VERSION 5.8 ;
BUSBITCHARS "[]" ;
DIVIDERCHAR "/" ;
UNITS
    DATABASE MICRONS 1000 ;
END UNITS

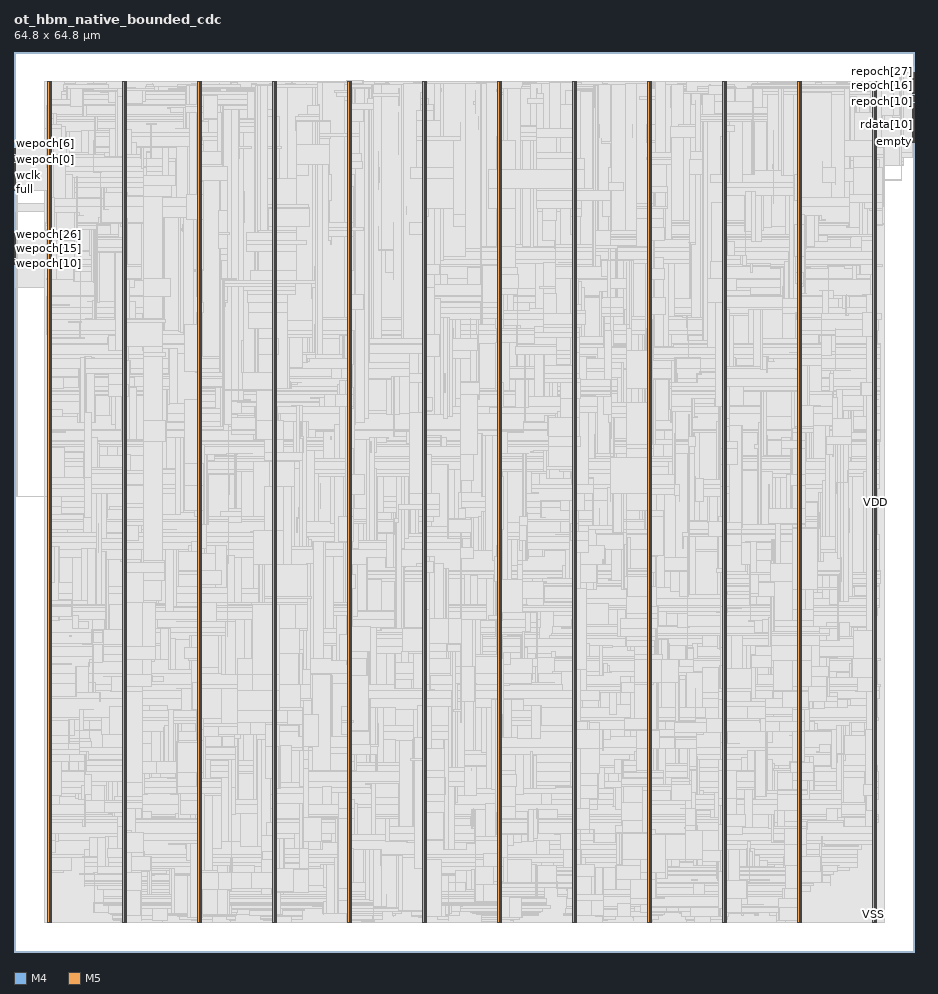
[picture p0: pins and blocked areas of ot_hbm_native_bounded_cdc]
MACRO ot_hbm_native_bounded_cdc
  FOREIGN ot_hbm_native_bounded_cdc 0 0 ;
  CLASS BLOCK ;
  SIZE 64.8 BY 64.8 ;
  PIN empty
    DIRECTION OUTPUT ;
    USE SIGNAL ;
    PORT
      LAYER M4 ;
        RECT  64.716 58.32 64.8 58.344 ;
    END
  END empty
  PIN full
    DIRECTION OUTPUT ;
    USE SIGNAL ;
    PORT
      LAYER M4 ;
        RECT  0 54.864 0.084 54.888 ;
    END
  END full
  PIN r_fault
    DIRECTION OUTPUT ;
    USE SIGNAL ;
    PORT
      LAYER M4 ;
        RECT  64.716 58.416 64.8 58.44 ;
    END
  END r_fault
  PIN rclk
    DIRECTION INPUT ;
    USE SIGNAL ;
    PORT
      LAYER M4 ;
        RECT  64.716 58.512 64.8 58.536 ;
    END
  END rclk
  PIN rd_freed[0]
    DIRECTION OUTPUT ;
    USE SIGNAL ;
    PORT
      LAYER M4 ;
        RECT  0 54.96 0.084 54.984 ;
    END
  END rd_freed[0]
  PIN rd_freed[1]
    DIRECTION OUTPUT ;
    USE SIGNAL ;
    PORT
      LAYER M4 ;
        RECT  0 55.056 0.084 55.08 ;
    END
  END rd_freed[1]
  PIN rd_freed[2]
    DIRECTION OUTPUT ;
    USE SIGNAL ;
    PORT
      LAYER M4 ;
        RECT  0 55.152 0.084 55.176 ;
    END
  END rd_freed[2]
  PIN rdata[0]
    DIRECTION OUTPUT ;
    USE SIGNAL ;
    PORT
      LAYER M4 ;
        RECT  64.716 58.608 64.8 58.632 ;
    END
  END rdata[0]
  PIN rdata[10]
    DIRECTION OUTPUT ;
    USE SIGNAL ;
    PORT
      LAYER M4 ;
        RECT  64.716 59.568 64.8 59.592 ;
    END
  END rdata[10]
  PIN rdata[11]
    DIRECTION OUTPUT ;
    USE SIGNAL ;
    PORT
      LAYER M4 ;
        RECT  64.716 59.664 64.8 59.688 ;
    END
  END rdata[11]
  PIN rdata[12]
    DIRECTION OUTPUT ;
    USE SIGNAL ;
    PORT
      LAYER M4 ;
        RECT  64.716 59.76 64.8 59.784 ;
    END
  END rdata[12]
  PIN rdata[13]
    DIRECTION OUTPUT ;
    USE SIGNAL ;
    PORT
      LAYER M4 ;
        RECT  64.716 59.856 64.8 59.88 ;
    END
  END rdata[13]
  PIN rdata[14]
    DIRECTION OUTPUT ;
    USE SIGNAL ;
    PORT
      LAYER M4 ;
        RECT  64.716 59.952 64.8 59.976 ;
    END
  END rdata[14]
  PIN rdata[15]
    DIRECTION OUTPUT ;
    USE SIGNAL ;
    PORT
      LAYER M4 ;
        RECT  64.716 60.048 64.8 60.072 ;
    END
  END rdata[15]
  PIN rdata[1]
    DIRECTION OUTPUT ;
    USE SIGNAL ;
    PORT
      LAYER M4 ;
        RECT  64.716 58.704 64.8 58.728 ;
    END
  END rdata[1]
  PIN rdata[2]
    DIRECTION OUTPUT ;
    USE SIGNAL ;
    PORT
      LAYER M4 ;
        RECT  64.716 58.8 64.8 58.824 ;
    END
  END rdata[2]
  PIN rdata[3]
    DIRECTION OUTPUT ;
    USE SIGNAL ;
    PORT
      LAYER M4 ;
        RECT  64.716 58.896 64.8 58.92 ;
    END
  END rdata[3]
  PIN rdata[4]
    DIRECTION OUTPUT ;
    USE SIGNAL ;
    PORT
      LAYER M4 ;
        RECT  64.716 58.992 64.8 59.016 ;
    END
  END rdata[4]
  PIN rdata[5]
    DIRECTION OUTPUT ;
    USE SIGNAL ;
    PORT
      LAYER M4 ;
        RECT  64.716 59.088 64.8 59.112 ;
    END
  END rdata[5]
  PIN rdata[6]
    DIRECTION OUTPUT ;
    USE SIGNAL ;
    PORT
      LAYER M4 ;
        RECT  64.716 59.184 64.8 59.208 ;
    END
  END rdata[6]
  PIN rdata[7]
    DIRECTION OUTPUT ;
    USE SIGNAL ;
    PORT
      LAYER M4 ;
        RECT  64.716 59.28 64.8 59.304 ;
    END
  END rdata[7]
  PIN rdata[8]
    DIRECTION OUTPUT ;
    USE SIGNAL ;
    PORT
      LAYER M4 ;
        RECT  64.716 59.376 64.8 59.4 ;
    END
  END rdata[8]
  PIN rdata[9]
    DIRECTION OUTPUT ;
    USE SIGNAL ;
    PORT
      LAYER M4 ;
        RECT  64.716 59.472 64.8 59.496 ;
    END
  END rdata[9]
  PIN re
    DIRECTION INPUT ;
    USE SIGNAL ;
    PORT
      LAYER M4 ;
        RECT  64.716 60.144 64.8 60.168 ;
    END
  END re
  PIN repoch[0]
    DIRECTION INPUT ;
    USE SIGNAL ;
    PORT
      LAYER M4 ;
        RECT  64.716 60.24 64.8 60.264 ;
    END
  END repoch[0]
  PIN repoch[10]
    DIRECTION INPUT ;
    USE SIGNAL ;
    PORT
      LAYER M4 ;
        RECT  64.716 61.2 64.8 61.224 ;
    END
  END repoch[10]
  PIN repoch[11]
    DIRECTION INPUT ;
    USE SIGNAL ;
    PORT
      LAYER M4 ;
        RECT  64.716 61.296 64.8 61.32 ;
    END
  END repoch[11]
  PIN repoch[12]
    DIRECTION INPUT ;
    USE SIGNAL ;
    PORT
      LAYER M4 ;
        RECT  64.716 61.392 64.8 61.416 ;
    END
  END repoch[12]
  PIN repoch[13]
    DIRECTION INPUT ;
    USE SIGNAL ;
    PORT
      LAYER M4 ;
        RECT  64.716 61.488 64.8 61.512 ;
    END
  END repoch[13]
  PIN repoch[14]
    DIRECTION INPUT ;
    USE SIGNAL ;
    PORT
      LAYER M4 ;
        RECT  64.716 61.584 64.8 61.608 ;
    END
  END repoch[14]
  PIN repoch[15]
    DIRECTION INPUT ;
    USE SIGNAL ;
    PORT
      LAYER M4 ;
        RECT  64.716 61.68 64.8 61.704 ;
    END
  END repoch[15]
  PIN repoch[16]
    DIRECTION INPUT ;
    USE SIGNAL ;
    PORT
      LAYER M4 ;
        RECT  64.716 61.776 64.8 61.8 ;
    END
  END repoch[16]
  PIN repoch[17]
    DIRECTION INPUT ;
    USE SIGNAL ;
    PORT
      LAYER M4 ;
        RECT  64.716 61.872 64.8 61.896 ;
    END
  END repoch[17]
  PIN repoch[18]
    DIRECTION INPUT ;
    USE SIGNAL ;
    PORT
      LAYER M4 ;
        RECT  64.716 61.968 64.8 61.992 ;
    END
  END repoch[18]
  PIN repoch[19]
    DIRECTION INPUT ;
    USE SIGNAL ;
    PORT
      LAYER M4 ;
        RECT  64.716 62.064 64.8 62.088 ;
    END
  END repoch[19]
  PIN repoch[1]
    DIRECTION INPUT ;
    USE SIGNAL ;
    PORT
      LAYER M4 ;
        RECT  64.716 60.336 64.8 60.36 ;
    END
  END repoch[1]
  PIN repoch[20]
    DIRECTION INPUT ;
    USE SIGNAL ;
    PORT
      LAYER M4 ;
        RECT  64.716 62.16 64.8 62.184 ;
    END
  END repoch[20]
  PIN repoch[21]
    DIRECTION INPUT ;
    USE SIGNAL ;
    PORT
      LAYER M4 ;
        RECT  64.716 62.256 64.8 62.28 ;
    END
  END repoch[21]
  PIN repoch[22]
    DIRECTION INPUT ;
    USE SIGNAL ;
    PORT
      LAYER M4 ;
        RECT  64.716 62.352 64.8 62.376 ;
    END
  END repoch[22]
  PIN repoch[23]
    DIRECTION INPUT ;
    USE SIGNAL ;
    PORT
      LAYER M4 ;
        RECT  64.716 62.448 64.8 62.472 ;
    END
  END repoch[23]
  PIN repoch[24]
    DIRECTION INPUT ;
    USE SIGNAL ;
    PORT
      LAYER M4 ;
        RECT  64.716 62.544 64.8 62.568 ;
    END
  END repoch[24]
  PIN repoch[25]
    DIRECTION INPUT ;
    USE SIGNAL ;
    PORT
      LAYER M4 ;
        RECT  64.716 62.64 64.8 62.664 ;
    END
  END repoch[25]
  PIN repoch[26]
    DIRECTION INPUT ;
    USE SIGNAL ;
    PORT
      LAYER M4 ;
        RECT  64.716 62.736 64.8 62.76 ;
    END
  END repoch[26]
  PIN repoch[27]
    DIRECTION INPUT ;
    USE SIGNAL ;
    PORT
      LAYER M4 ;
        RECT  64.716 62.832 64.8 62.856 ;
    END
  END repoch[27]
  PIN repoch[28]
    DIRECTION INPUT ;
    USE SIGNAL ;
    PORT
      LAYER M4 ;
        RECT  64.716 62.928 64.8 62.952 ;
    END
  END repoch[28]
  PIN repoch[29]
    DIRECTION INPUT ;
    USE SIGNAL ;
    PORT
      LAYER M4 ;
        RECT  64.716 63.024 64.8 63.048 ;
    END
  END repoch[29]
  PIN repoch[2]
    DIRECTION INPUT ;
    USE SIGNAL ;
    PORT
      LAYER M4 ;
        RECT  64.716 60.432 64.8 60.456 ;
    END
  END repoch[2]
  PIN repoch[30]
    DIRECTION INPUT ;
    USE SIGNAL ;
    PORT
      LAYER M4 ;
        RECT  64.716 63.12 64.8 63.144 ;
    END
  END repoch[30]
  PIN repoch[31]
    DIRECTION INPUT ;
    USE SIGNAL ;
    PORT
      LAYER M4 ;
        RECT  64.716 63.216 64.8 63.24 ;
    END
  END repoch[31]
  PIN repoch[3]
    DIRECTION INPUT ;
    USE SIGNAL ;
    PORT
      LAYER M4 ;
        RECT  64.716 60.528 64.8 60.552 ;
    END
  END repoch[3]
  PIN repoch[4]
    DIRECTION INPUT ;
    USE SIGNAL ;
    PORT
      LAYER M4 ;
        RECT  64.716 60.624 64.8 60.648 ;
    END
  END repoch[4]
  PIN repoch[5]
    DIRECTION INPUT ;
    USE SIGNAL ;
    PORT
      LAYER M4 ;
        RECT  64.716 60.72 64.8 60.744 ;
    END
  END repoch[5]
  PIN repoch[6]
    DIRECTION INPUT ;
    USE SIGNAL ;
    PORT
      LAYER M4 ;
        RECT  64.716 60.816 64.8 60.84 ;
    END
  END repoch[6]
  PIN repoch[7]
    DIRECTION INPUT ;
    USE SIGNAL ;
    PORT
      LAYER M4 ;
        RECT  64.716 60.912 64.8 60.936 ;
    END
  END repoch[7]
  PIN repoch[8]
    DIRECTION INPUT ;
    USE SIGNAL ;
    PORT
      LAYER M4 ;
        RECT  64.716 61.008 64.8 61.032 ;
    END
  END repoch[8]
  PIN repoch[9]
    DIRECTION INPUT ;
    USE SIGNAL ;
    PORT
      LAYER M4 ;
        RECT  64.716 61.104 64.8 61.128 ;
    END
  END repoch[9]
  PIN rrst_n
    DIRECTION INPUT ;
    USE SIGNAL ;
    PORT
      LAYER M4 ;
        RECT  64.716 63.312 64.8 63.336 ;
    END
  END rrst_n
  PIN w_fault
    DIRECTION OUTPUT ;
    USE SIGNAL ;
    PORT
      LAYER M4 ;
        RECT  0 55.248 0.084 55.272 ;
    END
  END w_fault
  PIN wclk
    DIRECTION INPUT ;
    USE SIGNAL ;
    PORT
      LAYER M4 ;
        RECT  0 55.344 0.084 55.368 ;
    END
  END wclk
  PIN wdata[0]
    DIRECTION INPUT ;
    USE SIGNAL ;
    PORT
      LAYER M4 ;
        RECT  0 55.44 0.084 55.464 ;
    END
  END wdata[0]
  PIN wdata[10]
    DIRECTION INPUT ;
    USE SIGNAL ;
    PORT
      LAYER M4 ;
        RECT  0 56.4 0.084 56.424 ;
    END
  END wdata[10]
  PIN wdata[11]
    DIRECTION INPUT ;
    USE SIGNAL ;
    PORT
      LAYER M4 ;
        RECT  0 56.496 0.084 56.52 ;
    END
  END wdata[11]
  PIN wdata[12]
    DIRECTION INPUT ;
    USE SIGNAL ;
    PORT
      LAYER M4 ;
        RECT  0 56.592 0.084 56.616 ;
    END
  END wdata[12]
  PIN wdata[13]
    DIRECTION INPUT ;
    USE SIGNAL ;
    PORT
      LAYER M4 ;
        RECT  0 56.688 0.084 56.712 ;
    END
  END wdata[13]
  PIN wdata[14]
    DIRECTION INPUT ;
    USE SIGNAL ;
    PORT
      LAYER M4 ;
        RECT  0 56.784 0.084 56.808 ;
    END
  END wdata[14]
  PIN wdata[15]
    DIRECTION INPUT ;
    USE SIGNAL ;
    PORT
      LAYER M4 ;
        RECT  0 56.88 0.084 56.904 ;
    END
  END wdata[15]
  PIN wdata[1]
    DIRECTION INPUT ;
    USE SIGNAL ;
    PORT
      LAYER M4 ;
        RECT  0 55.536 0.084 55.56 ;
    END
  END wdata[1]
  PIN wdata[2]
    DIRECTION INPUT ;
    USE SIGNAL ;
    PORT
      LAYER M4 ;
        RECT  0 55.632 0.084 55.656 ;
    END
  END wdata[2]
  PIN wdata[3]
    DIRECTION INPUT ;
    USE SIGNAL ;
    PORT
      LAYER M4 ;
        RECT  0 55.728 0.084 55.752 ;
    END
  END wdata[3]
  PIN wdata[4]
    DIRECTION INPUT ;
    USE SIGNAL ;
    PORT
      LAYER M4 ;
        RECT  0 55.824 0.084 55.848 ;
    END
  END wdata[4]
  PIN wdata[5]
    DIRECTION INPUT ;
    USE SIGNAL ;
    PORT
      LAYER M4 ;
        RECT  0 55.92 0.084 55.944 ;
    END
  END wdata[5]
  PIN wdata[6]
    DIRECTION INPUT ;
    USE SIGNAL ;
    PORT
      LAYER M4 ;
        RECT  0 56.016 0.084 56.04 ;
    END
  END wdata[6]
  PIN wdata[7]
    DIRECTION INPUT ;
    USE SIGNAL ;
    PORT
      LAYER M4 ;
        RECT  0 56.112 0.084 56.136 ;
    END
  END wdata[7]
  PIN wdata[8]
    DIRECTION INPUT ;
    USE SIGNAL ;
    PORT
      LAYER M4 ;
        RECT  0 56.208 0.084 56.232 ;
    END
  END wdata[8]
  PIN wdata[9]
    DIRECTION INPUT ;
    USE SIGNAL ;
    PORT
      LAYER M4 ;
        RECT  0 56.304 0.084 56.328 ;
    END
  END wdata[9]
  PIN we
    DIRECTION INPUT ;
    USE SIGNAL ;
    PORT
      LAYER M4 ;
        RECT  0 56.976 0.084 57 ;
    END
  END we
  PIN wepoch[0]
    DIRECTION INPUT ;
    USE SIGNAL ;
    PORT
      LAYER M4 ;
        RECT  0 57.072 0.084 57.096 ;
    END
  END wepoch[0]
  PIN wepoch[10]
    DIRECTION INPUT ;
    USE SIGNAL ;
    PORT
      LAYER M4 ;
        RECT  0 49.584 0.084 49.608 ;
    END
  END wepoch[10]
  PIN wepoch[11]
    DIRECTION INPUT ;
    USE SIGNAL ;
    PORT
      LAYER M4 ;
        RECT  0 49.68 0.084 49.704 ;
    END
  END wepoch[11]
  PIN wepoch[12]
    DIRECTION INPUT ;
    USE SIGNAL ;
    PORT
      LAYER M4 ;
        RECT  0 49.776 0.084 49.8 ;
    END
  END wepoch[12]
  PIN wepoch[13]
    DIRECTION INPUT ;
    USE SIGNAL ;
    PORT
      LAYER M4 ;
        RECT  0 49.872 0.084 49.896 ;
    END
  END wepoch[13]
  PIN wepoch[14]
    DIRECTION INPUT ;
    USE SIGNAL ;
    PORT
      LAYER M4 ;
        RECT  0 49.968 0.084 49.992 ;
    END
  END wepoch[14]
  PIN wepoch[15]
    DIRECTION INPUT ;
    USE SIGNAL ;
    PORT
      LAYER M4 ;
        RECT  0 50.064 0.084 50.088 ;
    END
  END wepoch[15]
  PIN wepoch[16]
    DIRECTION INPUT ;
    USE SIGNAL ;
    PORT
      LAYER M4 ;
        RECT  0 50.16 0.084 50.184 ;
    END
  END wepoch[16]
  PIN wepoch[17]
    DIRECTION INPUT ;
    USE SIGNAL ;
    PORT
      LAYER M4 ;
        RECT  0 50.256 0.084 50.28 ;
    END
  END wepoch[17]
  PIN wepoch[18]
    DIRECTION INPUT ;
    USE SIGNAL ;
    PORT
      LAYER M4 ;
        RECT  0 50.352 0.084 50.376 ;
    END
  END wepoch[18]
  PIN wepoch[19]
    DIRECTION INPUT ;
    USE SIGNAL ;
    PORT
      LAYER M4 ;
        RECT  0 50.448 0.084 50.472 ;
    END
  END wepoch[19]
  PIN wepoch[1]
    DIRECTION INPUT ;
    USE SIGNAL ;
    PORT
      LAYER M4 ;
        RECT  0 57.168 0.084 57.192 ;
    END
  END wepoch[1]
  PIN wepoch[20]
    DIRECTION INPUT ;
    USE SIGNAL ;
    PORT
      LAYER M4 ;
        RECT  0 50.544 0.084 50.568 ;
    END
  END wepoch[20]
  PIN wepoch[21]
    DIRECTION INPUT ;
    USE SIGNAL ;
    PORT
      LAYER M4 ;
        RECT  0 50.64 0.084 50.664 ;
    END
  END wepoch[21]
  PIN wepoch[22]
    DIRECTION INPUT ;
    USE SIGNAL ;
    PORT
      LAYER M4 ;
        RECT  0 50.736 0.084 50.76 ;
    END
  END wepoch[22]
  PIN wepoch[23]
    DIRECTION INPUT ;
    USE SIGNAL ;
    PORT
      LAYER M4 ;
        RECT  0 50.832 0.084 50.856 ;
    END
  END wepoch[23]
  PIN wepoch[24]
    DIRECTION INPUT ;
    USE SIGNAL ;
    PORT
      LAYER M4 ;
        RECT  0 50.928 0.084 50.952 ;
    END
  END wepoch[24]
  PIN wepoch[25]
    DIRECTION INPUT ;
    USE SIGNAL ;
    PORT
      LAYER M4 ;
        RECT  0 51.024 0.084 51.048 ;
    END
  END wepoch[25]
  PIN wepoch[26]
    DIRECTION INPUT ;
    USE SIGNAL ;
    PORT
      LAYER M4 ;
        RECT  0 51.12 0.084 51.144 ;
    END
  END wepoch[26]
  PIN wepoch[27]
    DIRECTION INPUT ;
    USE SIGNAL ;
    PORT
      LAYER M4 ;
        RECT  0 51.216 0.084 51.24 ;
    END
  END wepoch[27]
  PIN wepoch[28]
    DIRECTION INPUT ;
    USE SIGNAL ;
    PORT
      LAYER M4 ;
        RECT  0 51.312 0.084 51.336 ;
    END
  END wepoch[28]
  PIN wepoch[29]
    DIRECTION INPUT ;
    USE SIGNAL ;
    PORT
      LAYER M4 ;
        RECT  0 51.408 0.084 51.432 ;
    END
  END wepoch[29]
  PIN wepoch[2]
    DIRECTION INPUT ;
    USE SIGNAL ;
    PORT
      LAYER M4 ;
        RECT  0 57.264 0.084 57.288 ;
    END
  END wepoch[2]
  PIN wepoch[30]
    DIRECTION INPUT ;
    USE SIGNAL ;
    PORT
      LAYER M4 ;
        RECT  0 51.504 0.084 51.528 ;
    END
  END wepoch[30]
  PIN wepoch[31]
    DIRECTION INPUT ;
    USE SIGNAL ;
    PORT
      LAYER M4 ;
        RECT  0 51.6 0.084 51.624 ;
    END
  END wepoch[31]
  PIN wepoch[3]
    DIRECTION INPUT ;
    USE SIGNAL ;
    PORT
      LAYER M4 ;
        RECT  0 57.36 0.084 57.384 ;
    END
  END wepoch[3]
  PIN wepoch[4]
    DIRECTION INPUT ;
    USE SIGNAL ;
    PORT
      LAYER M4 ;
        RECT  0 57.456 0.084 57.48 ;
    END
  END wepoch[4]
  PIN wepoch[5]
    DIRECTION INPUT ;
    USE SIGNAL ;
    PORT
      LAYER M4 ;
        RECT  0 57.552 0.084 57.576 ;
    END
  END wepoch[5]
  PIN wepoch[6]
    DIRECTION INPUT ;
    USE SIGNAL ;
    PORT
      LAYER M4 ;
        RECT  0 57.648 0.084 57.672 ;
    END
  END wepoch[6]
  PIN wepoch[7]
    DIRECTION INPUT ;
    USE SIGNAL ;
    PORT
      LAYER M4 ;
        RECT  0 57.744 0.084 57.768 ;
    END
  END wepoch[7]
  PIN wepoch[8]
    DIRECTION INPUT ;
    USE SIGNAL ;
    PORT
      LAYER M4 ;
        RECT  0 57.84 0.084 57.864 ;
    END
  END wepoch[8]
  PIN wepoch[9]
    DIRECTION INPUT ;
    USE SIGNAL ;
    PORT
      LAYER M4 ;
        RECT  0 49.488 0.084 49.512 ;
    END
  END wepoch[9]
  PIN wrst_n
    DIRECTION INPUT ;
    USE SIGNAL ;
    PORT
      LAYER M4 ;
        RECT  0 51.696 0.084 51.72 ;
    END
  END wrst_n
  PIN VDD
    DIRECTION INOUT ;
    USE POWER ;
    PORT
      LAYER M5 ;
        RECT  61.992 2.151 62.112 62.649 ;
        RECT  56.592 2.151 56.712 62.649 ;
        RECT  51.192 2.151 51.312 62.649 ;
        RECT  45.792 2.151 45.912 62.649 ;
        RECT  40.392 2.151 40.512 62.649 ;
        RECT  34.992 2.151 35.112 62.649 ;
        RECT  29.592 2.151 29.712 62.649 ;
        RECT  24.192 2.151 24.312 62.649 ;
        RECT  18.792 2.151 18.912 62.649 ;
        RECT  13.392 2.151 13.512 62.649 ;
        RECT  7.992 2.151 8.112 62.649 ;
        RECT  2.592 2.151 2.712 62.649 ;
    END
  END VDD
  PIN VSS
    DIRECTION INOUT ;
    USE GROUND ;
    PORT
      LAYER M5 ;
        RECT  61.8 2.137 61.92 62.663 ;
        RECT  56.4 2.137 56.52 62.663 ;
        RECT  51 2.137 51.12 62.663 ;
        RECT  45.6 2.137 45.72 62.663 ;
        RECT  40.2 2.137 40.32 62.663 ;
        RECT  34.8 2.137 34.92 62.663 ;
        RECT  29.4 2.137 29.52 62.663 ;
        RECT  24 2.137 24.12 62.663 ;
        RECT  18.6 2.137 18.72 62.663 ;
        RECT  13.2 2.137 13.32 62.663 ;
        RECT  7.8 2.137 7.92 62.663 ;
        RECT  2.4 2.137 2.52 62.663 ;
    END
  END VSS
  # OT_OBS_CLOSED layer=M5 d_um=1.536 added=470
  OBS
    LAYER RVTN ;
     RECT  2.16 2.16 62.64 2.295 ;
     RECT  2.16 2.565 62.64 2.835 ;
     RECT  2.16 3.105 62.64 3.375 ;
     RECT  2.16 3.645 62.64 3.915 ;
     RECT  2.16 4.185 62.64 4.455 ;
     RECT  2.16 4.725 62.64 4.995 ;
     RECT  2.16 5.265 62.64 5.535 ;
     RECT  2.16 5.805 62.64 6.075 ;
     RECT  2.16 6.345 62.64 6.615 ;
     RECT  2.16 6.885 62.64 7.155 ;
     RECT  2.16 7.425 62.64 7.695 ;
     RECT  2.16 7.965 62.64 8.235 ;
     RECT  2.16 8.505 62.64 8.775 ;
     RECT  2.16 9.045 62.64 9.315 ;
     RECT  2.16 9.585 62.64 9.855 ;
     RECT  2.16 10.125 62.64 10.395 ;
     RECT  2.16 10.665 62.64 10.935 ;
     RECT  2.16 11.205 62.64 11.475 ;
     RECT  2.16 11.745 62.64 12.015 ;
     RECT  2.16 12.285 62.64 12.555 ;
     RECT  2.16 12.825 62.64 13.095 ;
     RECT  2.16 13.365 62.64 13.635 ;
     RECT  2.16 13.905 62.64 14.175 ;
     RECT  2.16 14.445 62.64 14.715 ;
     RECT  2.16 14.985 62.64 15.255 ;
     RECT  2.16 15.525 62.64 15.795 ;
     RECT  2.16 16.065 62.64 16.335 ;
     RECT  2.16 16.605 62.64 16.875 ;
     RECT  2.16 17.145 62.64 17.415 ;
     RECT  2.16 17.685 62.64 17.955 ;
     RECT  2.16 18.225 62.64 18.495 ;
     RECT  2.16 18.765 62.64 19.035 ;
     RECT  2.16 19.305 62.64 19.575 ;
     RECT  2.16 19.845 62.64 20.115 ;
     RECT  2.16 20.385 62.64 20.655 ;
     RECT  2.16 20.925 62.64 21.195 ;
     RECT  2.16 21.465 62.64 21.735 ;
     RECT  2.16 22.005 62.64 22.275 ;
     RECT  2.16 22.545 62.64 22.815 ;
     RECT  2.16 23.085 62.64 23.355 ;
     RECT  2.16 23.625 62.64 23.895 ;
     RECT  2.16 24.165 62.64 24.435 ;
     RECT  2.16 24.705 62.64 24.975 ;
     RECT  2.16 25.245 62.64 25.515 ;
     RECT  2.16 25.785 62.64 26.055 ;
     RECT  2.16 26.325 62.64 26.595 ;
     RECT  2.16 26.865 62.64 27.135 ;
     RECT  2.16 27.405 62.64 27.675 ;
     RECT  2.16 27.945 62.64 28.215 ;
     RECT  2.16 28.485 62.64 28.755 ;
     RECT  2.16 29.025 62.64 29.295 ;
     RECT  2.16 29.565 62.64 29.835 ;
     RECT  2.16 30.105 62.64 30.375 ;
     RECT  2.16 30.645 62.64 30.915 ;
     RECT  2.16 31.185 62.64 31.455 ;
     RECT  2.16 31.725 62.64 31.995 ;
     RECT  2.16 32.265 62.64 32.535 ;
     RECT  2.16 32.805 62.64 33.075 ;
     RECT  2.16 33.345 62.64 33.615 ;
     RECT  2.16 33.885 62.64 34.155 ;
     RECT  2.16 34.425 62.64 34.695 ;
     RECT  2.16 34.965 62.64 35.235 ;
     RECT  2.16 35.505 62.64 35.775 ;
     RECT  2.16 36.045 62.64 36.315 ;
     RECT  2.16 36.585 62.64 36.855 ;
     RECT  2.16 37.125 62.64 37.395 ;
     RECT  2.16 37.665 62.64 37.935 ;
     RECT  2.16 38.205 62.64 38.475 ;
     RECT  2.16 38.745 62.64 39.015 ;
     RECT  2.16 39.285 62.64 39.555 ;
     RECT  2.16 39.825 62.64 40.095 ;
     RECT  2.16 40.365 62.64 40.635 ;
     RECT  2.16 40.905 62.64 41.175 ;
     RECT  2.16 41.445 62.64 41.715 ;
     RECT  2.16 41.985 62.64 42.255 ;
     RECT  2.16 42.525 62.64 42.795 ;
     RECT  2.16 43.065 62.64 43.335 ;
     RECT  2.16 43.605 62.64 43.875 ;
     RECT  2.16 44.145 62.64 44.415 ;
     RECT  2.16 44.685 62.64 44.955 ;
     RECT  2.16 45.225 62.64 45.495 ;
     RECT  2.16 45.765 62.64 46.035 ;
     RECT  2.16 46.305 62.64 46.575 ;
     RECT  2.16 46.845 62.64 47.115 ;
     RECT  2.16 47.385 62.64 47.655 ;
     RECT  2.16 47.925 62.64 48.195 ;
     RECT  2.16 48.465 62.64 48.735 ;
     RECT  2.16 49.005 62.64 49.275 ;
     RECT  2.16 49.545 62.64 49.815 ;
     RECT  2.16 50.085 62.64 50.355 ;
     RECT  2.16 50.625 62.64 50.895 ;
     RECT  2.16 51.165 62.64 51.435 ;
     RECT  2.16 51.705 62.64 51.975 ;
     RECT  2.16 52.245 62.64 52.515 ;
     RECT  2.16 52.785 62.64 53.055 ;
     RECT  2.16 53.325 62.64 53.595 ;
     RECT  2.16 53.865 62.64 54.135 ;
     RECT  2.16 54.405 62.64 54.675 ;
     RECT  2.16 54.945 62.64 55.215 ;
     RECT  2.16 55.485 62.64 55.755 ;
     RECT  2.16 56.025 62.64 56.295 ;
     RECT  2.16 56.565 62.64 56.835 ;
     RECT  2.16 57.105 62.64 57.375 ;
     RECT  2.16 57.645 62.64 57.915 ;
     RECT  2.16 58.185 62.64 58.455 ;
     RECT  2.16 58.725 62.64 58.995 ;
     RECT  2.16 59.265 62.64 59.535 ;
     RECT  2.16 59.805 62.64 60.075 ;
     RECT  2.16 60.345 62.64 60.615 ;
     RECT  2.16 60.885 62.64 61.155 ;
     RECT  2.16 61.425 62.64 61.695 ;
     RECT  2.16 61.965 62.64 62.235 ;
     RECT  2.16 62.505 62.64 62.64 ;
    LAYER RVTP ;
     RECT  2.16 2.295 62.64 2.565 ;
     RECT  2.16 2.835 62.64 3.105 ;
     RECT  2.16 3.375 62.64 3.645 ;
     RECT  2.16 3.915 62.64 4.185 ;
     RECT  2.16 4.455 62.64 4.725 ;
     RECT  2.16 4.995 62.64 5.265 ;
     RECT  2.16 5.535 62.64 5.805 ;
     RECT  2.16 6.075 62.64 6.345 ;
     RECT  2.16 6.615 62.64 6.885 ;
     RECT  2.16 7.155 62.64 7.425 ;
     RECT  2.16 7.695 62.64 7.965 ;
     RECT  2.16 8.235 62.64 8.505 ;
     RECT  2.16 8.775 62.64 9.045 ;
     RECT  2.16 9.315 62.64 9.585 ;
     RECT  2.16 9.855 62.64 10.125 ;
     RECT  2.16 10.395 62.64 10.665 ;
     RECT  2.16 10.935 62.64 11.205 ;
     RECT  2.16 11.475 62.64 11.745 ;
     RECT  2.16 12.015 62.64 12.285 ;
     RECT  2.16 12.555 62.64 12.825 ;
     RECT  2.16 13.095 62.64 13.365 ;
     RECT  2.16 13.635 62.64 13.905 ;
     RECT  2.16 14.175 62.64 14.445 ;
     RECT  2.16 14.715 62.64 14.985 ;
     RECT  2.16 15.255 62.64 15.525 ;
     RECT  2.16 15.795 62.64 16.065 ;
     RECT  2.16 16.335 62.64 16.605 ;
     RECT  2.16 16.875 62.64 17.145 ;
     RECT  2.16 17.415 62.64 17.685 ;
     RECT  2.16 17.955 62.64 18.225 ;
     RECT  2.16 18.495 62.64 18.765 ;
     RECT  2.16 19.035 62.64 19.305 ;
     RECT  2.16 19.575 62.64 19.845 ;
     RECT  2.16 20.115 62.64 20.385 ;
     RECT  2.16 20.655 62.64 20.925 ;
     RECT  2.16 21.195 62.64 21.465 ;
     RECT  2.16 21.735 62.64 22.005 ;
     RECT  2.16 22.275 62.64 22.545 ;
     RECT  2.16 22.815 62.64 23.085 ;
     RECT  2.16 23.355 62.64 23.625 ;
     RECT  2.16 23.895 62.64 24.165 ;
     RECT  2.16 24.435 62.64 24.705 ;
     RECT  2.16 24.975 62.64 25.245 ;
     RECT  2.16 25.515 62.64 25.785 ;
     RECT  2.16 26.055 62.64 26.325 ;
     RECT  2.16 26.595 62.64 26.865 ;
     RECT  2.16 27.135 62.64 27.405 ;
     RECT  2.16 27.675 62.64 27.945 ;
     RECT  2.16 28.215 62.64 28.485 ;
     RECT  2.16 28.755 62.64 29.025 ;
     RECT  2.16 29.295 62.64 29.565 ;
     RECT  2.16 29.835 62.64 30.105 ;
     RECT  2.16 30.375 62.64 30.645 ;
     RECT  2.16 30.915 62.64 31.185 ;
     RECT  2.16 31.455 62.64 31.725 ;
     RECT  2.16 31.995 62.64 32.265 ;
     RECT  2.16 32.535 62.64 32.805 ;
     RECT  2.16 33.075 62.64 33.345 ;
     RECT  2.16 33.615 62.64 33.885 ;
     RECT  2.16 34.155 62.64 34.425 ;
     RECT  2.16 34.695 62.64 34.965 ;
     RECT  2.16 35.235 62.64 35.505 ;
     RECT  2.16 35.775 62.64 36.045 ;
     RECT  2.16 36.315 62.64 36.585 ;
     RECT  2.16 36.855 62.64 37.125 ;
     RECT  2.16 37.395 62.64 37.665 ;
     RECT  2.16 37.935 62.64 38.205 ;
     RECT  2.16 38.475 62.64 38.745 ;
     RECT  2.16 39.015 62.64 39.285 ;
     RECT  2.16 39.555 62.64 39.825 ;
     RECT  2.16 40.095 62.64 40.365 ;
     RECT  2.16 40.635 62.64 40.905 ;
     RECT  2.16 41.175 62.64 41.445 ;
     RECT  2.16 41.715 62.64 41.985 ;
     RECT  2.16 42.255 62.64 42.525 ;
     RECT  2.16 42.795 62.64 43.065 ;
     RECT  2.16 43.335 62.64 43.605 ;
     RECT  2.16 43.875 62.64 44.145 ;
     RECT  2.16 44.415 62.64 44.685 ;
     RECT  2.16 44.955 62.64 45.225 ;
     RECT  2.16 45.495 62.64 45.765 ;
     RECT  2.16 46.035 62.64 46.305 ;
     RECT  2.16 46.575 62.64 46.845 ;
     RECT  2.16 47.115 62.64 47.385 ;
     RECT  2.16 47.655 62.64 47.925 ;
     RECT  2.16 48.195 62.64 48.465 ;
     RECT  2.16 48.735 62.64 49.005 ;
     RECT  2.16 49.275 62.64 49.545 ;
     RECT  2.16 49.815 62.64 50.085 ;
     RECT  2.16 50.355 62.64 50.625 ;
     RECT  2.16 50.895 62.64 51.165 ;
     RECT  2.16 51.435 62.64 51.705 ;
     RECT  2.16 51.975 62.64 52.245 ;
     RECT  2.16 52.515 62.64 52.785 ;
     RECT  2.16 53.055 62.64 53.325 ;
     RECT  2.16 53.595 62.64 53.865 ;
     RECT  2.16 54.135 62.64 54.405 ;
     RECT  2.16 54.675 62.64 54.945 ;
     RECT  2.16 55.215 62.64 55.485 ;
     RECT  2.16 55.755 62.64 56.025 ;
     RECT  2.16 56.295 62.64 56.565 ;
     RECT  2.16 56.835 62.64 57.105 ;
     RECT  2.16 57.375 62.64 57.645 ;
     RECT  2.16 57.915 62.64 58.185 ;
     RECT  2.16 58.455 62.64 58.725 ;
     RECT  2.16 58.995 62.64 59.265 ;
     RECT  2.16 59.535 62.64 59.805 ;
     RECT  2.16 60.075 62.64 60.345 ;
     RECT  2.16 60.615 62.64 60.885 ;
     RECT  2.16 61.155 62.64 61.425 ;
     RECT  2.16 61.695 62.64 61.965 ;
     RECT  2.16 62.235 62.64 62.505 ;
    LAYER M1 ;
     RECT  2.16 2.151 62.64 62.649 ;
    LAYER M2 ;
     RECT  0.103 48.24 0.139 48.258 ;
     RECT  0.103 50.13 0.139 51.228 ;
     RECT  0.103 53.874 0.139 53.892 ;
     RECT  0.139 50.022 0.175 51.228 ;
     RECT  0.103 56.232 0.203 56.25 ;
     RECT  0.139 47.862 0.211 48.258 ;
     RECT  0.175 49.32 0.211 51.228 ;
     RECT  0.211 47.862 2.16 51.228 ;
     RECT  0.139 53.334 2.16 53.892 ;
     RECT  2.16 2.151 15.619 62.649 ;
     RECT  15.619 2.151 23.971 62.694 ;
     RECT  23.971 2.151 25.151 62.766 ;
     RECT  25.151 2.151 25.951 62.649 ;
     RECT  25.951 2.151 33.691 62.694 ;
     RECT  33.691 2.106 34.691 62.694 ;
     RECT  34.691 2.151 48.407 62.694 ;
     RECT  48.407 2.151 55.543 62.649 ;
     RECT  55.543 2.151 62.64 62.694 ;
     RECT  62.64 56.646 63.779 62.694 ;
     RECT  63.779 56.646 63.887 62.496 ;
     RECT  62.64 55.566 63.923 55.584 ;
     RECT  63.887 56.646 63.959 62.46 ;
     RECT  63.959 56.646 64.031 58.716 ;
     RECT  63.959 59.814 64.031 62.226 ;
     RECT  64.031 56.736 64.067 58.716 ;
     RECT  64.067 57.186 64.571 58.716 ;
     RECT  64.571 58.356 64.607 58.716 ;
     RECT  64.607 58.698 64.643 58.716 ;
     RECT  64.571 57.186 64.679 57.564 ;
     RECT  64.031 59.814 64.679 60.444 ;
     RECT  64.031 61.398 64.679 62.226 ;
     RECT  64.679 57.546 64.715 57.564 ;
     RECT  64.679 60.426 64.715 60.444 ;
     RECT  64.679 61.398 64.715 61.416 ;
     RECT  64.679 62.208 64.715 62.226 ;
    LAYER M3 ;
     RECT  34.668 2.101 34.686 2.143 ;
     RECT  33.696 2.101 33.714 2.191 ;
     RECT  34.668 2.143 34.905 2.191 ;
     RECT  45.615 2.143 45.705 2.191 ;
     RECT  7.815 2.143 7.905 2.227 ;
     RECT  29.415 2.143 29.505 2.227 ;
     RECT  7.668 2.227 7.905 2.263 ;
     RECT  10.692 2.191 10.71 2.263 ;
     RECT  13.215 2.143 13.305 2.263 ;
     RECT  18.615 2.143 18.705 2.263 ;
     RECT  35.928 2.191 35.946 2.263 ;
     RECT  42.372 2.227 42.39 2.263 ;
     RECT  54.9 2.227 54.918 2.263 ;
     RECT  10.008 2.263 10.71 2.299 ;
     RECT  24.015 2.143 24.105 2.299 ;
     RECT  25.02 2.227 25.866 2.299 ;
     RECT  48.996 2.227 49.014 2.299 ;
     RECT  9.144 2.263 9.162 2.335 ;
     RECT  10.008 2.299 11.034 2.335 ;
     RECT  12.744 2.263 13.374 2.335 ;
     RECT  15.516 2.263 15.93 2.335 ;
     RECT  17.964 2.263 18.705 2.335 ;
     RECT  19.944 2.191 19.962 2.335 ;
     RECT  35.712 2.263 35.946 2.335 ;
     RECT  48.384 2.299 49.014 2.335 ;
     RECT  7.164 2.263 7.905 2.371 ;
     RECT  11.88 2.335 13.374 2.371 ;
     RECT  14.256 2.227 14.274 2.371 ;
     RECT  17.82 2.335 18.705 2.371 ;
     RECT  19.944 2.335 20.286 2.371 ;
     RECT  24.015 2.299 25.866 2.371 ;
     RECT  31.248 2.299 31.266 2.371 ;
     RECT  33.66 2.191 34.905 2.371 ;
     RECT  35.712 2.335 36.378 2.371 ;
     RECT  42.372 2.263 42.75 2.371 ;
     RECT  44.568 2.263 44.586 2.371 ;
     RECT  45.615 2.191 45.99 2.371 ;
     RECT  50.148 2.227 50.166 2.371 ;
     RECT  51.015 2.143 51.105 2.371 ;
     RECT  54.9 2.263 55.134 2.371 ;
     RECT  2.415 2.143 2.505 2.413 ;
     RECT  7.092 2.371 7.905 2.413 ;
     RECT  17.712 2.371 18.705 2.413 ;
     RECT  29.415 2.227 29.574 2.413 ;
     RECT  40.215 2.143 40.305 2.413 ;
     RECT  56.415 2.143 56.505 2.413 ;
     RECT  61.815 2.143 61.905 2.413 ;
     RECT  44.568 2.371 44.622 2.461 ;
     RECT  33.66 2.371 36.378 2.488 ;
     RECT  29.415 2.413 29.697 2.497 ;
     RECT  11.88 2.371 14.274 2.533 ;
     RECT  29.124 2.497 29.697 2.533 ;
     RECT  30.456 2.371 31.266 2.533 ;
     RECT  44.496 2.461 44.622 2.533 ;
     RECT  11.772 2.533 14.274 2.569 ;
     RECT  15.3 2.335 15.93 2.569 ;
     RECT  17.712 2.413 18.897 2.569 ;
     RECT  19.944 2.371 20.79 2.569 ;
     RECT  50.148 2.371 51.354 2.569 ;
     RECT  48.312 2.335 49.014 2.582 ;
     RECT  42.372 2.371 43.326 2.587 ;
     RECT  44.46 2.533 44.622 2.587 ;
     RECT  48.06 2.582 49.014 2.587 ;
     RECT  49.788 2.569 51.354 2.587 ;
     RECT  7.092 2.413 8.097 2.605 ;
     RECT  9.144 2.335 11.034 2.605 ;
     RECT  11.772 2.569 15.93 2.605 ;
     RECT  17.712 2.569 20.79 2.605 ;
     RECT  24.015 2.371 26.514 2.605 ;
     RECT  27.324 2.533 27.342 2.605 ;
     RECT  41.868 2.587 43.65 2.605 ;
     RECT  28.62 2.533 31.266 2.641 ;
     RECT  33.66 2.488 36.594 2.641 ;
     RECT  37.476 2.605 37.782 2.641 ;
     RECT  40.215 2.413 40.497 2.641 ;
     RECT  45.615 2.371 46.422 2.641 ;
     RECT  54.9 2.371 55.674 2.641 ;
     RECT  56.415 2.413 56.697 2.641 ;
     RECT  7.092 2.605 16.002 2.669 ;
     RECT  7.092 2.669 14.67 2.731 ;
     RECT  33.624 2.641 37.782 2.731 ;
     RECT  39.564 2.641 40.842 2.731 ;
     RECT  41.76 2.605 43.65 2.731 ;
     RECT  44.46 2.587 44.694 2.731 ;
     RECT  45.576 2.641 46.71 2.731 ;
     RECT  53.316 2.641 53.622 2.731 ;
     RECT  27.252 2.605 27.45 2.767 ;
     RECT  23.904 2.605 26.514 2.779 ;
     RECT  52.38 2.641 52.542 2.779 ;
     RECT  39.564 2.731 44.694 2.795 ;
     RECT  6.948 2.731 14.67 2.803 ;
     RECT  33.264 2.731 37.782 2.803 ;
     RECT  48.06 2.587 51.462 2.803 ;
     RECT  52.272 2.779 52.542 2.803 ;
     RECT  53.28 2.731 53.622 2.803 ;
     RECT  15.408 2.669 16.002 2.839 ;
     RECT  32.976 2.803 37.782 2.839 ;
     RECT  47.88 2.803 53.622 2.839 ;
     RECT  54.396 2.641 56.697 2.839 ;
     RECT  47.88 2.839 56.697 2.869 ;
     RECT  45.576 2.731 46.818 2.875 ;
     RECT  22.248 2.731 22.266 2.911 ;
     RECT  23.364 2.779 26.514 2.911 ;
     RECT  27.252 2.767 27.882 2.911 ;
     RECT  28.62 2.641 32.058 2.911 ;
     RECT  32.832 2.839 37.89 2.911 ;
     RECT  16.92 2.605 20.79 3.001 ;
     RECT  15.408 2.839 16.11 3.037 ;
     RECT  15.408 3.037 16.182 3.073 ;
     RECT  16.92 3.001 20.898 3.073 ;
     RECT  39.708 2.795 44.694 3.101 ;
     RECT  22.248 2.911 38.07 3.109 ;
     RECT  15.408 3.073 20.898 3.145 ;
     RECT  22.248 3.109 38.61 3.145 ;
     RECT  45.576 2.875 46.962 3.181 ;
     RECT  47.808 2.869 56.697 3.181 ;
     RECT  39.78 3.101 44.694 3.307 ;
     RECT  45.576 3.181 56.697 3.307 ;
     RECT  15.408 3.145 38.61 3.335 ;
     RECT  6.768 2.803 14.67 3.343 ;
     RECT  6.444 3.343 14.67 3.451 ;
     RECT  15.408 3.335 38.322 3.451 ;
     RECT  6.444 3.451 38.322 3.499 ;
     RECT  5.724 3.499 38.322 3.569 ;
     RECT  6.444 3.569 38.322 3.839 ;
     RECT  39.78 3.307 56.697 3.991 ;
     RECT  6.444 3.839 38.178 4.013 ;
     RECT  39.096 3.991 56.697 4.109 ;
     RECT  12.276 4.013 38.178 4.145 ;
     RECT  49.68 4.109 56.697 4.351 ;
     RECT  12.42 4.145 38.178 4.379 ;
     RECT  6.444 4.013 11.43 4.531 ;
     RECT  32.508 4.379 38.178 4.657 ;
     RECT  39.096 4.109 48.942 4.657 ;
     RECT  5.076 4.729 5.094 4.801 ;
     RECT  5.976 4.531 11.43 4.801 ;
     RECT  49.68 4.351 57.33 4.801 ;
     RECT  32.508 4.657 48.942 4.919 ;
     RECT  5.076 4.801 11.43 4.927 ;
     RECT  38.664 4.919 48.942 4.927 ;
     RECT  49.68 4.801 57.582 4.927 ;
     RECT  38.664 4.927 57.582 5.029 ;
     RECT  58.752 4.801 58.77 5.029 ;
     RECT  5.076 4.927 11.502 5.071 ;
     RECT  12.42 4.379 31.77 5.071 ;
     RECT  5.076 5.071 31.77 5.179 ;
     RECT  32.508 4.919 37.89 5.179 ;
     RECT  38.664 5.029 58.77 5.495 ;
     RECT  38.844 5.495 58.77 5.575 ;
     RECT  5.076 5.179 37.89 5.605 ;
     RECT  4.752 5.605 37.89 5.645 ;
     RECT  2.415 2.413 2.697 5.737 ;
     RECT  3.564 5.701 3.582 5.737 ;
     RECT  38.844 5.575 58.986 5.803 ;
     RECT  2.415 5.737 3.582 5.845 ;
     RECT  38.844 5.803 59.31 5.845 ;
     RECT  38.844 5.845 59.454 5.881 ;
     RECT  38.844 5.881 60.138 6.115 ;
     RECT  5.076 5.645 37.89 6.151 ;
     RECT  5.076 6.151 37.962 6.421 ;
     RECT  38.844 6.115 60.75 6.421 ;
     RECT  5.076 6.421 60.75 6.781 ;
     RECT  2.415 5.845 4.122 6.817 ;
     RECT  4.968 6.781 60.75 6.817 ;
     RECT  2.415 6.817 60.75 6.989 ;
     RECT  38.52 6.989 60.75 7.393 ;
     RECT  38.52 7.393 61.002 7.771 ;
     RECT  61.815 2.413 62.097 7.771 ;
     RECT  2.415 6.989 37.638 8.005 ;
     RECT  38.52 7.771 62.097 8.005 ;
     RECT  2.415 8.005 62.097 8.545 ;
     RECT  2.376 8.545 62.097 9.319 ;
     RECT  2.376 9.319 62.262 9.509 ;
     RECT  2.415 9.509 62.262 9.779 ;
     RECT  2.415 9.779 62.226 9.887 ;
     RECT  2.415 9.887 62.097 10.589 ;
     RECT  38.7 10.589 62.097 11.011 ;
     RECT  2.415 10.589 37.962 11.407 ;
     RECT  38.7 11.011 62.226 11.407 ;
     RECT  2.415 11.407 62.226 11.821 ;
     RECT  2.415 11.821 62.262 12.245 ;
     RECT  2.415 12.245 42.786 12.991 ;
     RECT  43.524 12.245 62.262 12.991 ;
     RECT  2.415 12.991 62.262 13.019 ;
     RECT  2.415 13.019 62.19 13.433 ;
     RECT  2.415 13.433 62.097 14.251 ;
     RECT  2.376 14.251 62.097 14.711 ;
     RECT  2.415 14.711 5.562 15.179 ;
     RECT  2.415 15.179 5.49 15.359 ;
     RECT  6.336 14.711 62.097 15.871 ;
     RECT  2.415 15.359 5.418 16.645 ;
     RECT  6.264 15.871 62.097 16.645 ;
     RECT  2.415 16.645 62.097 16.681 ;
     RECT  2.415 16.681 62.226 16.871 ;
     RECT  2.415 16.871 62.19 18.265 ;
     RECT  2.415 18.265 62.334 18.833 ;
     RECT  40.215 18.833 62.334 19.111 ;
     RECT  2.415 18.833 39.474 19.229 ;
     RECT  40.215 19.111 62.37 19.229 ;
     RECT  40.215 19.229 62.226 19.265 ;
     RECT  2.415 19.229 39.438 20.075 ;
     RECT  38.772 20.075 39.438 20.183 ;
     RECT  38.844 20.183 39.438 20.191 ;
     RECT  40.215 19.265 62.19 20.191 ;
     RECT  38.844 20.191 62.19 20.219 ;
     RECT  38.88 20.219 62.19 20.965 ;
     RECT  38.88 20.965 62.406 21.119 ;
     RECT  2.415 20.075 37.638 21.271 ;
     RECT  38.88 21.119 62.097 21.271 ;
     RECT  2.376 21.271 62.097 21.971 ;
     RECT  2.376 21.971 24.498 22.235 ;
     RECT  25.344 21.971 62.097 22.541 ;
     RECT  38.556 22.541 62.097 22.811 ;
     RECT  25.344 22.541 37.818 22.891 ;
     RECT  38.7 22.811 62.097 22.919 ;
     RECT  2.415 22.235 24.498 23.009 ;
     RECT  6.516 23.009 24.498 23.035 ;
     RECT  25.308 22.891 37.818 23.035 ;
     RECT  6.516 23.035 37.818 23.395 ;
     RECT  38.772 22.919 62.097 23.459 ;
     RECT  2.415 23.009 5.634 23.971 ;
     RECT  6.516 23.395 37.926 23.971 ;
     RECT  38.844 23.459 62.097 24.205 ;
     RECT  2.415 23.971 37.926 24.511 ;
     RECT  38.844 24.205 62.154 24.511 ;
     RECT  2.415 24.511 62.154 24.781 ;
     RECT  2.415 24.781 62.334 24.935 ;
     RECT  2.415 24.935 36.99 25.043 ;
     RECT  38.124 24.935 62.334 25.475 ;
     RECT  2.415 25.043 36.882 25.825 ;
     RECT  38.16 25.475 62.334 26.329 ;
     RECT  38.124 26.329 62.334 26.365 ;
     RECT  38.052 26.365 62.334 26.563 ;
     RECT  2.415 25.825 37.314 26.869 ;
     RECT  38.052 26.563 62.406 26.869 ;
     RECT  2.415 26.869 62.406 27.163 ;
     RECT  2.412 27.163 62.406 27.365 ;
     RECT  2.415 27.365 62.406 27.473 ;
     RECT  2.415 27.473 62.298 28.949 ;
     RECT  2.415 28.949 41.202 29.489 ;
     RECT  2.415 29.489 41.13 29.911 ;
     RECT  41.94 28.949 62.298 30.029 ;
     RECT  41.94 30.029 62.154 30.145 ;
     RECT  2.376 29.911 41.13 30.173 ;
     RECT  40.068 30.173 41.13 30.451 ;
     RECT  41.868 30.145 62.154 30.451 ;
     RECT  2.376 30.173 39.33 30.991 ;
     RECT  40.068 30.451 62.154 30.991 ;
     RECT  2.376 30.991 62.154 31.109 ;
     RECT  2.415 31.109 62.154 32.035 ;
     RECT  2.415 32.035 62.226 32.459 ;
     RECT  2.415 32.459 62.154 33.385 ;
     RECT  2.415 33.385 62.298 33.677 ;
     RECT  2.415 33.677 37.062 34.429 ;
     RECT  37.8 33.677 62.298 34.429 ;
     RECT  2.415 34.429 62.298 34.735 ;
     RECT  2.415 34.735 62.334 35.303 ;
     RECT  2.415 35.303 62.298 35.501 ;
     RECT  7.452 35.501 62.298 35.699 ;
     RECT  2.415 35.501 6.714 36.391 ;
     RECT  7.452 35.699 46.026 36.391 ;
     RECT  2.415 36.391 46.026 36.553 ;
     RECT  46.764 35.699 62.298 36.553 ;
     RECT  2.415 36.553 62.298 36.787 ;
     RECT  2.415 36.787 62.37 36.815 ;
     RECT  46.8 36.815 62.37 36.931 ;
     RECT  2.415 36.815 46.062 37.579 ;
     RECT  46.8 36.931 62.406 37.579 ;
     RECT  2.415 37.579 62.406 37.589 ;
     RECT  2.415 37.589 62.37 38.777 ;
     RECT  16.344 38.777 62.37 39.293 ;
     RECT  16.344 39.293 22.77 39.559 ;
     RECT  2.415 38.777 15.354 39.631 ;
     RECT  16.092 39.559 22.77 39.631 ;
     RECT  2.415 39.631 22.77 40.171 ;
     RECT  23.508 39.293 62.37 40.171 ;
     RECT  2.415 40.171 62.37 40.369 ;
     RECT  2.415 40.369 62.406 40.405 ;
     RECT  2.376 40.405 62.406 40.703 ;
     RECT  9.468 40.703 62.406 41.279 ;
     RECT  2.376 40.703 8.694 41.369 ;
     RECT  2.415 41.369 8.694 41.449 ;
     RECT  9.468 41.279 22.842 41.449 ;
     RECT  2.415 41.449 22.842 42.025 ;
     RECT  23.58 41.279 62.406 42.025 ;
     RECT  2.415 42.025 62.406 42.755 ;
     RECT  2.415 42.755 42.03 42.989 ;
     RECT  42.768 42.755 62.406 42.989 ;
     RECT  36.144 42.989 42.03 43.531 ;
     RECT  42.768 42.989 62.37 43.531 ;
     RECT  2.415 42.989 35.37 43.723 ;
     RECT  36.144 43.531 62.37 43.723 ;
     RECT  2.415 43.723 62.37 43.799 ;
     RECT  2.415 43.799 62.262 43.835 ;
     RECT  2.415 43.835 62.154 44.455 ;
     RECT  2.34 44.455 62.154 44.761 ;
     RECT  2.34 44.761 62.262 45.571 ;
     RECT  2.34 45.571 62.442 45.959 ;
     RECT  2.34 45.959 62.097 46.397 ;
     RECT  2.34 46.397 59.346 47.183 ;
     RECT  60.156 46.397 62.097 47.191 ;
     RECT  2.415 47.183 59.346 47.275 ;
     RECT  60.084 47.191 62.097 47.275 ;
     RECT  0.144 47.857 0.162 48.235 ;
     RECT  2.415 47.275 62.097 48.427 ;
     RECT  2.34 48.427 62.097 48.467 ;
     RECT  0.108 48.235 0.162 48.937 ;
     RECT  2.376 48.467 62.097 49.351 ;
     RECT  2.376 49.351 62.514 49.469 ;
     RECT  0.108 48.937 0.234 49.477 ;
     RECT  0.108 49.477 0.27 49.549 ;
     RECT  2.376 49.469 62.097 49.855 ;
     RECT  0.108 49.549 0.306 50.347 ;
     RECT  2.304 49.855 62.097 50.459 ;
     RECT  0.108 50.347 0.378 50.477 ;
     RECT  0.108 50.477 0.306 50.669 ;
     RECT  2.304 50.459 61.038 50.693 ;
     RECT  0.108 50.669 0.162 50.957 ;
     RECT  61.02 50.693 61.038 51.205 ;
     RECT  61.815 50.459 62.097 51.205 ;
     RECT  2.304 50.693 60.246 51.307 ;
     RECT  0.108 50.957 0.126 51.437 ;
     RECT  2.268 51.307 60.246 51.475 ;
     RECT  2.268 51.475 60.282 51.511 ;
     RECT  61.02 51.205 62.097 51.511 ;
     RECT  2.268 51.511 62.097 51.691 ;
     RECT  2.232 51.691 62.097 52.321 ;
     RECT  2.232 52.321 62.514 52.445 ;
     RECT  2.232 52.445 62.442 52.547 ;
     RECT  2.304 52.547 62.442 53.671 ;
     RECT  0.144 53.329 0.162 53.797 ;
     RECT  0.144 53.797 0.198 53.869 ;
     RECT  0.108 53.869 0.198 54.989 ;
     RECT  2.304 53.671 62.622 55.021 ;
     RECT  2.268 55.021 62.622 55.409 ;
     RECT  0.144 54.989 0.198 55.483 ;
     RECT  0.144 55.483 0.27 55.661 ;
     RECT  2.268 55.409 47.682 55.751 ;
     RECT  0.144 55.661 0.198 55.915 ;
     RECT  2.268 55.751 47.646 56.203 ;
     RECT  0.108 55.915 0.198 56.255 ;
     RECT  48.456 55.409 62.622 56.399 ;
     RECT  2.232 56.203 47.646 56.525 ;
     RECT  2.304 56.525 47.646 56.569 ;
     RECT  48.456 56.399 53.082 56.569 ;
     RECT  63.9 55.561 63.918 56.641 ;
     RECT  63.9 56.641 64.026 56.731 ;
     RECT  63.9 56.731 64.062 56.911 ;
     RECT  2.304 56.569 53.082 57.181 ;
     RECT  53.82 56.399 62.622 57.181 ;
     RECT  63.864 56.911 64.062 57.181 ;
     RECT  0.144 56.255 0.162 57.259 ;
     RECT  0.144 57.259 0.378 57.389 ;
     RECT  2.304 57.181 62.622 57.451 ;
     RECT  63.864 57.181 64.674 57.541 ;
     RECT  0.144 57.389 0.342 57.835 ;
     RECT  0.108 57.835 0.342 57.869 ;
     RECT  1.152 57.739 1.17 57.917 ;
     RECT  2.196 57.451 62.622 57.947 ;
     RECT  0.108 57.869 0.126 57.965 ;
     RECT  2.304 57.947 62.622 57.991 ;
     RECT  63.864 57.541 64.71 58.411 ;
     RECT  63.792 58.411 64.71 58.541 ;
     RECT  63.864 58.541 64.71 58.637 ;
     RECT  2.304 57.991 62.694 58.685 ;
     RECT  2.304 58.685 47.646 59.027 ;
     RECT  48.456 58.685 62.694 59.213 ;
     RECT  14.76 59.027 47.646 59.467 ;
     RECT  63.864 58.637 64.674 59.563 ;
     RECT  14.76 59.467 47.718 59.701 ;
     RECT  48.456 59.213 62.514 59.701 ;
     RECT  63.828 59.563 64.674 59.755 ;
     RECT  2.304 59.027 14.022 59.765 ;
     RECT  2.34 59.765 14.022 59.971 ;
     RECT  14.76 59.701 62.514 59.971 ;
     RECT  63.828 59.755 64.71 60.115 ;
     RECT  2.34 59.971 62.514 60.179 ;
     RECT  2.34 60.179 39.294 60.269 ;
     RECT  63.252 60.115 64.71 60.269 ;
     RECT  40.068 60.179 62.514 60.305 ;
     RECT  50.4 60.305 62.514 60.349 ;
     RECT  63.288 60.269 64.71 60.449 ;
     RECT  2.34 60.269 39.258 60.953 ;
     RECT  2.415 60.953 39.258 61.003 ;
     RECT  40.068 60.305 49.59 61.003 ;
     RECT  63.288 60.449 64.674 61.195 ;
     RECT  50.4 60.349 62.55 61.231 ;
     RECT  63.288 61.195 64.71 61.231 ;
     RECT  2.415 61.003 49.59 61.385 ;
     RECT  3.42 61.385 49.59 61.771 ;
     RECT  50.4 61.231 64.71 61.771 ;
     RECT  3.42 61.771 64.71 61.925 ;
     RECT  3.528 61.925 48.438 62.045 ;
     RECT  11.088 62.045 48.438 62.093 ;
     RECT  49.176 61.925 64.71 62.141 ;
     RECT  3.528 62.045 10.314 62.159 ;
     RECT  11.088 62.093 35.097 62.159 ;
     RECT  36.504 62.093 48.438 62.159 ;
     RECT  7.632 62.159 8.73 62.195 ;
     RECT  49.176 62.141 52.002 62.195 ;
     RECT  7.815 62.195 8.73 62.231 ;
     RECT  52.776 62.141 64.71 62.231 ;
     RECT  11.736 62.159 30.114 62.267 ;
     RECT  51.012 62.195 52.002 62.267 ;
     RECT  9.468 62.159 10.17 62.303 ;
     RECT  31.32 62.159 35.097 62.303 ;
     RECT  36.504 62.159 48.402 62.303 ;
     RECT  49.176 62.195 50.166 62.303 ;
     RECT  51.015 62.267 51.966 62.303 ;
     RECT  52.776 62.231 64.062 62.303 ;
     RECT  9.504 62.303 10.17 62.339 ;
     RECT  36.504 62.303 43.074 62.339 ;
     RECT  2.415 61.385 2.697 62.387 ;
     RECT  7.815 62.231 8.097 62.387 ;
     RECT  31.86 62.303 35.097 62.387 ;
     RECT  9.504 62.339 10.026 62.429 ;
     RECT  11.736 62.267 16.29 62.429 ;
     RECT  17.064 62.267 30.114 62.429 ;
     RECT  31.86 62.387 34.905 62.429 ;
     RECT  36.612 62.339 39.294 62.429 ;
     RECT  40.215 62.339 43.074 62.429 ;
     RECT  43.884 62.303 48.402 62.429 ;
     RECT  50.04 62.303 50.166 62.429 ;
     RECT  51.015 62.303 51.894 62.429 ;
     RECT  53.1 62.303 64.062 62.429 ;
     RECT  21.024 62.429 27.018 62.435 ;
     RECT  41.796 62.429 42.75 62.435 ;
     RECT  3.528 62.159 6.822 62.465 ;
     RECT  9.72 62.429 10.026 62.465 ;
     RECT  12.672 62.429 13.878 62.465 ;
     RECT  14.724 62.429 16.29 62.465 ;
     RECT  18.36 62.429 20.286 62.465 ;
     RECT  21.024 62.435 25.146 62.465 ;
     RECT  32.148 62.429 34.905 62.465 ;
     RECT  43.884 62.429 44.838 62.465 ;
     RECT  45.615 62.429 48.402 62.465 ;
     RECT  25.884 62.435 27.018 62.477 ;
     RECT  42.012 62.435 42.75 62.477 ;
     RECT  43.884 62.465 44.046 62.477 ;
     RECT  47.7 62.465 48.402 62.477 ;
     RECT  5.256 62.465 6.678 62.501 ;
     RECT  12.744 62.465 13.305 62.501 ;
     RECT  14.76 62.465 14.778 62.501 ;
     RECT  17.064 62.429 17.478 62.501 ;
     RECT  18.36 62.465 18.705 62.501 ;
     RECT  19.512 62.465 20.286 62.501 ;
     RECT  21.888 62.465 25.146 62.501 ;
     RECT  25.956 62.477 27.018 62.501 ;
     RECT  28.044 62.429 30.114 62.501 ;
     RECT  36.612 62.429 37.674 62.501 ;
     RECT  38.484 62.429 39.294 62.501 ;
     RECT  42.372 62.477 42.75 62.501 ;
     RECT  44.82 62.465 44.838 62.501 ;
     RECT  47.736 62.477 48.402 62.501 ;
     RECT  53.136 62.429 56.505 62.501 ;
     RECT  3.636 62.465 4.446 62.537 ;
     RECT  5.256 62.501 5.706 62.537 ;
     RECT  9.972 62.465 9.99 62.537 ;
     RECT  19.908 62.501 20.034 62.537 ;
     RECT  21.024 62.465 21.042 62.537 ;
     RECT  28.044 62.501 29.79 62.537 ;
     RECT  32.148 62.465 32.166 62.537 ;
     RECT  33.228 62.465 34.905 62.537 ;
     RECT  43.992 62.477 44.046 62.537 ;
     RECT  59.22 62.429 64.062 62.537 ;
     RECT  28.728 62.537 29.79 62.573 ;
     RECT  33.264 62.537 34.905 62.573 ;
     RECT  54.432 62.501 56.505 62.573 ;
     RECT  57.708 62.429 58.122 62.573 ;
     RECT  59.22 62.537 60.03 62.573 ;
     RECT  3.636 62.537 3.654 62.609 ;
     RECT  4.428 62.537 4.446 62.609 ;
     RECT  5.688 62.537 5.706 62.609 ;
     RECT  6.66 62.501 6.678 62.609 ;
     RECT  7.815 62.387 8.01 62.609 ;
     RECT  15.624 62.465 16.074 62.609 ;
     RECT  21.888 62.501 22.41 62.609 ;
     RECT  26.748 62.501 26.982 62.609 ;
     RECT  28.728 62.573 29.505 62.609 ;
     RECT  33.408 62.573 34.905 62.609 ;
     RECT  36.612 62.501 37.638 62.609 ;
     RECT  40.215 62.429 40.878 62.609 ;
     RECT  42.372 62.501 42.39 62.609 ;
     RECT  53.532 62.501 53.55 62.609 ;
     RECT  54.432 62.573 54.45 62.609 ;
     RECT  55.548 62.573 56.505 62.609 ;
     RECT  58.104 62.573 58.122 62.609 ;
     RECT  21.888 62.609 21.906 62.621 ;
     RECT  23.292 62.501 24.105 62.621 ;
     RECT  34.056 62.609 34.905 62.621 ;
     RECT  38.592 62.501 39.294 62.621 ;
     RECT  2.415 62.387 2.505 62.657 ;
     RECT  7.815 62.609 7.905 62.657 ;
     RECT  13.215 62.501 13.305 62.657 ;
     RECT  18.615 62.501 18.705 62.657 ;
     RECT  23.976 62.621 24.105 62.657 ;
     RECT  29.415 62.609 29.505 62.657 ;
     RECT  34.815 62.621 34.905 62.657 ;
     RECT  40.215 62.609 40.305 62.657 ;
     RECT  45.615 62.465 46.89 62.657 ;
     RECT  51.015 62.429 51.105 62.657 ;
     RECT  56.415 62.609 56.505 62.657 ;
     RECT  61.056 62.537 64.062 62.657 ;
     RECT  46.224 62.657 46.89 62.669 ;
     RECT  62.604 62.657 64.062 62.669 ;
     RECT  15.624 62.609 15.642 62.699 ;
     RECT  19.944 62.537 20.034 62.699 ;
     RECT  25.056 62.501 25.146 62.699 ;
     RECT  25.956 62.501 25.974 62.699 ;
     RECT  26.784 62.609 26.982 62.699 ;
     RECT  37.62 62.609 37.638 62.699 ;
     RECT  39.204 62.621 39.294 62.699 ;
     RECT  46.224 62.669 46.314 62.699 ;
     RECT  48.384 62.501 48.402 62.699 ;
     RECT  55.548 62.609 55.566 62.699 ;
     RECT  59.22 62.573 59.31 62.699 ;
     RECT  61.056 62.657 61.218 62.699 ;
     RECT  62.604 62.669 62.694 62.699 ;
     RECT  23.976 62.657 23.994 62.771 ;
     RECT  25.128 62.699 25.146 62.771 ;
     RECT  63.756 62.669 64.062 63.053 ;
     RECT  63.9 63.053 64.062 63.149 ;
     RECT  63.936 63.149 64.062 63.245 ;
     RECT  64.044 63.245 64.062 63.341 ;
    LAYER M4 ;
     RECT  0.06 54.864 0.097 57.864 ;
     RECT  0.06 49.488 2.329 51.72 ;
     RECT  2.293 59.28 2.329 59.304 ;
     RECT  2.329 49.488 2.365 51.768 ;
     RECT  2.329 59.28 2.401 59.592 ;
     RECT  2.401 27.168 2.408 27.192 ;
     RECT  0.181 32.784 2.408 32.808 ;
     RECT  2.329 48.432 2.408 48.456 ;
     RECT  2.365 49.488 2.408 52.056 ;
     RECT  0.097 54.864 2.408 57.96 ;
     RECT  2.401 59.28 2.408 60.024 ;
     RECT  2.408 2.148 2.512 62.652 ;
     RECT  2.512 2.418 2.704 62.382 ;
     RECT  2.704 54.288 2.837 60.36 ;
     RECT  2.704 7.2 3.011 8.568 ;
     RECT  2.704 48.432 3.089 53.256 ;
     RECT  2.837 58.128 3.089 60.36 ;
     RECT  3.011 7.968 3.197 8.568 ;
     RECT  2.704 25.344 3.197 29.208 ;
     RECT  2.704 23.904 3.244 24.216 ;
     RECT  2.704 10.608 3.269 11.832 ;
     RECT  3.197 26.64 3.269 29.208 ;
     RECT  3.269 11.232 3.443 11.832 ;
     RECT  2.704 31.536 3.443 32.808 ;
     RECT  3.089 58.128 3.449 59.592 ;
     RECT  2.704 38.544 3.485 39.048 ;
     RECT  2.704 40.608 3.557 41.4 ;
     RECT  2.704 34.176 3.629 36.312 ;
     RECT  3.629 36 3.665 36.312 ;
     RECT  3.449 58.128 3.701 59.448 ;
     RECT  2.704 37.44 3.737 37.464 ;
     RECT  2.837 54.288 3.737 56.904 ;
     RECT  2.704 61.392 3.781 61.416 ;
     RECT  3.701 58.128 3.805 59.064 ;
     RECT  3.781 61.392 3.868 62.28 ;
     RECT  2.704 30.432 3.877 30.456 ;
     RECT  2.704 13.056 3.913 15.624 ;
     RECT  3.197 8.544 3.953 8.568 ;
     RECT  3.913 13.056 3.971 16.728 ;
     RECT  3.805 57.312 3.989 59.064 ;
     RECT  2.704 46.56 4.025 46.584 ;
     RECT  3.868 61.392 4.057 62.136 ;
     RECT  3.244 24.192 4.117 24.216 ;
     RECT  3.197 25.344 4.117 25.368 ;
     RECT  2.704 20.736 4.133 20.76 ;
     RECT  3.985 22.752 4.169 22.776 ;
     RECT  4.117 24.192 4.201 25.368 ;
     RECT  3.269 26.64 4.201 28.44 ;
     RECT  4.201 24.192 4.204 28.44 ;
     RECT  3.737 54.288 4.205 55.992 ;
     RECT  4.204 24.192 4.237 24.216 ;
     RECT  3.089 48.432 4.309 49.896 ;
     RECT  3.971 15.6 4.349 16.728 ;
     RECT  4.309 48.288 4.381 49.896 ;
     RECT  3.089 51.216 4.381 53.256 ;
     RECT  4.381 48.288 4.385 53.256 ;
     RECT  4.205 54.288 4.385 55.8 ;
     RECT  3.443 11.232 4.453 11.4 ;
     RECT  2.704 18.432 4.453 19.368 ;
     RECT  4.385 50.496 4.489 53.256 ;
     RECT  4.385 54.288 4.489 54.696 ;
     RECT  4.453 18.432 4.529 20.568 ;
     RECT  4.489 50.496 4.547 54.696 ;
     RECT  3.485 38.544 4.561 38.808 ;
     RECT  4.547 50.496 4.573 54.312 ;
     RECT  4.573 50.496 4.588 53.256 ;
     RECT  4.453 11.088 4.633 11.4 ;
     RECT  3.557 40.656 4.669 41.4 ;
     RECT  3.971 13.056 4.673 14.472 ;
     RECT  4.237 23.328 4.673 24.216 ;
     RECT  2.704 44.208 4.7 44.232 ;
     RECT  3.913 45.36 4.7 45.384 ;
     RECT  4.349 15.936 4.705 16.728 ;
     RECT  4.561 38.112 4.705 38.808 ;
     RECT  4.669 40.656 4.705 41.976 ;
     RECT  4.588 53.04 4.709 53.256 ;
     RECT  4.705 38.112 4.777 41.976 ;
     RECT  4.7 44.208 4.787 45.384 ;
     RECT  4.204 25.344 4.849 28.44 ;
     RECT  4.633 10.992 4.885 11.4 ;
     RECT  3.989 57.552 4.885 59.064 ;
     RECT  4.787 45.36 4.889 45.384 ;
     RECT  4.273 9.552 4.921 9.576 ;
     RECT  4.057 60.912 4.933 62.136 ;
     RECT  4.933 60.72 4.957 62.136 ;
     RECT  4.957 60.144 4.979 62.136 ;
     RECT  3.877 30.192 4.993 30.456 ;
     RECT  3.443 31.536 4.993 31.56 ;
     RECT  3.629 34.176 4.993 34.968 ;
     RECT  3.665 36 4.993 36.024 ;
     RECT  4.705 15.936 4.997 17.496 ;
     RECT  4.709 53.04 5.033 53.064 ;
     RECT  4.993 34.176 5.036 36.024 ;
     RECT  4.921 9.072 5.069 9.576 ;
     RECT  4.787 44.208 5.069 44.232 ;
     RECT  4.885 10.992 5.077 12.024 ;
     RECT  3.443 32.784 5.077 32.808 ;
     RECT  5.036 34.08 5.077 36.024 ;
     RECT  4.921 6.864 5.101 6.888 ;
     RECT  4.777 38.112 5.101 42.792 ;
     RECT  5.069 9.072 5.123 9.096 ;
     RECT  5.077 32.784 5.141 36.024 ;
     RECT  5.101 38.112 5.141 42.84 ;
     RECT  5.141 32.784 5.164 33.768 ;
     RECT  4.673 13.056 5.213 14.424 ;
     RECT  4.979 60.144 5.213 60.936 ;
     RECT  5.141 38.112 5.249 41.64 ;
     RECT  4.957 22.128 5.317 22.152 ;
     RECT  4.849 25.344 5.317 29.064 ;
     RECT  4.885 57.552 5.353 59.16 ;
     RECT  5.213 13.824 5.357 14.424 ;
     RECT  4.673 23.328 5.357 23.832 ;
     RECT  4.529 18.672 5.389 20.568 ;
     RECT  5.389 18.672 5.393 20.856 ;
     RECT  5.101 6.864 5.425 7.416 ;
     RECT  5.393 20.544 5.425 20.856 ;
     RECT  5.141 34.896 5.425 36.024 ;
     RECT  4.588 50.496 5.425 52.056 ;
     RECT  5.425 20.544 5.429 21.096 ;
     RECT  5.425 34.896 5.461 36.6 ;
     RECT  5.077 10.56 5.509 12.024 ;
     RECT  5.141 42.768 5.573 42.84 ;
     RECT  5.509 10.56 5.596 12.744 ;
     RECT  5.317 22.128 5.605 22.248 ;
     RECT  4.993 30.192 5.605 31.56 ;
     RECT  5.164 32.784 5.605 33 ;
     RECT  4.385 48.288 5.605 49.032 ;
     RECT  5.425 50.16 5.605 52.056 ;
     RECT  4.385 55.776 5.609 55.8 ;
     RECT  5.137 45.552 5.641 45.624 ;
     RECT  5.281 46.848 5.641 46.872 ;
     RECT  5.429 20.832 5.677 21.096 ;
     RECT  5.605 22.128 5.677 23.208 ;
     RECT  5.677 20.832 5.699 23.208 ;
     RECT  5.605 48.288 5.713 52.056 ;
     RECT  4.997 17.472 5.717 17.496 ;
     RECT  5.708 3.504 5.749 3.528 ;
     RECT  4.741 5.616 5.749 5.64 ;
     RECT  4.979 62.112 5.753 62.136 ;
     RECT  5.249 38.16 5.789 41.64 ;
     RECT  5.573 42.768 5.789 42.792 ;
     RECT  5.749 2.832 5.795 3.528 ;
     RECT  5.353 57.408 5.797 59.16 ;
     RECT  5.213 60.144 5.797 60.168 ;
     RECT  5.641 45.552 5.821 46.92 ;
     RECT  5.713 48.24 5.821 52.056 ;
     RECT  5.797 57.408 5.843 60.168 ;
     RECT  5.317 25.056 5.857 29.064 ;
     RECT  5.821 45.552 5.861 52.056 ;
     RECT  5.393 18.672 5.897 19.416 ;
     RECT  5.789 38.16 5.897 40.104 ;
     RECT  5.857 25.008 5.929 29.064 ;
     RECT  5.605 30.192 5.929 33 ;
     RECT  5.861 45.552 5.969 51.384 ;
     RECT  5.969 46.752 5.987 50.52 ;
     RECT  5.749 5.616 6.001 5.736 ;
     RECT  5.425 6.864 6.001 8.232 ;
     RECT  5.843 59.136 6.005 60.168 ;
     RECT  6.001 5.616 6.041 8.232 ;
     RECT  5.461 34.896 6.041 37.032 ;
     RECT  5.941 52.416 6.073 52.44 ;
     RECT  5.897 18.672 6.133 18.696 ;
     RECT  5.987 46.752 6.149 50.376 ;
     RECT  6.041 34.896 6.185 36.6 ;
     RECT  4.573 54.288 6.216 54.312 ;
     RECT  6.133 18.048 6.22 18.696 ;
     RECT  6.22 18.672 6.257 18.696 ;
     RECT  5.701 56.112 6.285 56.136 ;
     RECT  6.216 54.288 6.289 54.696 ;
     RECT  6.073 52.416 6.323 52.872 ;
     RECT  4.997 15.936 6.325 16.008 ;
     RECT  5.929 25.008 6.329 33 ;
     RECT  5.699 20.832 6.401 22.152 ;
     RECT  6.401 20.928 6.419 22.152 ;
     RECT  6.289 54.288 6.433 55.08 ;
     RECT  5.843 57.408 6.505 57.576 ;
     RECT  6.433 53.472 6.509 55.08 ;
     RECT  5.596 10.56 6.517 12.024 ;
     RECT  5.699 23.184 6.577 23.208 ;
     RECT  6.041 6.144 6.613 8.232 ;
     RECT  6.577 23.184 6.613 23.784 ;
     RECT  6.329 25.008 6.613 28.824 ;
     RECT  6.613 23.184 6.653 28.824 ;
     RECT  6.509 54.672 6.653 55.08 ;
     RECT  6.517 10.08 6.685 12.024 ;
     RECT  6.329 29.808 6.689 33 ;
     RECT  6.577 43.728 6.721 43.752 ;
     RECT  6.689 31.296 6.761 33 ;
     RECT  6.613 6.144 6.769 8.328 ;
     RECT  6.685 10.08 6.793 12.264 ;
     RECT  6.721 43.728 6.793 44.232 ;
     RECT  5.795 2.832 6.797 2.856 ;
     RECT  6.685 4.8 6.797 4.824 ;
     RECT  5.789 41.616 6.805 41.64 ;
     RECT  6.793 10.08 6.829 12.312 ;
     RECT  6.793 43.344 6.829 44.232 ;
     RECT  6.253 61.92 6.829 61.944 ;
     RECT  6.653 23.184 6.833 28.296 ;
     RECT  6.509 53.472 6.833 53.496 ;
     RECT  6.833 23.184 6.865 25.032 ;
     RECT  6.505 57.312 6.865 57.576 ;
     RECT  6.005 59.136 6.865 59.304 ;
     RECT  6.325 15.696 6.901 16.872 ;
     RECT  5.897 38.64 6.901 40.104 ;
     RECT  6.805 41.088 6.901 41.64 ;
     RECT  6.323 52.416 6.937 52.44 ;
     RECT  6.937 18.768 7.009 18.792 ;
     RECT  6.433 19.824 7.009 19.848 ;
     RECT  6.901 38.64 7.045 41.64 ;
     RECT  6.829 9.984 7.117 12.312 ;
     RECT  5.969 45.552 7.225 45.672 ;
     RECT  6.149 46.848 7.225 50.376 ;
     RECT  7.045 37.968 7.297 41.64 ;
     RECT  6.829 43.344 7.297 44.376 ;
     RECT  7.225 45.552 7.297 50.376 ;
     RECT  6.865 57.312 7.333 59.304 ;
     RECT  6.829 61.152 7.333 61.944 ;
     RECT  6.769 7.392 7.429 8.328 ;
     RECT  7.117 9.792 7.429 12.312 ;
     RECT  7.333 57.312 7.429 61.944 ;
     RECT  6.937 51.648 7.549 52.44 ;
     RECT  7.297 37.632 7.765 41.64 ;
     RECT  7.429 7.392 7.801 12.312 ;
     RECT  6.769 6.144 7.808 6.168 ;
     RECT  7.801 7.2 7.808 12.312 ;
     RECT  5.357 13.824 7.808 13.848 ;
     RECT  6.901 15.696 7.808 17.688 ;
     RECT  7.009 18.768 7.808 19.848 ;
     RECT  6.419 20.928 7.808 21.432 ;
     RECT  6.865 22.752 7.808 25.032 ;
     RECT  6.833 26.352 7.808 28.296 ;
     RECT  6.689 29.808 7.808 30.168 ;
     RECT  6.761 31.872 7.808 33 ;
     RECT  6.185 34.896 7.808 35.736 ;
     RECT  7.765 36.912 7.808 41.64 ;
     RECT  7.297 43.344 7.808 50.376 ;
     RECT  7.549 51.456 7.808 52.44 ;
     RECT  6.653 54.672 7.808 54.696 ;
     RECT  7.429 57.312 7.808 62.184 ;
     RECT  7.808 2.148 7.912 62.652 ;
     RECT  7.912 2.418 8.104 62.382 ;
     RECT  8.104 49.488 8.165 52.776 ;
     RECT  8.104 54.432 8.201 54.696 ;
     RECT  8.104 36.912 8.281 42.6 ;
     RECT  8.104 43.584 8.309 48.408 ;
     RECT  8.104 34.704 8.381 35.832 ;
     RECT  8.281 41.616 8.417 42.6 ;
     RECT  8.104 57.408 8.489 59.256 ;
     RECT  8.104 15.456 8.669 15.48 ;
     RECT  8.309 47.856 8.669 48.408 ;
     RECT  8.104 6.816 8.741 12.552 ;
     RECT  8.309 43.584 8.741 46.872 ;
     RECT  8.281 36.912 8.849 40.632 ;
     RECT  8.489 57.408 8.849 58.296 ;
     RECT  8.104 18.768 8.867 23.304 ;
     RECT  8.104 17.136 8.921 17.736 ;
     RECT  8.104 29.664 8.957 30.744 ;
     RECT  8.104 24.384 9.097 25.032 ;
     RECT  8.104 26.064 9.097 28.296 ;
     RECT  8.104 2.64 9.109 3.144 ;
     RECT  8.104 4.128 9.109 4.392 ;
     RECT  8.849 57.408 9.133 57.96 ;
     RECT  8.741 9.6 9.145 12.552 ;
     RECT  9.145 11.376 9.169 12.552 ;
     RECT  8.104 13.824 9.169 14.376 ;
     RECT  9.097 24.384 9.169 28.296 ;
     RECT  8.669 48.384 9.169 48.408 ;
     RECT  8.165 49.488 9.169 52.44 ;
     RECT  8.957 30.192 9.173 30.744 ;
     RECT  9.109 2.64 9.196 4.392 ;
     RECT  9.133 57.12 9.205 57.96 ;
     RECT  8.741 6.816 9.209 8.568 ;
     RECT  8.741 43.584 9.241 46.008 ;
     RECT  9.145 9.6 9.273 10.392 ;
     RECT  8.104 61.104 9.281 62.04 ;
     RECT  8.867 19.536 9.301 23.304 ;
     RECT  9.169 24.384 9.301 28.968 ;
     RECT  9.205 56.448 9.347 57.96 ;
     RECT  9.209 8.544 9.353 8.568 ;
     RECT  9.209 6.816 9.388 7.224 ;
     RECT  9.169 11.376 9.389 14.376 ;
     RECT  9.301 19.536 9.425 28.968 ;
     RECT  8.381 34.704 9.425 35.736 ;
     RECT  9.281 61.2 9.497 62.04 ;
     RECT  9.241 43.344 9.565 46.008 ;
     RECT  9.425 19.536 9.569 26.664 ;
     RECT  9.569 23.28 9.577 26.664 ;
     RECT  9.389 11.376 9.605 11.4 ;
     RECT  9.196 4.128 9.637 4.392 ;
     RECT  8.104 5.472 9.637 5.784 ;
     RECT  9.565 15.84 9.637 15.864 ;
     RECT  9.169 48.384 9.637 52.44 ;
     RECT  8.104 32.304 9.641 33.576 ;
     RECT  9.425 35.712 9.673 35.736 ;
     RECT  8.849 36.912 9.673 40.104 ;
     RECT  8.921 17.424 9.745 17.736 ;
     RECT  9.389 12.528 9.785 14.376 ;
     RECT  9.577 25.008 9.785 26.664 ;
     RECT  9.637 4.128 9.788 5.784 ;
     RECT  9.388 6.816 9.788 6.84 ;
     RECT  9.569 19.536 9.829 22.104 ;
     RECT  9.347 57.12 9.829 57.96 ;
     RECT  9.529 59.616 9.829 59.64 ;
     RECT  9.173 30.432 9.836 30.744 ;
     RECT  9.641 32.304 9.836 33.384 ;
     RECT  9.829 19.104 9.857 22.104 ;
     RECT  9.788 4.128 9.875 6.84 ;
     RECT  9.857 19.104 9.875 19.944 ;
     RECT  9.785 12.576 9.877 14.376 ;
     RECT  9.637 15.504 9.877 15.864 ;
     RECT  9.637 48.096 9.889 52.44 ;
     RECT  8.201 54.432 9.889 54.456 ;
     RECT  9.875 4.128 9.893 5.592 ;
     RECT  9.875 19.104 9.916 19.896 ;
     RECT  9.829 57.12 9.916 59.64 ;
     RECT  9.836 30.432 9.923 33.384 ;
     RECT  9.565 43.104 9.925 46.008 ;
     RECT  9.273 9.6 9.929 10.104 ;
     RECT  9.785 25.056 9.929 26.664 ;
     RECT  9.925 42.96 9.961 46.008 ;
     RECT  9.889 54.432 9.961 54.696 ;
     RECT  9.196 2.64 9.997 3.144 ;
     RECT  9.916 19.488 10.001 19.896 ;
     RECT  9.923 31.536 10.001 33.384 ;
     RECT  9.673 35.712 10.033 40.104 ;
     RECT  9.961 42.96 10.033 46.824 ;
     RECT  9.893 5.52 10.109 5.592 ;
     RECT  9.497 62.016 10.141 62.04 ;
     RECT  9.857 20.928 10.145 22.104 ;
     RECT  10.033 35.712 10.177 40.392 ;
     RECT  9.425 27.744 10.213 28.968 ;
     RECT  9.916 59.616 10.289 59.64 ;
     RECT  9.875 6.816 10.325 6.84 ;
     RECT  9.577 23.28 10.325 23.928 ;
     RECT  10.141 62.016 10.397 62.328 ;
     RECT  9.929 25.104 10.429 26.664 ;
     RECT  10.213 27.744 10.429 29.016 ;
     RECT  10.145 21.072 10.537 22.104 ;
     RECT  10.325 23.28 10.537 23.304 ;
     RECT  9.889 48.096 10.537 52.872 ;
     RECT  9.877 12.576 10.541 15.864 ;
     RECT  10.537 48.096 10.645 52.92 ;
     RECT  9.425 34.704 10.649 34.728 ;
     RECT  10.033 42.768 10.685 46.824 ;
     RECT  10.177 35.712 10.717 40.488 ;
     RECT  10.133 55.872 10.717 55.896 ;
     RECT  9.916 57.12 10.717 57.96 ;
     RECT  9.961 54.048 10.721 54.696 ;
     RECT  10.541 13.584 10.753 15.864 ;
     RECT  10.685 44.736 10.789 46.824 ;
     RECT  10.645 48.048 10.789 52.92 ;
     RECT  10.001 19.488 10.793 19.848 ;
     RECT  10.753 13.584 10.825 16.2 ;
     RECT  10.789 44.736 10.865 52.92 ;
     RECT  10.429 25.104 10.933 29.016 ;
     RECT  10.717 34.848 10.973 40.488 ;
     RECT  10.109 5.568 11.005 5.592 ;
     RECT  9.997 2.304 11.045 3.144 ;
     RECT  10.541 12.576 11.077 12.6 ;
     RECT  9.745 17.424 11.081 17.784 ;
     RECT  10.973 38.16 11.081 40.488 ;
     RECT  8.417 41.616 11.113 41.64 ;
     RECT  10.685 42.768 11.113 43.464 ;
     RECT  10.721 54.336 11.113 54.696 ;
     RECT  10.717 55.872 11.113 57.96 ;
     RECT  10.825 13.584 11.149 16.344 ;
     RECT  11.081 17.424 11.149 17.448 ;
     RECT  10.537 21.072 11.149 23.304 ;
     RECT  9.893 4.128 11.173 4.296 ;
     RECT  11.005 5.568 11.173 6.024 ;
     RECT  11.081 39.408 11.185 40.488 ;
     RECT  11.113 41.616 11.185 43.464 ;
     RECT  11.185 39.408 11.189 43.464 ;
     RECT  11.041 60.768 11.293 60.792 ;
     RECT  11.149 20.352 11.297 23.304 ;
     RECT  11.045 2.784 11.365 3.144 ;
     RECT  11.173 4.128 11.365 6.024 ;
     RECT  11.293 11.376 11.437 11.4 ;
     RECT  10.933 24.528 11.477 29.016 ;
     RECT  11.149 13.584 11.513 17.448 ;
     RECT  11.365 2.784 11.549 6.024 ;
     RECT  11.297 20.352 11.621 22.584 ;
     RECT  9.929 9.6 11.653 9.672 ;
     RECT  10.001 31.536 11.653 33 ;
     RECT  10.973 34.848 11.653 37.032 ;
     RECT  11.077 12.48 11.66 12.6 ;
     RECT  11.513 13.584 11.66 16.44 ;
     RECT  11.113 54.336 11.689 57.96 ;
     RECT  11.477 24.912 11.729 29.016 ;
     RECT  9.923 30.432 11.729 30.456 ;
     RECT  11.66 12.48 11.747 16.44 ;
     RECT  11.189 39.456 11.801 43.464 ;
     RECT  11.653 9.6 11.833 9.96 ;
     RECT  11.437 11.376 11.833 11.448 ;
     RECT  10.865 44.784 11.833 52.92 ;
     RECT  11.747 13.584 11.837 16.44 ;
     RECT  11.729 26.352 11.837 29.016 ;
     RECT  11.833 44.688 12.013 52.92 ;
     RECT  11.747 12.48 12.017 12.504 ;
     RECT  11.653 31.536 12.017 37.032 ;
     RECT  11.513 17.424 12.049 17.448 ;
     RECT  11.689 18.96 12.049 18.984 ;
     RECT  11.837 13.632 12.089 16.44 ;
     RECT  12.013 44.64 12.229 52.92 ;
     RECT  11.653 59.28 12.229 59.304 ;
     RECT  11.293 60.432 12.229 60.792 ;
     RECT  12.017 31.632 12.233 37.032 ;
     RECT  12.229 59.28 12.325 60.792 ;
     RECT  11.149 7.776 12.337 7.8 ;
     RECT  12.325 59.28 12.337 60.984 ;
     RECT  10.397 62.304 12.337 62.328 ;
     RECT  12.337 7.44 12.409 7.8 ;
     RECT  12.337 59.28 12.445 62.328 ;
     RECT  11.549 2.784 12.517 5.496 ;
     RECT  11.081 38.16 12.517 38.184 ;
     RECT  11.689 54.336 12.517 58.008 ;
     RECT  11.837 28.848 12.553 29.016 ;
     RECT  12.517 54.192 12.625 58.008 ;
     RECT  12.445 59.28 12.625 62.424 ;
     RECT  11.621 20.352 12.661 22.536 ;
     RECT  11.833 9.6 12.697 11.448 ;
     RECT  12.517 2.496 12.733 5.496 ;
     RECT  12.409 6.624 12.733 7.8 ;
     RECT  12.553 28.848 12.769 29.304 ;
     RECT  12.049 17.424 12.805 18.984 ;
     RECT  12.661 20.352 12.805 22.824 ;
     RECT  12.233 35.712 12.913 37.032 ;
     RECT  12.517 38.16 12.913 38.28 ;
     RECT  12.229 44.448 12.949 52.92 ;
     RECT  12.233 31.632 12.985 34.44 ;
     RECT  12.697 9.6 13.093 11.976 ;
     RECT  12.089 13.824 13.093 16.44 ;
     RECT  12.625 54.192 13.165 62.424 ;
     RECT  12.733 2.496 13.208 7.8 ;
     RECT  13.093 9.6 13.208 16.44 ;
     RECT  12.805 17.424 13.208 22.824 ;
     RECT  11.689 23.808 13.208 23.832 ;
     RECT  11.729 24.912 13.208 25.176 ;
     RECT  11.837 26.352 13.208 27.192 ;
     RECT  12.769 28.848 13.208 29.544 ;
     RECT  12.985 31.392 13.208 34.44 ;
     RECT  12.913 35.712 13.208 38.28 ;
     RECT  11.801 39.456 13.208 43.08 ;
     RECT  12.949 44.448 13.208 53.016 ;
     RECT  13.165 54.144 13.208 62.424 ;
     RECT  13.208 2.148 13.312 62.652 ;
     RECT  13.312 2.418 13.504 62.382 ;
     RECT  13.504 42.864 13.565 58.728 ;
     RECT  13.504 2.496 13.601 4.776 ;
     RECT  13.504 59.856 13.619 61.656 ;
     RECT  13.619 59.952 13.637 61.656 ;
     RECT  13.504 28.704 13.709 36.552 ;
     RECT  13.504 5.856 13.745 11.448 ;
     RECT  13.504 12.528 13.817 17.64 ;
     RECT  13.709 28.704 13.859 35.832 ;
     RECT  13.859 30.768 13.925 35.832 ;
     RECT  13.925 30.768 13.997 34.392 ;
     RECT  13.817 12.528 14.177 13.848 ;
     RECT  13.745 5.856 14.285 11.256 ;
     RECT  13.925 35.376 14.465 35.832 ;
     RECT  13.504 39.168 14.497 39.192 ;
     RECT  13.504 40.608 14.497 40.632 ;
     RECT  13.504 26.256 14.533 27.384 ;
     RECT  13.859 28.704 14.533 29.304 ;
     RECT  13.504 23.808 14.573 25.176 ;
     RECT  13.637 60 14.675 61.656 ;
     RECT  13.601 2.736 14.677 4.776 ;
     RECT  14.285 5.856 14.677 6.264 ;
     RECT  13.504 20.496 14.713 22.824 ;
     RECT  13.504 41.712 14.821 41.736 ;
     RECT  13.565 42.864 14.821 58.44 ;
     RECT  13.504 37.872 14.857 38.184 ;
     RECT  14.497 39.168 14.857 40.632 ;
     RECT  14.821 41.712 14.857 58.44 ;
     RECT  14.675 60 14.857 60.936 ;
     RECT  13.817 14.832 14.917 17.64 ;
     RECT  14.876 18.912 14.917 18.936 ;
     RECT  14.713 20.064 14.929 22.824 ;
     RECT  14.917 14.832 14.963 18.936 ;
     RECT  14.285 7.44 14.965 11.256 ;
     RECT  14.177 12.528 14.965 12.552 ;
     RECT  14.965 7.44 14.969 12.552 ;
     RECT  14.963 14.832 15.004 18.792 ;
     RECT  14.857 37.872 15.037 40.632 ;
     RECT  14.857 41.712 15.037 60.936 ;
     RECT  15.037 37.872 15.073 60.936 ;
     RECT  15.073 37.536 15.113 60.936 ;
     RECT  14.929 19.968 15.217 22.824 ;
     RECT  14.573 23.808 15.217 23.832 ;
     RECT  14.465 35.712 15.289 35.832 ;
     RECT  14.857 61.968 15.293 62.136 ;
     RECT  14.533 26.256 15.329 29.304 ;
     RECT  14.677 2.736 15.349 6.264 ;
     RECT  14.573 24.96 15.349 25.176 ;
     RECT  15.329 26.256 15.349 28.536 ;
     RECT  15.349 24.96 15.395 28.536 ;
     RECT  15.356 29.568 15.443 29.592 ;
     RECT  14.969 7.968 15.469 12.552 ;
     RECT  14.177 13.824 15.469 13.848 ;
     RECT  15.349 2.688 15.509 6.264 ;
     RECT  15.509 4.416 15.589 6.264 ;
     RECT  15.589 4.416 15.635 6.84 ;
     RECT  15.113 37.536 15.649 60.696 ;
     RECT  15.509 2.688 15.653 3.384 ;
     RECT  15.469 7.968 15.683 13.848 ;
     RECT  15.649 37.248 15.683 60.696 ;
     RECT  15.683 37.248 15.689 38.712 ;
     RECT  15.635 4.56 15.697 6.84 ;
     RECT  13.997 31.344 15.865 34.392 ;
     RECT  15.289 35.712 15.865 35.928 ;
     RECT  15.395 25.152 15.869 28.536 ;
     RECT  15.217 19.968 15.937 23.832 ;
     RECT  15.683 10.992 15.973 13.848 ;
     RECT  15.004 14.832 15.973 17.448 ;
     RECT  15.004 18.768 15.973 18.792 ;
     RECT  15.865 31.344 15.973 35.928 ;
     RECT  15.973 30.96 16.013 35.928 ;
     RECT  16.013 35.76 16.049 35.928 ;
     RECT  15.973 10.992 16.081 18.792 ;
     RECT  16.049 35.808 16.121 35.928 ;
     RECT  15.689 38.496 16.121 38.712 ;
     RECT  15.683 39.744 16.157 60.696 ;
     RECT  16.081 10.992 16.193 18.84 ;
     RECT  15.683 7.968 16.333 9.96 ;
     RECT  16.013 30.96 16.355 34.632 ;
     RECT  15.869 25.152 16.373 28.44 ;
     RECT  16.121 35.856 16.481 35.928 ;
     RECT  16.157 39.744 16.499 59.016 ;
     RECT  16.193 13.824 16.547 18.84 ;
     RECT  15.937 19.968 16.621 23.928 ;
     RECT  16.157 60 16.801 60.696 ;
     RECT  15.293 61.968 16.801 61.992 ;
     RECT  15.653 2.688 16.949 2.712 ;
     RECT  16.499 39.744 17.021 39.768 ;
     RECT  16.373 25.152 17.077 25.176 ;
     RECT  16.621 19.872 17.089 23.928 ;
     RECT  17.089 19.392 17.173 23.928 ;
     RECT  17.077 25.056 17.173 25.176 ;
     RECT  16.481 35.856 17.201 35.88 ;
     RECT  16.373 26.16 17.221 28.44 ;
     RECT  16.193 10.992 17.233 12.84 ;
     RECT  16.547 13.824 17.233 18.216 ;
     RECT  16.355 31.392 17.233 34.632 ;
     RECT  15.689 37.248 17.233 37.272 ;
     RECT  17.017 30.288 17.267 30.312 ;
     RECT  16.121 38.496 17.305 38.664 ;
     RECT  16.499 40.848 17.305 59.016 ;
     RECT  16.801 60 17.305 61.992 ;
     RECT  15.697 4.56 17.345 6.264 ;
     RECT  17.233 36.912 17.413 37.272 ;
     RECT  17.305 38.496 17.413 39.288 ;
     RECT  17.305 40.848 17.413 61.992 ;
     RECT  17.413 36.912 17.459 39.288 ;
     RECT  17.233 10.992 17.489 18.216 ;
     RECT  16.333 7.632 17.521 9.96 ;
     RECT  17.489 10.992 17.521 15.336 ;
     RECT  17.413 40.848 17.521 62.424 ;
     RECT  17.173 19.392 17.593 25.176 ;
     RECT  17.221 26.16 17.593 29.208 ;
     RECT  17.489 16.32 17.701 18.216 ;
     RECT  17.593 19.392 17.701 29.208 ;
     RECT  17.521 40.8 17.749 62.424 ;
     RECT  17.521 7.632 17.797 15.336 ;
     RECT  17.345 4.56 17.809 5.016 ;
     RECT  17.797 7.248 17.809 15.336 ;
     RECT  17.701 16.32 17.893 29.208 ;
     RECT  17.893 16.32 18.241 30.024 ;
     RECT  17.459 37.872 18.277 39.288 ;
     RECT  17.749 40.56 18.277 62.424 ;
     RECT  18.241 16.32 18.385 30.168 ;
     RECT  17.233 31.392 18.385 35.352 ;
     RECT  17.809 4.176 18.529 5.016 ;
     RECT  18.385 16.32 18.565 35.352 ;
     RECT  18.241 36.432 18.565 36.456 ;
     RECT  18.205 3.12 18.608 3.144 ;
     RECT  18.529 4.176 18.608 5.064 ;
     RECT  17.809 6.672 18.608 15.336 ;
     RECT  18.565 16.32 18.608 36.456 ;
     RECT  18.277 37.872 18.608 62.424 ;
     RECT  18.608 2.148 18.712 62.652 ;
     RECT  18.712 2.418 18.904 62.382 ;
     RECT  18.904 23.856 18.965 39.288 ;
     RECT  18.965 23.856 19.043 38.808 ;
     RECT  19.043 36.48 19.045 38.808 ;
     RECT  18.904 11.76 19.073 15.336 ;
     RECT  18.904 16.32 19.073 22.488 ;
     RECT  18.904 2.736 19.109 8.184 ;
     RECT  19.073 11.76 19.139 15.24 ;
     RECT  19.139 11.76 19.181 14.856 ;
     RECT  19.045 36.912 19.217 38.808 ;
     RECT  19.109 2.736 19.361 3.144 ;
     RECT  19.109 4.176 19.433 8.184 ;
     RECT  19.433 4.32 19.505 8.184 ;
     RECT  18.904 40.56 19.721 62.28 ;
     RECT  19.721 40.56 19.865 44.232 ;
     RECT  19.865 40.56 19.937 41.064 ;
     RECT  19.181 12.24 19.973 14.856 ;
     RECT  19.043 23.856 19.973 34.632 ;
     RECT  19.937 40.56 20.009 41.016 ;
     RECT  19.217 36.912 20.149 38.232 ;
     RECT  19.973 23.856 20.207 27.912 ;
     RECT  19.505 7.44 20.221 8.184 ;
     RECT  19.973 29.232 20.221 34.632 ;
     RECT  19.361 3.12 20.261 3.144 ;
     RECT  20.149 35.952 20.329 38.232 ;
     RECT  20.005 39.312 20.329 39.336 ;
     RECT  20.009 40.848 20.405 41.016 ;
     RECT  19.073 16.32 20.509 22.2 ;
     RECT  20.509 15.552 20.545 22.2 ;
     RECT  20.207 23.328 20.545 27.912 ;
     RECT  20.221 29.232 20.545 34.776 ;
     RECT  20.329 35.952 20.545 39.336 ;
     RECT  20.221 7.44 20.581 8.52 ;
     RECT  18.904 9.6 20.581 10.68 ;
     RECT  19.973 12.24 20.581 14.52 ;
     RECT  20.405 40.992 20.729 41.016 ;
     RECT  20.545 29.232 20.765 39.336 ;
     RECT  19.865 42.096 20.765 44.232 ;
     RECT  20.581 7.44 20.78 10.68 ;
     RECT  20.765 39.312 20.801 39.336 ;
     RECT  19.505 4.32 20.909 6.408 ;
     RECT  20.545 15.552 21.041 27.912 ;
     RECT  20.765 29.232 21.089 38.184 ;
     RECT  20.765 42.432 21.107 44.232 ;
     RECT  20.78 7.392 21.109 10.68 ;
     RECT  20.909 4.32 21.116 5.976 ;
     RECT  21.109 7.392 21.125 10.776 ;
     RECT  20.581 11.952 21.157 14.52 ;
     RECT  21.125 8.688 21.193 10.776 ;
     RECT  21.157 11.808 21.193 14.52 ;
     RECT  21.116 4.272 21.203 5.976 ;
     RECT  21.193 8.688 21.203 14.52 ;
     RECT  21.203 4.32 21.233 5.976 ;
     RECT  21.203 9.36 21.233 11.832 ;
     RECT  21.089 29.232 21.233 29.832 ;
     RECT  21.089 37.056 21.233 38.184 ;
     RECT  21.107 42.528 21.305 44.232 ;
     RECT  21.041 15.552 21.347 27.96 ;
     RECT  21.233 29.232 21.445 29.688 ;
     RECT  21.445 29.184 21.449 29.688 ;
     RECT  21.203 13.056 21.481 14.52 ;
     RECT  21.347 15.552 21.481 19.992 ;
     RECT  21.305 42.72 21.481 44.232 ;
     RECT  19.721 45.504 21.481 62.28 ;
     RECT  21.449 29.184 21.517 29.592 ;
     RECT  21.347 21.12 21.553 27.96 ;
     RECT  21.517 29.088 21.553 29.592 ;
     RECT  21.089 31.008 21.665 36.072 ;
     RECT  21.233 37.056 21.701 37.608 ;
     RECT  21.481 42.72 21.709 62.28 ;
     RECT  21.709 43.008 21.877 62.28 ;
     RECT  21.665 31.008 21.953 34.44 ;
     RECT  21.373 39.888 22.021 39.912 ;
     RECT  21.233 4.944 22.057 5.976 ;
     RECT  21.125 7.392 22.101 7.416 ;
     RECT  21.233 9.36 22.163 9.672 ;
     RECT  21.233 10.656 22.201 11.832 ;
     RECT  22.101 7.392 22.205 7.992 ;
     RECT  21.877 43.008 22.205 62.616 ;
     RECT  21.481 3.312 22.237 3.336 ;
     RECT  22.205 43.008 22.241 44.232 ;
     RECT  22.057 4.944 22.261 6.312 ;
     RECT  21.553 21.12 22.277 29.592 ;
     RECT  22.237 2.784 22.309 3.336 ;
     RECT  22.261 4.8 22.309 6.312 ;
     RECT  21.665 35.52 22.309 36.072 ;
     RECT  21.701 37.056 22.309 37.512 ;
     RECT  22.021 39.312 22.381 39.912 ;
     RECT  22.277 23.28 22.457 29.592 ;
     RECT  22.309 2.784 22.525 3.672 ;
     RECT  22.309 4.656 22.525 6.312 ;
     RECT  21.953 31.008 22.777 34.2 ;
     RECT  21.481 13.056 22.817 19.992 ;
     RECT  22.277 21.12 22.849 22.056 ;
     RECT  22.201 10.656 22.853 11.928 ;
     RECT  22.817 15.552 22.853 19.992 ;
     RECT  22.205 7.92 22.885 7.992 ;
     RECT  22.853 15.552 22.961 19.944 ;
     RECT  22.849 20.976 22.961 22.056 ;
     RECT  22.457 23.28 22.997 28.488 ;
     RECT  22.525 2.784 23.101 6.312 ;
     RECT  22.457 29.52 23.101 29.592 ;
     RECT  22.777 30.864 23.101 34.2 ;
     RECT  22.309 35.52 23.101 37.512 ;
     RECT  22.381 39.312 23.125 40.152 ;
     RECT  22.885 7.92 23.173 8.52 ;
     RECT  22.163 9.6 23.173 9.672 ;
     RECT  22.961 21.024 23.245 22.056 ;
     RECT  22.997 23.28 23.245 24.216 ;
     RECT  23.101 2.784 23.317 6.84 ;
     RECT  23.173 7.92 23.317 9.672 ;
     RECT  23.125 39.264 23.317 40.152 ;
     RECT  23.317 2.784 23.365 9.672 ;
     RECT  22.853 10.656 23.365 11.496 ;
     RECT  23.101 35.52 23.425 37.992 ;
     RECT  23.317 39.264 23.425 40.872 ;
     RECT  22.241 43.008 23.425 44.184 ;
     RECT  23.425 43.008 23.677 44.424 ;
     RECT  22.997 25.2 23.713 28.488 ;
     RECT  23.101 29.52 23.713 34.2 ;
     RECT  23.677 42.816 23.749 44.424 ;
     RECT  22.205 45.696 23.785 62.616 ;
     RECT  23.749 42.768 23.821 44.424 ;
     RECT  23.713 25.2 23.893 34.2 ;
     RECT  23.425 35.52 23.893 41.16 ;
     RECT  23.245 21.024 23.965 24.216 ;
     RECT  22.961 15.552 24.001 19.368 ;
     RECT  23.965 20.688 24.001 24.216 ;
     RECT  23.365 2.784 24.008 11.496 ;
     RECT  22.817 13.056 24.008 14.28 ;
     RECT  24.001 15.552 24.008 24.216 ;
     RECT  23.893 25.2 24.008 41.16 ;
     RECT  23.821 42.72 24.008 44.424 ;
     RECT  23.785 45.648 24.008 62.616 ;
     RECT  24.008 2.148 24.112 62.652 ;
     RECT  24.112 2.418 24.304 62.382 ;
     RECT  24.304 3.792 24.329 7.464 ;
     RECT  24.304 23.04 24.401 27.912 ;
     RECT  24.304 29.088 24.401 62.136 ;
     RECT  24.329 4.992 24.437 7.464 ;
     RECT  24.304 8.496 24.515 10.968 ;
     RECT  24.401 31.968 24.545 62.136 ;
     RECT  24.545 37.968 24.581 62.136 ;
     RECT  24.304 13.056 24.689 14.808 ;
     RECT  24.515 8.496 24.761 10.68 ;
     RECT  24.401 24.192 24.761 27.912 ;
     RECT  24.401 29.088 24.833 30.888 ;
     RECT  24.437 4.992 25.193 7.416 ;
     RECT  24.833 29.616 25.193 30.888 ;
     RECT  24.581 38.16 25.229 62.136 ;
     RECT  24.329 3.792 25.297 4.008 ;
     RECT  25.193 4.992 25.297 7.368 ;
     RECT  24.689 13.632 25.369 14.808 ;
     RECT  24.401 23.04 25.369 23.064 ;
     RECT  25.193 29.664 25.369 30.888 ;
     RECT  24.545 31.968 25.369 36.936 ;
     RECT  24.761 24.624 25.405 27.912 ;
     RECT  25.405 24.624 25.445 28.44 ;
     RECT  24.304 15.984 25.517 21.96 ;
     RECT  25.229 38.448 25.553 62.136 ;
     RECT  25.553 42.48 25.571 62.136 ;
     RECT  25.369 13.632 25.585 14.904 ;
     RECT  25.517 15.984 25.585 18.216 ;
     RECT  25.571 44.064 25.612 62.136 ;
     RECT  25.297 3.792 25.621 7.368 ;
     RECT  25.517 19.248 25.621 21.96 ;
     RECT  25.369 23.04 25.621 23.4 ;
     RECT  25.369 29.664 25.621 36.936 ;
     RECT  25.585 13.632 25.661 18.216 ;
     RECT  25.621 19.248 25.667 23.4 ;
     RECT  25.297 12.096 25.693 12.12 ;
     RECT  24.761 8.496 25.729 10.44 ;
     RECT  25.693 11.76 25.729 12.12 ;
     RECT  25.612 44.16 25.772 62.136 ;
     RECT  25.369 2.64 25.82 2.664 ;
     RECT  25.82 2.256 25.861 2.664 ;
     RECT  25.621 3.744 25.861 7.368 ;
     RECT  25.772 44.16 25.873 62.424 ;
     RECT  25.861 2.256 25.907 7.368 ;
     RECT  25.621 29.664 25.985 37.032 ;
     RECT  25.729 8.496 26.057 12.12 ;
     RECT  25.661 13.632 26.06 17.64 ;
     RECT  25.667 19.248 26.129 23.352 ;
     RECT  25.985 29.664 26.129 34.824 ;
     RECT  25.985 35.952 26.129 37.032 ;
     RECT  26.06 13.104 26.147 17.64 ;
     RECT  26.129 29.664 26.201 34.2 ;
     RECT  26.129 23.136 26.381 23.352 ;
     RECT  25.907 3.216 26.435 7.368 ;
     RECT  25.873 44.16 26.453 62.472 ;
     RECT  26.381 23.136 26.489 23.304 ;
     RECT  25.445 24.624 26.489 26.856 ;
     RECT  26.147 13.68 26.597 17.64 ;
     RECT  26.201 31.632 26.597 34.2 ;
     RECT  26.057 8.496 26.737 9.624 ;
     RECT  25.445 28.416 26.737 28.44 ;
     RECT  25.553 39.024 26.809 41.208 ;
     RECT  26.737 27.696 26.845 28.44 ;
     RECT  26.201 29.664 26.845 30.168 ;
     RECT  26.129 19.248 26.849 21.528 ;
     RECT  26.129 36.72 26.849 37.032 ;
     RECT  26.849 37.008 26.957 37.032 ;
     RECT  26.737 7.968 27.029 9.624 ;
     RECT  26.597 31.632 27.169 31.656 ;
     RECT  26.809 38.688 27.205 41.208 ;
     RECT  27.205 38.688 27.308 41.448 ;
     RECT  26.845 27.696 27.349 30.168 ;
     RECT  27.169 31.152 27.349 31.656 ;
     RECT  27.308 38.16 27.349 41.448 ;
     RECT  27.349 37.104 27.395 41.448 ;
     RECT  26.849 19.248 27.421 21.48 ;
     RECT  26.489 23.28 27.421 23.304 ;
     RECT  26.489 24.624 27.421 26.664 ;
     RECT  26.597 16.32 27.461 17.64 ;
     RECT  27.421 23.28 27.493 26.664 ;
     RECT  27.349 27.696 27.493 31.656 ;
     RECT  26.597 13.68 27.497 15.336 ;
     RECT  27.421 19.008 27.497 21.48 ;
     RECT  26.435 3.216 27.529 6.936 ;
     RECT  27.493 23.28 27.565 31.656 ;
     RECT  26.597 32.784 27.565 34.2 ;
     RECT  27.529 3.216 27.709 6.984 ;
     RECT  27.029 9.072 27.709 9.624 ;
     RECT  26.057 11.136 27.709 12.12 ;
     RECT  27.709 9.072 27.745 12.12 ;
     RECT  27.497 13.68 27.745 15.24 ;
     RECT  27.395 38.736 27.785 41.448 ;
     RECT  26.453 44.16 27.889 44.424 ;
     RECT  26.453 45.696 27.889 62.472 ;
     RECT  27.497 20.88 27.925 21.48 ;
     RECT  27.565 23.28 27.929 34.2 ;
     RECT  27.709 2.976 27.965 6.984 ;
     RECT  27.889 44.16 28.033 62.472 ;
     RECT  27.929 23.28 28.037 27.768 ;
     RECT  28.037 23.376 28.145 27.768 ;
     RECT  27.929 29.04 28.145 34.2 ;
     RECT  28.145 27.696 28.181 27.768 ;
     RECT  27.029 7.968 28.285 7.992 ;
     RECT  27.395 37.104 28.285 37.464 ;
     RECT  28.285 7.872 28.325 7.992 ;
     RECT  28.145 29.808 28.397 34.2 ;
     RECT  27.925 20.88 28.433 21.672 ;
     RECT  28.397 30.144 28.453 34.2 ;
     RECT  27.785 38.784 28.453 41.448 ;
     RECT  25.571 42.48 28.453 43.08 ;
     RECT  28.453 30.144 28.537 34.728 ;
     RECT  27.497 19.008 28.609 19.656 ;
     RECT  27.745 9.072 28.681 15.24 ;
     RECT  28.609 18.96 28.753 19.656 ;
     RECT  28.433 20.88 28.753 21.528 ;
     RECT  28.285 36.624 28.753 37.464 ;
     RECT  28.681 9.072 28.789 15.288 ;
     RECT  27.461 16.32 28.789 17.448 ;
     RECT  28.537 30.144 28.933 35.352 ;
     RECT  28.753 36.48 28.933 37.464 ;
     RECT  28.181 27.744 28.969 27.768 ;
     RECT  28.789 9.072 29.077 17.448 ;
     RECT  28.453 38.784 29.149 43.08 ;
     RECT  27.965 2.976 29.408 6.84 ;
     RECT  28.325 7.872 29.408 7.896 ;
     RECT  29.077 9.072 29.408 17.784 ;
     RECT  28.753 18.96 29.408 21.528 ;
     RECT  28.145 23.376 29.408 26.664 ;
     RECT  28.969 27.744 29.408 27.96 ;
     RECT  28.933 30.144 29.408 37.464 ;
     RECT  29.149 38.784 29.408 43.128 ;
     RECT  28.033 44.16 29.408 62.52 ;
     RECT  29.408 2.148 29.512 62.652 ;
     RECT  29.512 2.418 29.704 62.52 ;
     RECT  29.704 18.816 29.917 28.488 ;
     RECT  29.917 18.816 29.932 22.584 ;
     RECT  29.932 18.816 29.939 22.44 ;
     RECT  29.939 18.816 30.017 19.944 ;
     RECT  29.704 13.296 30.089 17.688 ;
     RECT  29.704 30.624 30.089 35.832 ;
     RECT  30.017 18.816 30.269 18.888 ;
     RECT  29.704 38.736 30.275 62.52 ;
     RECT  29.917 23.712 30.305 28.488 ;
     RECT  29.704 37.056 30.697 37.176 ;
     RECT  30.275 38.736 30.701 47.064 ;
     RECT  30.275 48.096 30.737 62.52 ;
     RECT  29.704 2.592 30.773 6.696 ;
     RECT  30.697 36.384 30.773 37.176 ;
     RECT  30.773 2.592 30.809 5.496 ;
     RECT  30.773 6.672 30.809 6.696 ;
     RECT  30.089 13.296 30.908 15.288 ;
     RECT  29.704 8.112 30.913 11.784 ;
     RECT  30.701 38.736 30.949 45.72 ;
     RECT  30.305 23.712 30.953 28.008 ;
     RECT  30.737 49.776 30.953 62.52 ;
     RECT  30.913 7.392 30.997 11.784 ;
     RECT  30.908 13.056 30.997 15.288 ;
     RECT  30.953 23.712 31.057 27.624 ;
     RECT  30.809 2.592 31.097 3.336 ;
     RECT  29.939 21.12 31.129 22.44 ;
     RECT  31.057 23.664 31.129 27.624 ;
     RECT  30.773 36.384 31.133 37.08 ;
     RECT  30.089 30.624 31.196 35.112 ;
     RECT  30.949 38.448 31.205 45.72 ;
     RECT  31.196 30.192 31.237 35.112 ;
     RECT  30.737 48.096 31.241 48.792 ;
     RECT  30.997 7.392 31.277 15.288 ;
     RECT  31.129 21.12 31.277 27.624 ;
     RECT  31.237 29.76 31.277 35.112 ;
     RECT  30.809 4.368 31.283 5.496 ;
     RECT  31.277 29.76 31.283 34.728 ;
     RECT  31.277 13.296 31.309 15.288 ;
     RECT  30.089 16.32 31.309 17.688 ;
     RECT  31.097 2.736 31.349 3.336 ;
     RECT  31.205 38.544 31.385 45.72 ;
     RECT  30.017 19.92 31.453 19.944 ;
     RECT  31.277 21.12 31.453 23.976 ;
     RECT  31.309 13.296 31.525 17.688 ;
     RECT  30.269 18.816 31.525 18.84 ;
     RECT  31.349 2.784 31.529 3.336 ;
     RECT  31.525 13.296 31.597 18.84 ;
     RECT  31.453 19.92 31.597 23.976 ;
     RECT  31.385 38.544 31.601 45.576 ;
     RECT  30.701 46.752 31.601 46.824 ;
     RECT  31.277 7.392 31.709 11.928 ;
     RECT  31.709 9.072 31.745 9.624 ;
     RECT  31.283 30.816 31.745 34.728 ;
     RECT  31.283 4.992 31.777 5.496 ;
     RECT  31.709 10.704 31.781 11.928 ;
     RECT  31.597 13.296 31.817 23.976 ;
     RECT  31.601 39.312 31.817 45.576 ;
     RECT  31.781 10.752 31.925 11.928 ;
     RECT  31.817 13.296 31.961 19.32 ;
     RECT  31.529 2.928 32.141 3.336 ;
     RECT  31.817 39.84 32.141 45.576 ;
     RECT  31.745 31.056 32.195 34.728 ;
     RECT  32.141 39.84 32.195 44.184 ;
     RECT  32.141 3.312 32.285 3.336 ;
     RECT  31.283 29.76 32.317 29.784 ;
     RECT  31.925 11.28 32.425 11.928 ;
     RECT  31.961 13.296 32.425 18.072 ;
     RECT  32.425 11.28 32.429 18.072 ;
     RECT  31.277 25.008 32.461 26.904 ;
     RECT  32.195 31.056 32.483 31.944 ;
     RECT  30.953 50.064 32.537 62.52 ;
     RECT  31.709 7.392 32.573 7.896 ;
     RECT  31.777 4.992 32.605 5.88 ;
     RECT  31.241 48.096 32.641 48.456 ;
     RECT  31.133 36.384 32.677 36.408 ;
     RECT  32.281 37.632 32.677 37.656 ;
     RECT  32.677 36.384 32.717 37.656 ;
     RECT  32.717 36.384 32.78 37.32 ;
     RECT  32.195 39.84 32.821 43.944 ;
     RECT  31.745 9.12 32.857 9.624 ;
     RECT  32.317 28.944 32.865 29.784 ;
     RECT  32.483 31.056 32.865 31.32 ;
     RECT  32.461 25.008 32.897 27.192 ;
     RECT  32.857 9.12 32.929 9.672 ;
     RECT  32.865 28.944 32.929 31.32 ;
     RECT  32.195 33.072 32.929 34.728 ;
     RECT  32.78 35.856 32.929 37.32 ;
     RECT  32.605 4.512 32.965 5.88 ;
     RECT  32.929 8.88 33.02 10.248 ;
     RECT  31.817 20.592 33.037 23.976 ;
     RECT  32.929 28.32 33.1 31.32 ;
     RECT  32.429 14.496 33.116 18.072 ;
     RECT  31.961 19.296 33.116 19.32 ;
     RECT  32.573 7.824 33.164 7.896 ;
     RECT  33.02 8.88 33.164 10.296 ;
     RECT  32.965 4.512 33.181 5.928 ;
     RECT  33.116 14.496 33.203 19.464 ;
     RECT  33.037 20.544 33.203 23.976 ;
     RECT  33.181 3.648 33.205 5.928 ;
     RECT  33.164 7.824 33.251 10.296 ;
     RECT  32.821 39.792 33.301 43.944 ;
     RECT  32.141 45.168 33.301 45.576 ;
     RECT  32.429 11.28 33.329 13.368 ;
     RECT  33.203 19.296 33.329 19.32 ;
     RECT  32.897 25.008 33.401 27.096 ;
     RECT  33.301 39.792 33.437 45.576 ;
     RECT  33.1 28.944 33.469 31.32 ;
     RECT  33.437 39.792 33.539 43.8 ;
     RECT  33.437 45.168 33.577 45.576 ;
     RECT  31.601 46.8 33.577 46.824 ;
     RECT  33.203 21.408 33.581 23.976 ;
     RECT  32.641 48.096 33.605 49.32 ;
     RECT  32.537 50.688 33.605 62.52 ;
     RECT  33.469 28.944 33.649 31.368 ;
     RECT  32.929 33.072 33.649 37.32 ;
     RECT  33.577 45.168 33.649 46.824 ;
     RECT  33.605 48.096 33.649 62.52 ;
     RECT  33.203 14.496 33.685 17.64 ;
     RECT  33.649 45.168 33.689 62.52 ;
     RECT  33.689 45.168 33.725 49.464 ;
     RECT  33.581 21.408 33.761 22.872 ;
     RECT  33.649 32.832 33.761 37.32 ;
     RECT  33.205 3.648 33.793 6.696 ;
     RECT  33.649 28.944 33.829 31.704 ;
     RECT  33.251 8.304 33.973 10.296 ;
     RECT  33.829 28.944 33.973 31.752 ;
     RECT  33.761 32.832 33.973 37.224 ;
     RECT  33.581 23.856 34.009 23.976 ;
     RECT  33.401 25.008 34.009 26.904 ;
     RECT  33.329 11.76 34.045 13.368 ;
     RECT  33.685 14.4 34.045 17.64 ;
     RECT  33.689 50.832 34.045 62.52 ;
     RECT  34.189 38.784 34.225 38.808 ;
     RECT  34.045 11.76 34.369 17.64 ;
     RECT  33.973 28.944 34.441 37.224 ;
     RECT  34.009 23.856 34.549 26.904 ;
     RECT  33.973 8.304 34.657 10.68 ;
     RECT  34.369 11.712 34.657 18.168 ;
     RECT  33.539 40.56 34.657 43.8 ;
     RECT  33.761 22.752 34.693 22.872 ;
     RECT  34.549 23.856 34.693 27.192 ;
     RECT  34.657 40.56 34.693 43.896 ;
     RECT  33.725 45.168 34.693 45.624 ;
     RECT  33.761 21.408 34.729 21.672 ;
     RECT  34.693 22.752 34.729 27.192 ;
     RECT  34.729 21.408 34.801 27.192 ;
     RECT  34.441 28.176 34.801 37.224 ;
     RECT  33.793 3.648 34.808 7.08 ;
     RECT  34.657 8.304 34.808 18.168 ;
     RECT  34.801 21.408 34.808 37.224 ;
     RECT  34.225 38.784 34.808 39.24 ;
     RECT  34.693 40.416 34.808 43.896 ;
     RECT  34.693 44.88 34.808 45.624 ;
     RECT  33.725 46.8 34.808 49.464 ;
     RECT  34.045 50.832 34.808 62.616 ;
     RECT  34.808 2.148 34.912 62.652 ;
     RECT  34.912 2.418 35.104 62.382 ;
     RECT  35.104 9.552 35.129 14.232 ;
     RECT  35.104 23.856 35.165 34.632 ;
     RECT  35.104 15.456 35.201 22.872 ;
     RECT  35.201 15.456 35.219 21.576 ;
     RECT  35.104 44.88 35.273 62.136 ;
     RECT  35.273 46.176 35.507 62.136 ;
     RECT  35.201 22.752 35.525 22.872 ;
     RECT  35.104 4.992 35.533 8.472 ;
     RECT  35.165 24.432 35.561 34.632 ;
     RECT  35.104 35.904 35.561 37.464 ;
     RECT  35.104 2.496 35.705 4.008 ;
     RECT  35.219 19.2 35.705 19.32 ;
     RECT  35.104 40.416 35.705 43.896 ;
     RECT  35.219 20.688 35.741 21.576 ;
     RECT  35.219 15.456 35.813 18.168 ;
     RECT  35.561 24.432 35.813 29.688 ;
     RECT  35.533 7.68 35.957 8.472 ;
     RECT  35.507 46.176 35.993 49.752 ;
     RECT  35.129 9.6 36.083 14.232 ;
     RECT  35.993 47.76 36.083 49.752 ;
     RECT  35.104 39.216 36.133 39.288 ;
     RECT  35.705 40.416 36.133 41.208 ;
     RECT  35.705 42.192 36.188 43.896 ;
     RECT  35.273 44.88 36.188 45.144 ;
     RECT  35.813 27.84 36.275 29.688 ;
     RECT  36.188 42.192 36.275 45.144 ;
     RECT  35.813 15.456 36.277 16.344 ;
     RECT  35.507 50.928 36.461 62.136 ;
     RECT  35.741 21.12 36.493 21.576 ;
     RECT  35.525 22.752 36.493 22.776 ;
     RECT  36.275 44.88 36.497 45.144 ;
     RECT  36.493 21.12 36.529 22.776 ;
     RECT  35.957 7.92 36.533 8.472 ;
     RECT  35.813 24.432 36.533 26.856 ;
     RECT  35.705 2.496 36.569 3.912 ;
     RECT  36.529 21.12 36.601 22.872 ;
     RECT  35.561 30.96 36.601 34.632 ;
     RECT  35.561 35.904 36.601 35.928 ;
     RECT  36.569 2.496 36.605 2.52 ;
     RECT  36.533 24.432 36.611 26.664 ;
     RECT  36.461 50.928 36.637 58.44 ;
     RECT  35.561 37.44 36.673 37.464 ;
     RECT  35.813 17.424 36.677 18.168 ;
     RECT  36.601 30.96 36.709 35.928 ;
     RECT  36.083 11.376 36.713 14.232 ;
     RECT  36.673 37.44 36.713 38.232 ;
     RECT  36.601 21.12 36.785 23.112 ;
     RECT  36.785 23.088 36.853 23.112 ;
     RECT  36.611 24.432 36.853 24.504 ;
     RECT  36.275 28.176 36.853 29.688 ;
     RECT  36.709 30.72 36.853 35.928 ;
     RECT  36.853 28.176 36.893 35.928 ;
     RECT  36.893 33.024 36.899 35.928 ;
     RECT  36.893 28.176 36.94 31.608 ;
     RECT  36.94 30.72 36.947 31.608 ;
     RECT  36.94 28.176 36.965 29.688 ;
     RECT  36.533 7.968 36.997 8.472 ;
     RECT  36.083 9.6 36.997 10.104 ;
     RECT  36.785 21.12 37.001 21.96 ;
     RECT  36.965 28.272 37.001 28.968 ;
     RECT  37.001 28.368 37.037 28.968 ;
     RECT  36.133 39.216 37.037 41.208 ;
     RECT  36.997 7.968 37.069 10.104 ;
     RECT  36.899 35.904 37.073 35.928 ;
     RECT  36.713 38.16 37.073 38.232 ;
     RECT  36.275 42.192 37.109 43.752 ;
     RECT  35.993 46.176 37.109 46.776 ;
     RECT  36.637 50.832 37.177 58.44 ;
     RECT  36.461 59.52 37.177 62.136 ;
     RECT  36.713 11.76 37.213 14.232 ;
     RECT  36.853 23.088 37.217 24.504 ;
     RECT  35.705 19.296 37.244 19.32 ;
     RECT  36.277 15.408 37.285 16.344 ;
     RECT  36.677 17.424 37.285 17.736 ;
     RECT  37.244 19.296 37.285 19.656 ;
     RECT  35.533 4.992 37.289 6.696 ;
     RECT  37.285 19.296 37.289 20.04 ;
     RECT  36.899 33.024 37.289 34.632 ;
     RECT  37.213 11.76 37.325 14.424 ;
     RECT  37.213 36 37.393 36.024 ;
     RECT  37.069 7.968 37.433 10.296 ;
     RECT  37.325 11.76 37.433 14.184 ;
     RECT  37.177 50.736 37.433 58.44 ;
     RECT  36.497 44.88 37.465 44.904 ;
     RECT  37.465 44.88 37.477 45.048 ;
     RECT  37.037 39.984 37.501 41.208 ;
     RECT  37.109 42.192 37.501 43.032 ;
     RECT  36.569 3.888 37.573 3.912 ;
     RECT  37.289 4.992 37.573 6.312 ;
     RECT  37.109 46.368 37.573 46.776 ;
     RECT  36.083 47.76 37.573 49.608 ;
     RECT  37.289 19.392 37.58 20.04 ;
     RECT  37.001 21.12 37.58 21.528 ;
     RECT  37.433 11.76 37.613 14.136 ;
     RECT  37.573 3.888 37.649 6.312 ;
     RECT  37.613 13.008 37.649 14.136 ;
     RECT  37.649 3.888 37.667 6.264 ;
     RECT  37.58 19.392 37.667 21.528 ;
     RECT  37.217 23.712 37.667 24.504 ;
     RECT  37.433 50.784 37.693 58.44 ;
     RECT  37.433 8.16 37.721 10.296 ;
     RECT  37.667 23.712 37.721 23.736 ;
     RECT  37.721 8.64 37.757 10.296 ;
     RECT  37.667 19.392 37.757 20.04 ;
     RECT  37.289 33.024 37.793 33.048 ;
     RECT  36.947 31.584 37.933 31.608 ;
     RECT  37.285 15.408 37.937 17.736 ;
     RECT  37.693 54.432 37.969 58.44 ;
     RECT  37.177 59.52 37.969 62.568 ;
     RECT  37.667 3.888 37.973 3.96 ;
     RECT  37.937 16.32 37.973 17.736 ;
     RECT  37.933 31.296 37.973 32.472 ;
     RECT  37.037 28.512 38.041 28.968 ;
     RECT  37.501 39.984 38.101 43.032 ;
     RECT  37.477 44.16 38.101 45.048 ;
     RECT  37.289 34.608 38.113 34.632 ;
     RECT  37.393 36 38.113 36.12 ;
     RECT  37.573 46.368 38.147 49.608 ;
     RECT  36.611 25.488 38.149 26.664 ;
     RECT  37.973 3.936 38.153 3.96 ;
     RECT  38.149 25.2 38.153 26.664 ;
     RECT  38.153 25.2 38.189 25.656 ;
     RECT  38.041 28.512 38.189 29.016 ;
     RECT  37.073 38.16 38.221 38.184 ;
     RECT  38.189 25.2 38.225 25.512 ;
     RECT  37.973 31.296 38.297 31.32 ;
     RECT  38.113 34.608 38.329 36.12 ;
     RECT  38.153 26.64 38.369 26.664 ;
     RECT  38.221 38.16 38.396 38.664 ;
     RECT  38.396 37.2 38.483 38.664 ;
     RECT  38.329 34.128 38.524 36.12 ;
     RECT  38.101 39.984 38.581 45.048 ;
     RECT  38.147 46.368 38.581 49.032 ;
     RECT  37.969 54.432 38.581 62.568 ;
     RECT  37.667 21.216 38.689 21.48 ;
     RECT  38.581 39.984 38.771 49.032 ;
     RECT  38.771 43.344 38.88 49.032 ;
     RECT  37.693 50.784 38.924 53.304 ;
     RECT  37.757 19.392 38.945 19.416 ;
     RECT  38.483 38.16 38.977 38.664 ;
     RECT  38.689 21.216 38.981 21.672 ;
     RECT  38.924 50.688 39.011 53.304 ;
     RECT  37.613 11.76 39.017 11.976 ;
     RECT  37.667 4.992 39.085 6.264 ;
     RECT  39.085 4.56 39.089 6.264 ;
     RECT  39.089 4.56 39.125 5.112 ;
     RECT  37.757 9.6 39.125 10.296 ;
     RECT  38.977 38.16 39.157 38.808 ;
     RECT  38.771 39.984 39.161 42.264 ;
     RECT  38.981 21.216 39.193 21.24 ;
     RECT  37.973 32.448 39.337 32.472 ;
     RECT  39.157 38.16 39.337 38.952 ;
     RECT  39.161 39.984 39.337 40.104 ;
     RECT  38.653 7.392 39.349 7.416 ;
     RECT  38.905 8.496 39.349 8.52 ;
     RECT  39.011 50.928 39.356 53.304 ;
     RECT  38.581 54.432 39.356 62.616 ;
     RECT  38.437 26.928 39.517 26.952 ;
     RECT  38.524 34.128 39.553 35.592 ;
     RECT  39.089 6.096 39.589 6.264 ;
     RECT  39.349 7.392 39.589 8.52 ;
     RECT  39.517 26.928 39.697 27.864 ;
     RECT  38.189 28.944 39.697 29.016 ;
     RECT  39.125 4.56 39.805 4.584 ;
     RECT  39.805 4.416 39.841 4.584 ;
     RECT  39.697 26.928 40.013 29.016 ;
     RECT  39.013 30.048 40.013 30.072 ;
     RECT  39.337 31.776 40.013 32.472 ;
     RECT  39.161 41.088 40.057 42.264 ;
     RECT  38.88 43.344 40.057 48.504 ;
     RECT  39.553 34.128 40.069 35.784 ;
     RECT  39.017 11.952 40.093 11.976 ;
     RECT  37.649 13.008 40.093 13.656 ;
     RECT  39.409 23.328 40.129 23.352 ;
     RECT  40.069 34.128 40.165 36.024 ;
     RECT  39.841 3.84 40.208 4.584 ;
     RECT  39.589 6.096 40.208 8.52 ;
     RECT  39.125 9.6 40.208 9.624 ;
     RECT  40.093 11.952 40.208 13.656 ;
     RECT  37.973 16.32 40.208 17.64 ;
     RECT  39.193 21.12 40.208 21.24 ;
     RECT  40.129 23.328 40.208 23.928 ;
     RECT  38.225 25.2 40.208 25.224 ;
     RECT  40.013 26.928 40.208 32.472 ;
     RECT  40.165 33.648 40.208 36.024 ;
     RECT  39.337 38.16 40.208 40.104 ;
     RECT  40.057 41.088 40.208 48.504 ;
     RECT  39.229 49.632 40.208 49.656 ;
     RECT  39.356 50.928 40.208 62.616 ;
     RECT  40.208 2.148 40.312 62.652 ;
     RECT  40.312 2.418 40.504 62.382 ;
     RECT  40.504 44.352 40.637 48.504 ;
     RECT  40.504 23.616 40.673 30.744 ;
     RECT  40.504 11.952 40.681 16.584 ;
     RECT  40.504 41.232 40.691 43.176 ;
     RECT  40.673 23.616 40.709 29.256 ;
     RECT  40.504 50.928 40.781 62.04 ;
     RECT  40.504 39.888 40.787 40.056 ;
     RECT  40.637 44.352 40.853 48.264 ;
     RECT  40.504 5.76 40.889 7.416 ;
     RECT  40.504 17.616 40.961 18.6 ;
     RECT  40.853 44.352 41.069 47.88 ;
     RECT  40.889 5.76 41.177 6.84 ;
     RECT  40.504 19.92 41.219 22.2 ;
     RECT  40.709 23.616 41.219 26.808 ;
     RECT  40.691 41.232 41.249 42.84 ;
     RECT  40.504 33.648 41.357 38.856 ;
     RECT  40.673 30.24 41.363 30.744 ;
     RECT  41.357 34.128 41.393 38.856 ;
     RECT  40.681 14.64 41.429 16.584 ;
     RECT  40.504 8.544 41.452 10.296 ;
     RECT  41.219 21.312 41.465 22.2 ;
     RECT  41.177 5.76 41.497 6.312 ;
     RECT  40.504 2.64 41.557 4.44 ;
     RECT  41.497 5.424 41.557 6.312 ;
     RECT  40.504 31.776 41.669 32.472 ;
     RECT  41.363 30.72 41.677 30.744 ;
     RECT  41.669 31.776 41.677 33.048 ;
     RECT  41.605 49.344 41.677 49.368 ;
     RECT  40.781 50.928 41.677 61.992 ;
     RECT  41.393 34.128 41.747 34.152 ;
     RECT  41.452 8.544 41.749 8.856 ;
     RECT  41.219 26.112 41.753 26.808 ;
     RECT  41.677 30.72 41.753 33.048 ;
     RECT  41.677 49.344 41.756 61.992 ;
     RECT  41.749 7.872 41.789 8.856 ;
     RECT  41.557 2.64 41.795 6.312 ;
     RECT  41.393 35.568 41.843 38.856 ;
     RECT  41.795 2.64 41.857 6.12 ;
     RECT  40.787 39.984 41.861 40.056 ;
     RECT  41.249 42.816 41.861 42.84 ;
     RECT  41.756 49.344 41.891 62.424 ;
     RECT  41.891 51.456 41.897 62.424 ;
     RECT  41.753 26.112 41.969 26.664 ;
     RECT  41.969 26.64 41.987 26.664 ;
     RECT  41.452 10.272 41.989 10.296 ;
     RECT  40.681 11.952 41.989 13.32 ;
     RECT  41.843 35.856 42.001 38.856 ;
     RECT  41.861 39.984 42.001 40.008 ;
     RECT  41.897 51.504 42.001 62.424 ;
     RECT  41.989 10.272 42.041 13.32 ;
     RECT  42.041 11.04 42.076 13.32 ;
     RECT  40.961 17.616 42.109 18.264 ;
     RECT  42.001 51.504 42.113 62.472 ;
     RECT  41.069 44.352 42.145 47.16 ;
     RECT  41.429 14.64 42.149 16.536 ;
     RECT  41.219 19.92 42.181 19.944 ;
     RECT  41.465 21.312 42.181 22.104 ;
     RECT  42.109 17.616 42.193 18.84 ;
     RECT  41.891 49.344 42.221 50.136 ;
     RECT  42.221 49.344 42.325 49.8 ;
     RECT  42.145 44.352 42.329 47.592 ;
     RECT  41.857 2.592 42.361 6.12 ;
     RECT  42.149 14.64 42.361 16.008 ;
     RECT  42.329 47.04 42.365 47.592 ;
     RECT  42.181 19.92 42.401 22.104 ;
     RECT  42.361 2.256 42.419 6.12 ;
     RECT  42.329 44.352 42.428 45.768 ;
     RECT  42.401 19.92 42.437 20.808 ;
     RECT  42.419 2.256 42.445 3.096 ;
     RECT  42.361 14.496 42.473 16.008 ;
     RECT  42.076 11.808 42.509 13.32 ;
     RECT  40.709 27.888 42.509 29.256 ;
     RECT  41.249 41.232 42.509 41.832 ;
     RECT  42.428 43.536 42.515 45.768 ;
     RECT  42.509 27.888 42.617 29.064 ;
     RECT  42.365 47.136 42.721 47.592 ;
     RECT  42.325 48.672 42.721 49.8 ;
     RECT  42.437 20.112 42.725 20.808 ;
     RECT  41.753 30.72 42.757 32.472 ;
     RECT  41.219 23.616 42.797 25.08 ;
     RECT  42.193 17.616 42.865 18.792 ;
     RECT  42.725 20.112 42.869 20.664 ;
     RECT  42.001 35.856 42.869 40.008 ;
     RECT  42.869 39.6 42.937 40.008 ;
     RECT  42.473 15.312 42.977 16.008 ;
     RECT  42.113 51.696 42.977 62.472 ;
     RECT  42.829 26.784 43.009 26.808 ;
     RECT  42.617 27.888 43.009 28.968 ;
     RECT  42.869 20.112 43.013 20.136 ;
     RECT  42.977 51.888 43.049 62.472 ;
     RECT  42.757 30.72 43.081 33.432 ;
     RECT  42.401 21.936 43.085 22.104 ;
     RECT  42.869 35.856 43.153 38.472 ;
     RECT  42.515 43.632 43.157 45.768 ;
     RECT  43.081 10.464 43.189 10.488 ;
     RECT  42.509 11.808 43.189 11.832 ;
     RECT  43.081 30.192 43.193 33.432 ;
     RECT  42.509 12.864 43.225 13.32 ;
     RECT  43.153 35.184 43.265 38.472 ;
     RECT  41.789 7.872 43.285 8.568 ;
     RECT  43.189 10.464 43.297 11.832 ;
     RECT  42.419 4.512 43.333 6.12 ;
     RECT  42.721 47.136 43.34 49.8 ;
     RECT  43.333 4.512 43.369 6.264 ;
     RECT  42.865 17.088 43.373 18.792 ;
     RECT  43.34 47.136 43.381 50.664 ;
     RECT  43.369 4.512 43.405 6.792 ;
     RECT  43.285 7.872 43.405 9.096 ;
     RECT  43.265 35.184 43.405 35.928 ;
     RECT  43.381 47.136 43.427 50.856 ;
     RECT  42.937 39.6 43.441 40.2 ;
     RECT  42.509 41.232 43.441 41.4 ;
     RECT  42.445 2.592 43.477 3.096 ;
     RECT  42.797 23.616 43.477 24.648 ;
     RECT  43.405 4.512 43.589 9.096 ;
     RECT  43.373 17.856 43.665 18.792 ;
     RECT  43.589 4.656 43.717 9.096 ;
     RECT  43.297 10.272 43.717 11.832 ;
     RECT  43.225 12.864 43.717 13.848 ;
     RECT  43.009 26.784 43.729 28.968 ;
     RECT  43.193 30.192 43.763 33.048 ;
     RECT  43.441 39.6 43.765 41.4 ;
     RECT  42.997 42.432 43.765 42.456 ;
     RECT  43.717 4.656 43.805 13.848 ;
     RECT  43.805 4.656 43.811 9.48 ;
     RECT  43.729 26.112 43.861 28.968 ;
     RECT  43.763 30.192 43.861 33 ;
     RECT  43.157 45.216 43.873 45.768 ;
     RECT  43.427 47.136 43.873 49.8 ;
     RECT  43.805 10.56 43.907 13.848 ;
     RECT  43.861 26.112 43.907 33 ;
     RECT  43.765 39.6 43.913 42.456 ;
     RECT  42.977 15.504 43.957 16.008 ;
     RECT  43.049 51.936 44.017 62.472 ;
     RECT  43.907 10.56 44.021 12.552 ;
     RECT  43.477 22.752 44.053 24.648 ;
     RECT  44.053 22.032 44.089 24.648 ;
     RECT  44.089 22.032 44.149 24.744 ;
     RECT  43.907 26.112 44.149 29.88 ;
     RECT  44.149 22.032 44.161 29.88 ;
     RECT  44.161 21.696 44.195 29.88 ;
     RECT  43.811 6.672 44.273 9.096 ;
     RECT  43.405 34.32 44.3 35.928 ;
     RECT  43.907 13.824 44.305 13.848 ;
     RECT  43.913 39.6 44.305 41.928 ;
     RECT  43.157 43.632 44.305 43.656 ;
     RECT  43.873 45.216 44.305 49.8 ;
     RECT  43.957 15.504 44.377 16.824 ;
     RECT  43.665 17.856 44.377 19.848 ;
     RECT  44.195 21.696 44.381 26.232 ;
     RECT  44.195 27.6 44.381 29.88 ;
     RECT  43.477 2.592 44.387 3.48 ;
     RECT  44.305 42.96 44.437 43.656 ;
     RECT  44.305 44.88 44.437 49.8 ;
     RECT  44.437 42.96 44.483 49.8 ;
     RECT  44.483 45.744 44.633 49.8 ;
     RECT  44.305 13.824 44.701 14.232 ;
     RECT  44.3 34.128 44.701 35.928 ;
     RECT  43.265 37.008 44.737 38.472 ;
     RECT  43.427 50.832 44.809 50.856 ;
     RECT  44.017 51.936 44.809 62.52 ;
     RECT  44.701 13.824 44.953 14.424 ;
     RECT  44.377 15.504 44.953 19.848 ;
     RECT  44.381 21.696 44.953 25.176 ;
     RECT  44.305 39.504 44.953 41.928 ;
     RECT  44.483 42.96 44.953 44.472 ;
     RECT  44.701 33.984 44.965 35.928 ;
     RECT  44.737 36.912 44.965 38.472 ;
     RECT  43.907 31.152 45.013 33 ;
     RECT  44.965 33.984 45.013 38.472 ;
     RECT  44.953 21.648 45.025 25.176 ;
     RECT  43.811 4.656 45.068 5.688 ;
     RECT  44.953 13.824 45.157 19.848 ;
     RECT  45.025 20.976 45.157 25.176 ;
     RECT  45.068 4.32 45.205 5.688 ;
     RECT  44.273 6.672 45.205 8.856 ;
     RECT  45.013 31.152 45.277 38.472 ;
     RECT  44.953 39.504 45.277 44.472 ;
     RECT  45.277 31.152 45.421 44.472 ;
     RECT  44.021 10.56 45.493 12.456 ;
     RECT  45.421 30.432 45.493 44.472 ;
     RECT  44.633 45.744 45.493 49.608 ;
     RECT  45.157 13.824 45.601 25.176 ;
     RECT  44.381 26.208 45.601 26.232 ;
     RECT  44.387 2.592 45.608 2.904 ;
     RECT  45.205 4.32 45.608 8.856 ;
     RECT  45.493 9.888 45.608 12.456 ;
     RECT  45.601 13.824 45.608 26.232 ;
     RECT  44.381 27.6 45.608 28.968 ;
     RECT  45.493 30.432 45.608 49.608 ;
     RECT  44.809 50.832 45.608 62.52 ;
     RECT  45.608 2.148 45.712 62.652 ;
     RECT  45.712 2.418 45.904 62.652 ;
     RECT  45.904 36.288 46.001 62.652 ;
     RECT  46.001 36.288 46.019 41.256 ;
     RECT  46.001 42.576 46.073 62.652 ;
     RECT  46.073 43.632 46.109 62.652 ;
     RECT  45.904 3.888 46.181 8.856 ;
     RECT  46.109 51.264 46.213 62.652 ;
     RECT  46.019 36.528 46.217 41.256 ;
     RECT  46.181 3.888 46.253 8.472 ;
     RECT  45.904 10.896 46.259 32.904 ;
     RECT  45.904 9.888 46.289 9.912 ;
     RECT  46.259 10.896 46.355 24.888 ;
     RECT  46.355 23.52 46.397 24.888 ;
     RECT  46.355 10.896 46.433 22.536 ;
     RECT  46.433 17.616 46.643 22.536 ;
     RECT  46.109 43.632 46.757 50.04 ;
     RECT  46.253 3.888 46.865 3.912 ;
     RECT  46.259 26.256 46.865 32.904 ;
     RECT  46.213 51.264 46.901 62.664 ;
     RECT  46.253 5.328 46.931 8.472 ;
     RECT  46.433 10.896 46.937 16.584 ;
     RECT  46.397 23.52 46.973 24.504 ;
     RECT  46.931 5.328 47.045 8.136 ;
     RECT  46.643 20.448 47.081 22.536 ;
     RECT  45.904 34.368 47.113 34.968 ;
     RECT  46.217 38.256 47.117 41.256 ;
     RECT  47.081 20.976 47.153 22.536 ;
     RECT  46.757 43.632 47.153 49.608 ;
     RECT  47.153 20.976 47.189 22.2 ;
     RECT  47.117 40.56 47.219 41.256 ;
     RECT  46.865 26.256 47.257 27.384 ;
     RECT  47.117 38.256 47.261 39.096 ;
     RECT  47.261 38.256 47.276 38.952 ;
     RECT  46.937 10.896 47.315 12.552 ;
     RECT  47.219 40.992 47.317 41.256 ;
     RECT  46.073 42.576 47.317 42.6 ;
     RECT  47.045 6.144 47.333 8.136 ;
     RECT  47.153 43.632 47.333 44.472 ;
     RECT  46.901 51.264 47.333 62.472 ;
     RECT  47.113 34.368 47.401 35.304 ;
     RECT  46.217 36.528 47.401 36.936 ;
     RECT  47.315 10.896 47.405 11.304 ;
     RECT  47.401 34.368 47.437 36.936 ;
     RECT  47.276 38.112 47.437 38.952 ;
     RECT  47.333 51.264 47.441 51.48 ;
     RECT  47.333 43.632 47.477 43.848 ;
     RECT  47.441 51.264 47.513 51.288 ;
     RECT  47.317 40.992 47.545 42.6 ;
     RECT  47.153 45.792 47.585 49.608 ;
     RECT  47.437 34.368 47.603 38.952 ;
     RECT  47.545 40.992 47.629 42.792 ;
     RECT  46.937 13.584 47.653 16.584 ;
     RECT  46.643 17.616 47.653 19.416 ;
     RECT  46.865 28.416 47.653 32.904 ;
     RECT  47.603 34.368 47.653 35.88 ;
     RECT  47.629 40.992 47.729 42.744 ;
     RECT  46.973 23.52 47.761 24.36 ;
     RECT  47.729 40.992 47.801 41.64 ;
     RECT  47.653 13.584 47.845 19.416 ;
     RECT  47.257 25.968 47.905 27.384 ;
     RECT  47.333 6.144 47.909 7.416 ;
     RECT  47.845 13.584 47.945 19.656 ;
     RECT  45.904 2.88 48.049 2.904 ;
     RECT  47.477 43.776 48.089 43.848 ;
     RECT  47.585 45.792 48.157 45.864 ;
     RECT  47.333 52.704 48.197 62.472 ;
     RECT  47.909 6.528 48.325 7.416 ;
     RECT  48.265 8.928 48.325 8.952 ;
     RECT  47.977 10.32 48.325 10.344 ;
     RECT  47.945 17.616 48.332 19.656 ;
     RECT  47.189 20.976 48.332 22.056 ;
     RECT  48.325 6.528 48.371 10.344 ;
     RECT  48.332 17.616 48.419 22.056 ;
     RECT  48.157 45.648 48.437 45.864 ;
     RECT  47.905 25.632 48.469 27.384 ;
     RECT  47.653 28.416 48.469 35.88 ;
     RECT  48.437 44.976 48.476 45.864 ;
     RECT  47.315 12.528 48.481 12.552 ;
     RECT  47.945 13.584 48.481 16.584 ;
     RECT  47.761 23.376 48.515 24.36 ;
     RECT  48.476 44.016 48.521 45.864 ;
     RECT  48.469 25.632 48.563 35.88 ;
     RECT  48.521 44.016 48.563 44.376 ;
     RECT  48.563 25.728 48.604 35.88 ;
     RECT  48.481 12.528 48.613 16.584 ;
     RECT  48.553 51.072 48.613 51.096 ;
     RECT  48.515 23.376 48.629 23.4 ;
     RECT  47.585 47.04 48.661 49.608 ;
     RECT  48.613 51.072 48.661 51.144 ;
     RECT  48.049 2.592 48.697 2.904 ;
     RECT  48.197 52.704 48.697 61.8 ;
     RECT  48.661 47.04 48.733 51.144 ;
     RECT  48.697 52.416 48.733 61.8 ;
     RECT  47.603 36.912 48.769 38.952 ;
     RECT  48.521 45.648 48.769 45.864 ;
     RECT  48.733 47.04 48.769 61.8 ;
     RECT  48.716 11.28 48.803 11.304 ;
     RECT  48.613 12.336 48.805 16.584 ;
     RECT  48.419 21.12 48.877 22.056 ;
     RECT  48.769 36.912 48.881 39.864 ;
     RECT  48.371 6.528 48.949 10.248 ;
     RECT  48.881 36.912 48.949 37.416 ;
     RECT  48.881 38.496 48.989 39.864 ;
     RECT  48.604 31.104 48.997 35.88 ;
     RECT  48.949 36.864 48.997 37.416 ;
     RECT  48.604 25.728 49.061 29.928 ;
     RECT  47.729 42.72 49.097 42.744 ;
     RECT  47.801 40.992 49.141 41.016 ;
     RECT  48.949 6.24 49.169 10.248 ;
     RECT  48.805 11.376 49.169 16.584 ;
     RECT  49.169 11.376 49.18 14.088 ;
     RECT  49.141 40.992 49.187 41.64 ;
     RECT  48.805 5.184 49.205 5.208 ;
     RECT  49.169 6.24 49.205 9.144 ;
     RECT  48.989 38.496 49.205 38.52 ;
     RECT  48.877 21.12 49.241 22.248 ;
     RECT  49.18 11.376 49.349 13.848 ;
     RECT  49.187 41.568 49.381 41.64 ;
     RECT  48.997 31.104 49.385 37.416 ;
     RECT  49.165 42.768 49.427 42.792 ;
     RECT  48.769 45.648 49.457 61.8 ;
     RECT  49.381 41.568 49.493 41.784 ;
     RECT  49.457 61.104 49.493 61.8 ;
     RECT  49.241 22.032 49.561 22.248 ;
     RECT  48.563 44.064 49.561 44.376 ;
     RECT  49.457 45.648 49.561 59.832 ;
     RECT  49.205 6.24 49.571 8.712 ;
     RECT  48.419 17.616 49.597 20.136 ;
     RECT  49.597 17.616 49.601 20.52 ;
     RECT  49.349 11.376 49.637 11.64 ;
     RECT  49.169 15.696 49.637 16.584 ;
     RECT  49.561 44.064 49.669 59.832 ;
     RECT  49.637 15.84 49.772 16.584 ;
     RECT  49.601 17.616 49.772 17.64 ;
     RECT  49.385 31.104 49.957 32.808 ;
     RECT  49.669 44.016 49.957 59.832 ;
     RECT  49.493 61.728 50.029 61.8 ;
     RECT  49.061 29.904 50.101 29.928 ;
     RECT  49.957 30.96 50.101 32.808 ;
     RECT  49.169 10.176 50.173 10.248 ;
     RECT  50.173 9.696 50.461 10.248 ;
     RECT  49.637 11.376 50.461 11.496 ;
     RECT  48.989 39.504 50.461 39.864 ;
     RECT  49.385 34.032 50.569 37.416 ;
     RECT  49.571 6.24 50.605 7.992 ;
     RECT  49.237 24.528 50.605 24.552 ;
     RECT  49.061 25.728 50.636 28.824 ;
     RECT  50.101 29.904 50.636 32.808 ;
     RECT  50.605 5.28 50.641 7.992 ;
     RECT  49.561 22.032 50.677 22.824 ;
     RECT  50.461 9.696 50.713 11.496 ;
     RECT  48.697 2.592 50.725 3.24 ;
     RECT  50.641 5.136 50.725 7.992 ;
     RECT  50.713 9.12 50.725 11.496 ;
     RECT  49.772 15.84 50.725 17.64 ;
     RECT  49.601 18.72 50.725 20.52 ;
     RECT  50.569 34.032 50.749 38.184 ;
     RECT  50.461 39.312 50.749 39.864 ;
     RECT  50.725 4.896 50.773 11.496 ;
     RECT  50.725 15.84 50.785 20.52 ;
     RECT  50.749 34.032 50.785 39.864 ;
     RECT  50.725 2.592 50.821 3.864 ;
     RECT  50.773 4.896 50.821 12.216 ;
     RECT  50.677 21.84 50.821 22.824 ;
     RECT  50.605 24.432 50.849 24.552 ;
     RECT  50.636 25.728 50.849 32.808 ;
     RECT  50.821 2.592 50.869 12.216 ;
     RECT  49.349 13.296 50.869 13.848 ;
     RECT  50.785 15.84 50.869 20.664 ;
     RECT  50.849 24.432 50.869 32.808 ;
     RECT  50.785 34.032 50.869 40.2 ;
     RECT  50.869 2.592 51.008 20.664 ;
     RECT  50.821 21.792 51.008 22.824 ;
     RECT  50.869 24.432 51.008 40.344 ;
     RECT  49.493 41.76 51.008 41.784 ;
     RECT  49.957 43.536 51.008 59.832 ;
     RECT  50.029 61.728 51.008 62.424 ;
     RECT  51.008 2.148 51.112 62.652 ;
     RECT  51.112 2.418 51.113 62.424 ;
     RECT  51.113 2.418 51.304 62.382 ;
     RECT  51.304 50.16 51.329 51.48 ;
     RECT  51.304 15.024 51.365 15.864 ;
     RECT  51.304 17.616 51.365 18.792 ;
     RECT  51.304 24.432 51.365 24.744 ;
     RECT  51.304 25.728 51.401 25.992 ;
     RECT  51.329 50.16 51.401 51.432 ;
     RECT  51.304 2.592 51.473 7.416 ;
     RECT  51.304 11.04 51.473 11.976 ;
     RECT  51.304 30.96 51.491 40.728 ;
     RECT  51.304 42.192 51.509 46.248 ;
     RECT  51.304 55.44 51.509 59.832 ;
     RECT  51.304 20.016 51.689 22.824 ;
     RECT  51.509 42.192 51.797 45.864 ;
     RECT  51.401 50.16 51.869 51.192 ;
     RECT  51.797 42.192 51.941 42.792 ;
     RECT  51.304 61.248 51.977 62.28 ;
     RECT  51.473 11.04 52.013 11.784 ;
     RECT  51.941 42.192 52.013 42.696 ;
     RECT  51.304 47.664 52.049 48.456 ;
     RECT  51.473 2.784 52.265 7.416 ;
     RECT  51.365 15.024 52.265 15.048 ;
     RECT  52.265 2.784 52.301 5.208 ;
     RECT  51.869 50.16 52.333 50.184 ;
     RECT  51.491 30.96 52.357 37.896 ;
     RECT  51.365 24.72 52.373 24.744 ;
     RECT  51.304 13.056 52.405 13.848 ;
     RECT  52.301 2.88 52.409 5.208 ;
     RECT  52.333 49.488 52.441 50.184 ;
     RECT  51.304 8.448 52.445 9.912 ;
     RECT  52.357 30.576 52.445 37.896 ;
     RECT  51.509 55.44 52.445 59.784 ;
     RECT  51.689 20.016 52.481 22.776 ;
     RECT  51.491 39.36 52.553 40.728 ;
     RECT  52.445 8.976 52.585 9.912 ;
     RECT  52.013 11.04 52.585 11.688 ;
     RECT  51.304 52.704 52.597 54.456 ;
     RECT  51.304 27.408 52.693 29.256 ;
     RECT  52.597 51.84 52.693 54.456 ;
     RECT  52.265 6.192 52.729 7.416 ;
     RECT  52.481 20.016 52.729 22.056 ;
     RECT  52.369 17.04 52.751 17.064 ;
     RECT  51.365 18.192 52.751 18.792 ;
     RECT  52.441 49.44 52.769 50.184 ;
     RECT  52.409 3.408 52.787 5.208 ;
     RECT  52.751 17.04 52.789 18.792 ;
     RECT  52.405 13.056 52.801 13.992 ;
     RECT  52.729 6.192 52.837 7.464 ;
     RECT  52.693 27.408 52.837 29.592 ;
     RECT  51.797 43.776 52.909 45.864 ;
     RECT  51.401 25.776 52.945 25.992 ;
     RECT  52.837 27.216 52.945 29.592 ;
     RECT  52.945 25.776 52.981 29.592 ;
     RECT  52.787 5.088 52.985 5.208 ;
     RECT  52.049 47.664 53.017 47.832 ;
     RECT  52.837 6.192 53.027 7.992 ;
     RECT  52.789 16.848 53.053 18.792 ;
     RECT  52.729 19.776 53.053 22.056 ;
     RECT  52.769 49.44 53.053 49.56 ;
     RECT  52.445 55.968 53.089 59.784 ;
     RECT  52.693 51.84 53.125 54.744 ;
     RECT  53.089 55.968 53.161 59.88 ;
     RECT  51.977 61.248 53.161 62.136 ;
     RECT  52.585 8.976 53.165 11.688 ;
     RECT  53.053 48.96 53.165 49.56 ;
     RECT  52.013 42.192 53.233 42.216 ;
     RECT  52.909 43.776 53.233 46.296 ;
     RECT  53.161 55.968 53.237 62.136 ;
     RECT  53.165 11.088 53.305 11.688 ;
     RECT  52.801 13.056 53.305 14.52 ;
     RECT  52.873 23.808 53.305 23.88 ;
     RECT  53.027 6.192 53.345 7.464 ;
     RECT  53.237 55.968 53.345 59.784 ;
     RECT  53.305 11.088 53.381 14.52 ;
     RECT  53.053 16.848 53.381 22.056 ;
     RECT  53.125 51.168 53.417 54.744 ;
     RECT  52.981 25.056 53.489 29.592 ;
     RECT  53.381 19.296 53.525 22.056 ;
     RECT  52.445 30.768 53.557 34.68 ;
     RECT  52.445 35.712 53.557 37.416 ;
     RECT  53.557 30.768 53.593 37.416 ;
     RECT  53.381 16.848 53.665 18.264 ;
     RECT  53.345 6.192 53.705 6.936 ;
     RECT  53.593 30.768 53.737 38.136 ;
     RECT  52.553 39.36 53.737 40.344 ;
     RECT  53.665 16.512 53.773 18.264 ;
     RECT  53.233 42.192 53.773 46.296 ;
     RECT  53.737 30.768 53.849 40.344 ;
     RECT  53.417 51.168 53.849 54.456 ;
     RECT  53.305 23.04 53.881 23.88 ;
     RECT  53.773 41.952 53.885 46.296 ;
     RECT  53.237 60.816 53.921 62.136 ;
     RECT  53.849 51.936 53.957 54.456 ;
     RECT  52.787 3.408 53.993 3.432 ;
     RECT  53.849 35.664 53.993 40.344 ;
     RECT  53.381 11.232 54.085 14.52 ;
     RECT  53.773 15.888 54.085 18.264 ;
     RECT  53.885 41.952 54.169 42.888 ;
     RECT  54.085 11.232 54.173 18.264 ;
     RECT  53.993 35.712 54.179 40.344 ;
     RECT  53.345 56.256 54.205 59.784 ;
     RECT  54.179 35.712 54.245 37.224 ;
     RECT  54.205 56.256 54.277 59.832 ;
     RECT  53.921 60.816 54.277 61.752 ;
     RECT  53.705 6.192 54.281 6.6 ;
     RECT  54.173 11.616 54.281 18.264 ;
     RECT  54.169 41.76 54.281 42.888 ;
     RECT  53.525 20.016 54.313 22.056 ;
     RECT  53.881 23.04 54.313 23.928 ;
     RECT  53.165 8.976 54.349 9.912 ;
     RECT  54.313 20.016 54.349 23.928 ;
     RECT  54.281 42.528 54.353 42.888 ;
     RECT  52.985 5.184 54.389 5.208 ;
     RECT  54.349 20.016 54.457 24.072 ;
     RECT  53.489 25.056 54.457 28.2 ;
     RECT  53.165 49.44 54.493 49.56 ;
     RECT  54.493 49.248 54.497 49.56 ;
     RECT  54.349 8.88 54.565 9.912 ;
     RECT  54.457 20.016 54.565 28.2 ;
     RECT  53.489 29.472 54.565 29.592 ;
     RECT  53.957 52.176 54.569 54.456 ;
     RECT  54.281 11.616 54.605 13.848 ;
     RECT  54.281 15.072 54.629 18.264 ;
     RECT  54.629 15.072 54.641 18.792 ;
     RECT  53.849 30.768 54.641 34.632 ;
     RECT  54.353 42.528 54.677 42.744 ;
     RECT  54.565 7.92 54.707 9.912 ;
     RECT  54.565 20.016 54.713 29.688 ;
     RECT  54.281 6.192 54.745 6.312 ;
     RECT  54.707 8.976 54.749 9.912 ;
     RECT  54.605 11.616 54.749 13.56 ;
     RECT  54.713 25.968 54.755 29.688 ;
     RECT  54.749 9.36 54.781 9.912 ;
     RECT  54.677 42.528 54.785 42.552 ;
     RECT  54.755 26.592 54.853 29.688 ;
     RECT  54.641 30.768 54.853 34.152 ;
     RECT  54.853 2.832 54.889 2.856 ;
     RECT  54.277 56.256 55.033 61.752 ;
     RECT  54.889 2.256 55.045 2.856 ;
     RECT  54.749 11.616 55.056 13.416 ;
     RECT  55.045 2.256 55.091 3.816 ;
     RECT  53.017 47.328 55.177 47.832 ;
     RECT  54.497 49.248 55.177 49.272 ;
     RECT  54.853 26.592 55.181 34.152 ;
     RECT  54.641 15.888 55.213 18.792 ;
     RECT  55.177 47.328 55.213 49.272 ;
     RECT  54.245 35.712 55.249 36.792 ;
     RECT  55.033 56.256 55.285 62.136 ;
     RECT  55.091 2.832 55.321 3.816 ;
     RECT  53.885 44.16 55.331 46.296 ;
     RECT  55.213 15.888 55.379 18.84 ;
     RECT  54.745 6.096 55.393 6.312 ;
     RECT  55.213 47.28 55.393 49.272 ;
     RECT  55.379 15.888 55.397 18.792 ;
     RECT  55.285 55.92 55.397 62.136 ;
     RECT  55.393 47.088 55.465 49.272 ;
     RECT  55.321 2.832 55.525 4.584 ;
     RECT  55.393 6.096 55.525 6.888 ;
     RECT  54.569 52.272 55.537 54.456 ;
     RECT  55.181 30.768 55.609 34.152 ;
     RECT  55.465 47.088 55.753 49.752 ;
     RECT  55.753 47.088 55.825 50.328 ;
     RECT  55.537 51.648 55.825 54.456 ;
     RECT  55.056 11.664 55.861 13.416 ;
     RECT  55.609 30.768 55.897 34.344 ;
     RECT  55.249 35.712 55.897 37.08 ;
     RECT  54.781 9.36 56.005 10.2 ;
     RECT  55.897 30.768 56.005 37.08 ;
     RECT  54.179 38.592 56.005 40.344 ;
     RECT  55.825 47.088 56.149 54.456 ;
     RECT  55.397 55.92 56.149 61.752 ;
     RECT  55.181 26.592 56.221 29.592 ;
     RECT  56.005 30.768 56.221 40.344 ;
     RECT  54.713 20.016 56.293 24.648 ;
     RECT  55.331 44.16 56.293 46.008 ;
     RECT  56.293 19.872 56.329 24.648 ;
     RECT  55.525 2.832 56.408 6.888 ;
     RECT  54.707 7.92 56.408 7.944 ;
     RECT  56.005 9.36 56.408 10.248 ;
     RECT  55.861 11.664 56.408 13.704 ;
     RECT  55.861 15.6 56.408 15.624 ;
     RECT  55.397 16.848 56.408 18.792 ;
     RECT  56.329 19.824 56.408 24.648 ;
     RECT  56.221 26.592 56.408 40.344 ;
     RECT  56.293 41.904 56.408 41.928 ;
     RECT  55.825 43.152 56.408 43.176 ;
     RECT  56.293 44.16 56.408 46.056 ;
     RECT  56.149 47.088 56.408 61.752 ;
     RECT  56.408 2.148 56.512 62.652 ;
     RECT  56.512 2.418 56.704 62.382 ;
     RECT  56.704 47.424 56.917 53.064 ;
     RECT  56.704 31.392 56.945 32.76 ;
     RECT  56.704 35.28 56.981 42.216 ;
     RECT  56.917 47.424 56.981 53.016 ;
     RECT  56.981 48.432 57.017 49.272 ;
     RECT  56.704 22.752 57.089 30.072 ;
     RECT  56.981 35.424 57.089 42.216 ;
     RECT  56.981 47.424 57.089 47.448 ;
     RECT  56.981 50.64 57.089 53.016 ;
     RECT  56.704 8.832 57.1 9.576 ;
     RECT  56.704 15.936 57.244 21.528 ;
     RECT  57.089 35.52 57.292 42.216 ;
     RECT  56.704 10.992 57.305 14.088 ;
     RECT  57.292 39.312 57.305 42.216 ;
     RECT  57.017 49.2 57.377 49.272 ;
     RECT  57.292 35.52 57.413 38.28 ;
     RECT  57.244 17.568 57.484 21.528 ;
     RECT  57.484 19.824 57.521 21.528 ;
     RECT  57.089 22.752 57.539 24.648 ;
     RECT  57.413 35.52 57.539 38.184 ;
     RECT  57.305 11.664 57.587 14.088 ;
     RECT  57.484 17.568 57.593 18.744 ;
     RECT  57.587 11.664 57.629 13.416 ;
     RECT  57.244 15.936 57.629 16.584 ;
     RECT  57.629 15.936 57.665 16.488 ;
     RECT  57.089 50.832 57.665 53.016 ;
     RECT  57.089 25.872 57.829 30.072 ;
     RECT  56.945 31.392 57.829 32.328 ;
     RECT  57.665 15.984 57.845 16.488 ;
     RECT  57.829 25.872 57.875 32.328 ;
     RECT  57.875 28.128 57.913 32.328 ;
     RECT  57.665 51.168 57.913 53.016 ;
     RECT  57.521 19.92 57.925 21.528 ;
     RECT  57.539 22.752 57.925 23.4 ;
     RECT  56.704 44.448 57.949 44.472 ;
     RECT  57.913 51.168 57.953 53.064 ;
     RECT  57.805 14.4 57.985 14.424 ;
     RECT  57.949 43.872 57.989 44.472 ;
     RECT  57.925 19.92 58.012 23.4 ;
     RECT  56.704 5.76 58.021 6.264 ;
     RECT  56.704 7.392 58.021 7.8 ;
     RECT  57.953 52.704 58.025 53.064 ;
     RECT  57.913 28.128 58.061 33.048 ;
     RECT  57.305 39.312 58.061 39.336 ;
     RECT  58.021 5.76 58.105 7.8 ;
     RECT  58.105 5.76 58.117 6.264 ;
     RECT  57.305 40.368 58.117 42.216 ;
     RECT  57.989 43.872 58.117 44.376 ;
     RECT  58.105 7.632 58.129 7.8 ;
     RECT  58.117 40.368 58.163 44.376 ;
     RECT  56.704 45.696 58.163 46.008 ;
     RECT  58.163 40.368 58.169 41.88 ;
     RECT  58.025 52.704 58.169 53.016 ;
     RECT  58.061 29.904 58.201 33.048 ;
     RECT  58.163 45.984 58.201 46.008 ;
     RECT  57.985 47.616 58.201 47.64 ;
     RECT  58.117 5.04 58.204 6.264 ;
     RECT  57.875 25.872 58.237 27.096 ;
     RECT  58.129 7.632 58.241 8.328 ;
     RECT  58.061 28.128 58.313 28.776 ;
     RECT  57.593 17.568 58.349 18.696 ;
     RECT  58.241 7.632 58.385 7.8 ;
     RECT  58.201 29.904 58.417 33.96 ;
     RECT  57.539 35.52 58.417 37.944 ;
     RECT  58.169 52.704 58.457 52.728 ;
     RECT  58.012 19.92 58.501 21.24 ;
     RECT  57.1 9.504 58.525 9.576 ;
     RECT  58.012 22.416 58.525 23.4 ;
     RECT  57.953 51.168 58.565 51.624 ;
     RECT  57.377 49.2 58.597 49.224 ;
     RECT  58.565 51.6 58.601 51.624 ;
     RECT  58.201 45.984 58.643 47.64 ;
     RECT  58.597 49.2 58.643 49.464 ;
     RECT  58.501 19.776 58.691 21.24 ;
     RECT  58.237 25.488 58.741 27.096 ;
     RECT  58.417 29.904 58.745 37.944 ;
     RECT  57.629 13.392 58.777 13.416 ;
     RECT  57.985 14.4 58.777 14.952 ;
     RECT  58.169 41.376 58.817 41.88 ;
     RECT  58.777 13.392 58.849 14.952 ;
     RECT  58.163 42.96 58.853 44.376 ;
     RECT  56.704 54.336 58.853 61.896 ;
     RECT  58.849 13.248 58.885 14.952 ;
     RECT  57.845 15.984 58.885 16.008 ;
     RECT  58.691 21.168 58.889 21.24 ;
     RECT  58.643 45.984 58.889 46.008 ;
     RECT  58.817 41.616 59.005 41.88 ;
     RECT  59.005 41.76 59.033 41.88 ;
     RECT  58.643 47.088 59.033 47.64 ;
     RECT  58.853 43.248 59.125 44.376 ;
     RECT  59.125 43.248 59.171 44.856 ;
     RECT  58.313 28.752 59.173 28.776 ;
     RECT  58.745 29.904 59.173 36.888 ;
     RECT  58.417 39.264 59.201 39.288 ;
     RECT  58.169 40.368 59.201 40.392 ;
     RECT  57.629 11.664 59.209 11.976 ;
     RECT  58.885 13.248 59.209 16.008 ;
     RECT  58.745 37.872 59.209 37.944 ;
     RECT  59.201 39.264 59.209 40.392 ;
     RECT  58.691 19.776 59.213 20.184 ;
     RECT  59.209 11.664 59.245 16.008 ;
     RECT  59.209 37.872 59.245 40.392 ;
     RECT  58.525 22.416 59.269 23.736 ;
     RECT  58.741 25.008 59.269 27.096 ;
     RECT  59.173 28.752 59.281 36.888 ;
     RECT  58.349 17.616 59.285 18.696 ;
     RECT  59.285 17.616 59.315 18.408 ;
     RECT  58.525 9.504 59.317 10.344 ;
     RECT  58.204 5.808 59.321 6.264 ;
     RECT  58.889 21.168 59.321 21.192 ;
     RECT  59.269 22.416 59.357 27.096 ;
     RECT  59.357 22.416 59.429 23.736 ;
     RECT  59.321 6.24 59.465 6.264 ;
     RECT  59.357 25.248 59.468 27.096 ;
     RECT  59.468 25.248 59.509 27.288 ;
     RECT  59.281 28.368 59.509 36.888 ;
     RECT  59.317 9.456 59.557 10.344 ;
     RECT  59.245 11.664 59.557 16.296 ;
     RECT  59.557 9.456 59.603 16.296 ;
     RECT  59.033 47.088 59.641 47.304 ;
     RECT  59.245 37.872 59.681 40.488 ;
     RECT  59.603 9.456 59.708 9.672 ;
     RECT  59.509 25.248 59.708 36.888 ;
     RECT  59.681 37.872 59.708 39 ;
     RECT  59.603 10.8 59.717 16.296 ;
     RECT  58.643 49.44 59.821 49.464 ;
     RECT  58.853 54.336 59.821 61.752 ;
     RECT  59.821 54.336 59.825 62.136 ;
     RECT  59.641 46.368 59.893 47.304 ;
     RECT  59.717 13.776 59.897 16.296 ;
     RECT  59.893 45.84 59.939 47.304 ;
     RECT  59.315 17.616 60.005 18.216 ;
     RECT  59.708 25.248 60.077 39 ;
     RECT  60.077 25.632 60.085 39 ;
     RECT  59.965 52.176 60.109 52.2 ;
     RECT  59.939 45.84 60.113 46.008 ;
     RECT  59.825 54.336 60.133 55.464 ;
     RECT  59.825 56.448 60.149 62.136 ;
     RECT  59.897 14.208 60.181 16.296 ;
     RECT  59.213 19.776 60.181 20.136 ;
     RECT  60.109 52.176 60.181 52.44 ;
     RECT  60.133 53.568 60.181 55.464 ;
     RECT  59.429 22.704 60.185 23.736 ;
     RECT  60.085 35.328 60.221 39 ;
     RECT  59.033 41.856 60.221 41.88 ;
     RECT  60.149 56.448 60.221 61.608 ;
     RECT  60.005 17.76 60.257 18.216 ;
     RECT  60.181 14.208 60.293 16.536 ;
     RECT  60.221 35.328 60.323 35.64 ;
     RECT  60.185 22.704 60.329 23.448 ;
     RECT  60.181 19.776 60.332 20.76 ;
     RECT  60.085 25.632 60.365 34.2 ;
     RECT  59.821 49.248 60.397 49.464 ;
     RECT  60.332 19.776 60.419 21.144 ;
     RECT  60.329 22.704 60.421 23.352 ;
     RECT  60.419 19.776 60.467 20.76 ;
     RECT  60.293 14.208 60.47 15.24 ;
     RECT  60.221 37.44 60.473 39 ;
     RECT  60.365 25.632 60.545 26.232 ;
     RECT  60.323 35.328 60.545 35.352 ;
     RECT  60.221 56.976 60.625 61.608 ;
     RECT  60.397 48.432 60.653 49.464 ;
     RECT  60.421 22.08 60.761 23.352 ;
     RECT  60.467 19.776 60.796 20.472 ;
     RECT  58.385 7.632 60.797 7.656 ;
     RECT  60.625 56.976 60.844 60.936 ;
     RECT  60.653 48.816 60.901 49.464 ;
     RECT  60.181 52.176 60.901 55.464 ;
     RECT  59.681 40.08 60.973 40.488 ;
     RECT  60.901 51.648 61.073 55.464 ;
     RECT  59.939 47.28 61.117 47.304 ;
     RECT  60.365 27.312 61.189 34.2 ;
     RECT  60.473 38.544 61.189 39 ;
     RECT  60.973 40.08 61.189 41.016 ;
     RECT  59.717 10.8 61.225 12.552 ;
     RECT  60.577 18.768 61.237 18.792 ;
     RECT  60.47 15.216 61.261 15.24 ;
     RECT  60.293 16.512 61.261 16.536 ;
     RECT  59.708 9.024 61.333 9.672 ;
     RECT  61.225 10.8 61.333 12.936 ;
     RECT  61.261 62.256 61.405 62.28 ;
     RECT  61.073 51.648 61.477 55.992 ;
     RECT  60.844 56.976 61.477 57.288 ;
     RECT  61.189 27.312 61.549 34.632 ;
     RECT  60.545 25.632 61.573 25.656 ;
     RECT  61.549 26.64 61.573 34.632 ;
     RECT  61.573 25.632 61.58 34.632 ;
     RECT  60.761 22.8 61.585 23.352 ;
     RECT  60.796 20.112 61.621 20.472 ;
     RECT  60.844 58.416 61.621 60.936 ;
     RECT  61.405 62.256 61.621 62.568 ;
     RECT  61.621 58.416 61.765 60.984 ;
     RECT  61.333 9.024 61.808 12.936 ;
     RECT  60.47 14.208 61.808 14.232 ;
     RECT  61.261 15.216 61.808 16.536 ;
     RECT  60.257 17.76 61.808 17.784 ;
     RECT  61.237 18.768 61.808 19.128 ;
     RECT  61.621 20.112 61.808 20.52 ;
     RECT  61.585 22.8 61.808 23.88 ;
     RECT  61.58 25.632 61.808 35.064 ;
     RECT  60.473 37.44 61.808 37.464 ;
     RECT  61.189 38.544 61.808 41.016 ;
     RECT  59.171 44.352 61.808 44.856 ;
     RECT  60.113 45.984 61.808 46.008 ;
     RECT  61.117 47.28 61.808 47.352 ;
     RECT  60.901 48.816 61.808 49.512 ;
     RECT  61.477 51.648 61.808 57.288 ;
     RECT  61.765 58.416 61.808 61.128 ;
     RECT  61.621 62.16 61.808 62.568 ;
     RECT  61.808 2.148 61.912 62.652 ;
     RECT  61.912 2.418 62.104 62.568 ;
     RECT  62.104 53.52 62.165 53.544 ;
     RECT  62.104 39.792 62.273 39.816 ;
     RECT  62.104 56.448 62.309 57.048 ;
     RECT  62.104 58.416 62.489 62.568 ;
     RECT  62.104 52.416 62.569 52.44 ;
     RECT  62.309 56.448 62.569 56.472 ;
     RECT  62.489 60.24 63.349 62.568 ;
     RECT  63.349 60.24 63.745 62.664 ;
     RECT  62.489 58.416 63.817 59.208 ;
     RECT  63.745 60.24 63.817 63.048 ;
     RECT  63.817 58.416 63.853 63.048 ;
     RECT  63.853 58.32 63.889 63.048 ;
     RECT  63.889 58.32 63.925 63.144 ;
     RECT  63.925 58.32 64.033 63.24 ;
     RECT  64.033 58.32 64.764 63.336 ;
    LAYER M5 ;
     RECT  2.4 2.137 2.52 2.151 ;
     RECT  7.8 2.137 7.92 2.151 ;
     RECT  13.2 2.137 13.32 2.151 ;
     RECT  18.6 2.137 18.72 2.151 ;
     RECT  24 2.137 24.12 2.151 ;
     RECT  29.4 2.137 29.52 2.151 ;
     RECT  34.8 2.137 34.92 2.151 ;
     RECT  40.2 2.137 40.32 2.151 ;
     RECT  45.6 2.137 45.72 2.151 ;
     RECT  51 2.137 51.12 2.151 ;
     RECT  56.4 2.137 56.52 2.151 ;
     RECT  61.8 2.137 61.92 2.151 ;
     RECT  42.384 2.245 42.408 2.629 ;
     RECT  18.6 2.151 18.912 2.725 ;
     RECT  31.248 2.725 31.272 2.821 ;
     RECT  45.6 2.151 45.912 2.869 ;
     RECT  31.248 2.821 31.32 2.963 ;
     RECT  51 2.151 51.312 3.157 ;
     RECT  25.872 2.245 25.896 3.205 ;
     RECT  55.056 2.245 55.08 3.205 ;
     RECT  56.4 2.151 56.712 3.205 ;
     RECT  25.872 3.205 26.808 3.251 ;
     RECT  52.368 2.869 52.392 3.397 ;
     RECT  45.12 2.869 45.912 3.445 ;
     RECT  24 2.151 24.312 3.685 ;
     RECT  40.2 2.151 40.512 3.685 ;
     RECT  41.568 2.629 42.408 3.685 ;
     RECT  55.056 3.205 56.712 3.827 ;
     RECT  52.368 3.397 52.776 3.875 ;
     RECT  44.352 3.445 45.912 3.877 ;
     RECT  26.784 3.251 26.808 4.115 ;
     RECT  40.2 3.685 42.408 4.115 ;
     RECT  18.6 2.725 19.176 4.309 ;
     RECT  18.6 4.309 20.136 4.355 ;
     RECT  9.12 2.629 9.144 4.403 ;
     RECT  31.248 2.963 31.272 4.403 ;
     RECT  15.36 2.677 15.384 4.405 ;
     RECT  15.36 4.405 15.624 4.501 ;
     RECT  23.376 3.685 24.312 4.547 ;
     RECT  55.488 3.827 56.712 4.595 ;
     RECT  34.8 2.151 35.112 4.837 ;
     RECT  34.512 4.837 35.112 5.077 ;
     RECT  37.632 3.925 37.656 5.123 ;
     RECT  52.752 3.875 52.776 5.123 ;
     RECT  44.352 3.877 46.152 5.219 ;
     RECT  40.2 4.115 41.592 5.413 ;
     RECT  45.12 5.219 46.152 5.701 ;
     RECT  5.76 2.821 5.784 5.747 ;
     RECT  14.688 4.501 15.624 5.747 ;
     RECT  17.088 4.549 17.112 5.747 ;
     RECT  45.12 5.701 46.92 5.747 ;
     RECT  7.8 2.151 8.112 5.749 ;
     RECT  50.736 3.157 51.312 5.795 ;
     RECT  58.128 5.029 58.152 5.797 ;
     RECT  20.112 4.355 20.136 5.941 ;
     RECT  21.168 4.261 21.192 5.941 ;
     RECT  11.184 4.261 11.208 5.987 ;
     RECT  20.112 5.941 21.192 5.987 ;
     RECT  22.272 4.789 22.296 5.987 ;
     RECT  29.4 2.151 29.712 5.989 ;
     RECT  34.512 5.077 35.208 6.131 ;
     RECT  52.944 5.173 52.968 6.181 ;
     RECT  43.344 4.501 43.368 6.229 ;
     RECT  55.536 4.595 56.712 6.229 ;
     RECT  43.344 6.229 43.8 6.275 ;
     RECT  58.032 5.797 58.152 6.275 ;
     RECT  40.2 5.413 41.784 6.323 ;
     RECT  15.6 5.747 15.624 6.515 ;
     RECT  18.6 4.355 18.912 6.661 ;
     RECT  43.776 6.275 43.8 6.661 ;
     RECT  45.12 5.747 45.912 6.661 ;
     RECT  34.8 6.131 35.208 6.805 ;
     RECT  9.84 5.893 9.864 6.851 ;
     RECT  58.032 6.275 58.056 6.899 ;
     RECT  2.4 2.151 2.712 7.189 ;
     RECT  7.8 5.749 8.472 7.189 ;
     RECT  52.944 6.181 53.16 7.235 ;
     RECT  17.856 6.661 18.912 7.237 ;
     RECT  50.832 5.795 51.312 7.333 ;
     RECT  26.4 6.229 26.424 7.379 ;
     RECT  40.2 6.323 40.776 7.381 ;
     RECT  6.72 6.805 6.744 7.427 ;
     RECT  20.544 5.987 21.192 7.475 ;
     RECT  52.944 7.235 53.016 7.475 ;
     RECT  55.488 6.229 56.712 7.765 ;
     RECT  20.832 7.475 21.192 7.957 ;
     RECT  2.4 7.189 3 8.003 ;
     RECT  52.992 7.475 53.016 8.003 ;
     RECT  33.216 3.973 33.24 8.195 ;
     RECT  17.808 7.237 18.912 8.387 ;
     RECT  34.8 6.805 35.496 8.437 ;
     RECT  34.704 8.437 35.496 8.483 ;
     RECT  46.896 5.747 46.92 8.483 ;
     RECT  24 4.547 24.312 8.485 ;
     RECT  39.36 7.381 40.776 8.531 ;
     RECT  43.776 6.661 45.912 8.533 ;
     RECT  7.8 7.189 9.336 8.579 ;
     RECT  43.296 8.533 45.912 8.579 ;
     RECT  7.8 8.579 8.472 8.723 ;
     RECT  49.536 6.517 49.56 8.723 ;
     RECT  40.2 8.531 40.776 8.821 ;
     RECT  55.488 7.765 57.048 8.869 ;
     RECT  54.672 8.869 57.048 9.011 ;
     RECT  7.8 8.723 8.112 9.061 ;
     RECT  43.296 8.579 43.8 9.107 ;
     RECT  48.336 6.661 48.36 9.109 ;
     RECT  50.736 7.333 51.312 9.155 ;
     RECT  18.192 8.387 18.912 9.347 ;
     RECT  55.488 9.011 57.048 9.395 ;
     RECT  43.728 9.107 43.8 9.491 ;
     RECT  59.76 9.013 59.784 9.493 ;
     RECT  24 8.485 24.504 9.637 ;
     RECT  20.832 7.957 22.152 9.683 ;
     RECT  59.28 9.493 59.784 9.683 ;
     RECT  7.44 9.061 8.112 9.781 ;
     RECT  52.656 9.061 52.68 9.923 ;
     RECT  15.648 6.805 15.672 9.925 ;
     RECT  34.704 8.483 35.112 10.067 ;
     RECT  7.2 9.781 8.112 10.069 ;
     RECT  55.488 9.395 56.712 10.165 ;
     RECT  61.8 2.151 62.112 10.213 ;
     RECT  18.48 9.347 18.912 10.307 ;
     RECT  23.376 9.637 24.504 10.307 ;
     RECT  33.072 9.061 33.096 10.307 ;
     RECT  37.632 9.637 37.656 10.307 ;
     RECT  40.2 8.821 41.4 10.307 ;
     RECT  48.336 9.109 49.032 10.355 ;
     RECT  59.28 9.683 59.592 10.355 ;
     RECT  34.8 10.067 35.112 10.453 ;
     RECT  50.832 9.155 51.312 10.549 ;
     RECT  2.4 8.003 2.712 10.597 ;
     RECT  2.4 10.597 2.904 10.645 ;
     RECT  43.728 9.491 43.752 10.741 ;
     RECT  6.528 10.069 8.112 10.789 ;
     RECT  9.216 10.357 9.24 10.789 ;
     RECT  30.96 10.021 30.984 10.835 ;
     RECT  6.528 10.789 9.24 10.883 ;
     RECT  11.952 9.925 11.976 10.883 ;
     RECT  59.568 10.355 59.592 10.883 ;
     RECT  24 10.307 24.504 10.979 ;
     RECT  50.736 10.549 51.312 11.029 ;
     RECT  7.2 10.883 9.24 11.171 ;
     RECT  2.4 10.645 3.24 11.269 ;
     RECT  61.344 10.213 62.112 11.269 ;
     RECT  18.6 10.307 18.912 11.317 ;
     RECT  54.96 10.165 56.712 11.317 ;
     RECT  5.088 9.061 5.112 11.365 ;
     RECT  48.768 10.355 49.032 11.459 ;
     RECT  54.96 11.317 57.096 11.651 ;
     RECT  45.216 8.579 45.912 11.653 ;
     RECT  47.28 10.885 47.304 11.653 ;
     RECT  55.488 11.651 57.096 11.699 ;
     RECT  15.648 9.925 15.96 11.843 ;
     RECT  13.2 2.151 13.512 11.941 ;
     RECT  34.8 10.453 36.072 11.941 ;
     RECT  43.728 10.741 43.848 11.941 ;
     RECT  45.216 11.653 47.304 11.941 ;
     RECT  42 11.029 42.024 11.987 ;
     RECT  43.728 11.941 47.304 12.035 ;
     RECT  61.152 11.269 62.112 12.035 ;
     RECT  7.8 11.171 9.24 12.179 ;
     RECT  48.768 11.459 48.792 12.325 ;
     RECT  56.016 11.699 57.096 12.325 ;
     RECT  43.728 12.035 46.728 12.467 ;
     RECT  13.104 11.941 13.512 12.517 ;
     RECT  18.48 11.317 18.912 12.517 ;
     RECT  31.008 11.317 31.032 12.563 ;
     RECT  43.824 12.467 46.728 12.563 ;
     RECT  5.088 11.365 5.544 12.755 ;
     RECT  34.8 11.941 36.168 12.755 ;
     RECT  13.104 12.517 13.656 12.899 ;
     RECT  43.872 12.563 46.728 12.899 ;
     RECT  56.016 12.325 57.576 12.901 ;
     RECT  34.8 12.755 36.072 13.043 ;
     RECT  44.784 12.899 46.728 13.043 ;
     RECT  24 10.979 24.312 13.045 ;
     RECT  48.624 12.325 48.792 13.045 ;
     RECT  50.736 11.029 52.008 13.091 ;
     RECT  48.624 13.045 49.032 13.141 ;
     RECT  20.832 9.683 21.192 13.187 ;
     RECT  54.672 13.045 54.696 13.187 ;
     RECT  32.928 13.093 32.952 13.235 ;
     RECT  48.624 13.141 49.128 13.331 ;
     RECT  55.872 12.901 57.576 13.667 ;
     RECT  10.224 12.853 10.248 13.715 ;
     RECT  24 13.045 24.504 13.715 ;
     RECT  26.112 13.093 26.136 13.715 ;
     RECT  55.872 13.667 56.904 13.715 ;
     RECT  2.4 11.269 3.432 13.717 ;
     RECT  28.8 5.989 29.712 13.813 ;
     RECT  15.648 11.843 15.672 13.859 ;
     RECT  21.168 13.187 21.192 13.859 ;
     RECT  50.736 13.091 51.312 13.859 ;
     RECT  54.144 13.525 54.168 13.859 ;
     RECT  28.512 13.813 29.712 13.955 ;
     RECT  2.4 13.717 3.96 14.197 ;
     RECT  5.088 12.755 5.112 14.197 ;
     RECT  2.4 14.197 5.112 14.243 ;
     RECT  59.28 13.621 59.304 14.245 ;
     RECT  59.28 14.245 59.784 14.291 ;
     RECT  2.4 14.243 4.728 14.579 ;
     RECT  30.96 13.045 30.984 14.627 ;
     RECT  40.2 10.307 40.776 14.629 ;
     RECT  42.144 12.853 42.168 14.629 ;
     RECT  44.784 13.043 46.008 14.629 ;
     RECT  25.632 14.197 25.656 14.773 ;
     RECT  16.08 14.101 16.104 14.821 ;
     RECT  18.096 12.517 18.912 14.821 ;
     RECT  25.632 14.773 26.232 14.915 ;
     RECT  3.936 14.579 4.728 15.011 ;
     RECT  9.216 12.179 9.24 15.013 ;
     RECT  50.88 13.859 51.312 15.059 ;
     RECT  11.712 11.413 11.736 15.061 ;
     RECT  11.712 15.061 11.832 15.155 ;
     RECT  13.2 12.899 13.656 15.205 ;
     RECT  49.104 13.331 49.128 15.299 ;
     RECT  15.888 14.821 16.104 15.349 ;
     RECT  28.8 13.955 29.712 15.443 ;
     RECT  47.568 14.677 47.592 15.443 ;
     RECT  59.76 14.291 59.784 15.587 ;
     RECT  15.888 15.349 16.296 15.637 ;
     RECT  24 13.715 24.312 15.637 ;
     RECT  15.888 15.637 17.016 15.683 ;
     RECT  9.216 15.013 9.912 15.875 ;
     RECT  11.808 15.155 11.832 15.875 ;
     RECT  56.016 13.715 56.904 15.877 ;
     RECT  44.784 14.629 46.488 15.973 ;
     RECT  4.704 15.011 4.728 16.019 ;
     RECT  13.104 15.205 13.656 16.019 ;
     RECT  40.2 14.629 42.168 16.019 ;
     RECT  43.968 15.973 46.488 16.019 ;
     RECT  61.296 12.035 62.112 16.019 ;
     RECT  14.688 15.493 14.712 16.259 ;
     RECT  59.712 15.637 59.736 16.307 ;
     RECT  18.096 14.821 19.128 16.405 ;
     RECT  26.208 14.915 26.232 16.451 ;
     RECT  16.08 15.683 17.016 16.501 ;
     RECT  18.096 16.405 19.656 16.501 ;
     RECT  23.568 15.637 24.312 16.501 ;
     RECT  49.824 15.829 49.848 16.549 ;
     RECT  40.2 16.019 41.304 16.595 ;
     RECT  47.52 15.493 47.544 16.595 ;
     RECT  55.104 15.877 56.904 16.595 ;
     RECT  23.568 16.501 24.408 16.643 ;
     RECT  49.056 16.549 49.848 16.787 ;
     RECT  13.2 16.019 13.656 16.835 ;
     RECT  43.968 16.019 45.912 16.835 ;
     RECT  54.096 15.061 54.12 16.933 ;
     RECT  21.888 14.773 21.912 17.075 ;
     RECT  54.096 16.933 54.696 17.075 ;
     RECT  34.8 13.043 35.112 17.125 ;
     RECT  32.16 16.501 32.184 17.317 ;
     RECT  16.08 16.501 19.656 17.363 ;
     RECT  31.632 17.317 32.184 17.459 ;
     RECT  13.2 16.835 13.512 17.461 ;
     RECT  56.016 16.595 56.904 17.461 ;
     RECT  20.784 14.485 20.808 17.605 ;
     RECT  56.016 17.461 57.192 17.605 ;
     RECT  52.8 16.837 52.824 17.651 ;
     RECT  23.568 16.643 24.312 17.699 ;
     RECT  59.28 17.605 59.304 18.037 ;
     RECT  20.592 17.605 20.808 18.085 ;
     RECT  51 15.059 51.312 18.181 ;
     RECT  20.592 18.085 21.432 18.227 ;
     RECT  54.096 17.075 54.12 18.275 ;
     RECT  58.512 18.037 59.304 18.419 ;
     RECT  6.144 18.037 6.168 18.707 ;
     RECT  7.8 12.179 8.112 18.757 ;
     RECT  9.216 15.875 9.24 18.757 ;
     RECT  50.736 18.181 51.312 18.757 ;
     RECT  53.04 18.037 53.064 18.757 ;
     RECT  55.344 17.605 57.192 18.757 ;
     RECT  61.344 16.019 62.112 18.757 ;
     RECT  16.08 17.363 19.128 18.851 ;
     RECT  42.144 18.133 42.168 18.851 ;
     RECT  54.672 18.757 57.192 18.851 ;
     RECT  14.928 16.453 14.952 18.947 ;
     RECT  49.056 16.787 49.08 18.995 ;
     RECT  50.736 18.757 53.064 18.995 ;
     RECT  7.8 18.757 9.24 19.093 ;
     RECT  56.016 18.851 57.192 19.141 ;
     RECT  29.4 15.443 29.712 19.237 ;
     RECT  44.688 16.835 45.912 19.237 ;
     RECT  20.592 18.227 21.336 19.283 ;
     RECT  43.68 18.661 43.704 19.379 ;
     RECT  44.688 19.237 46.008 19.381 ;
     RECT  12.816 17.461 13.512 19.427 ;
     RECT  58.512 18.419 58.536 19.765 ;
     RECT  60.72 18.757 62.112 19.765 ;
     RECT  58.512 19.765 58.68 19.811 ;
     RECT  47.856 19.093 47.88 19.909 ;
     RECT  7.8 19.093 9.864 19.955 ;
     RECT  17.136 18.851 19.128 19.955 ;
     RECT  47.856 19.909 48.408 20.101 ;
     RECT  20.784 19.283 21.336 20.339 ;
     RECT  40.2 16.595 40.776 20.341 ;
     RECT  51 18.995 53.064 20.435 ;
     RECT  54.672 18.851 54.696 20.485 ;
     RECT  33.168 18.037 33.192 20.579 ;
     RECT  47.856 20.101 48.936 20.579 ;
     RECT  58.656 19.811 58.68 20.579 ;
     RECT  37.296 19.621 37.32 20.581 ;
     RECT  51 20.435 51.312 20.629 ;
     RECT  54.528 20.485 54.696 20.965 ;
     RECT  56.016 19.141 57.432 20.965 ;
     RECT  13.2 19.427 13.512 21.013 ;
     RECT  24 17.699 24.312 21.013 ;
     RECT  47.856 20.579 47.88 21.059 ;
     RECT  7.8 19.955 9.24 21.061 ;
     RECT  44.688 19.381 46.632 21.061 ;
     RECT  16.08 18.851 16.104 21.107 ;
     RECT  25.392 19.909 25.416 21.107 ;
     RECT  12.528 21.013 13.512 21.109 ;
     RECT  34.8 17.125 35.208 21.155 ;
     RECT  37.296 20.581 37.656 21.155 ;
     RECT  60.384 19.765 62.112 21.155 ;
     RECT  53.04 20.435 53.064 21.349 ;
     RECT  44.688 21.061 46.68 21.395 ;
     RECT  53.04 21.349 53.4 21.395 ;
     RECT  20.784 20.339 20.808 21.493 ;
     RECT  20.544 21.493 20.808 21.779 ;
     RECT  48.912 20.579 48.936 21.877 ;
     RECT  12.288 21.109 13.512 21.923 ;
     RECT  48.48 21.877 48.936 21.923 ;
     RECT  50.832 20.629 51.312 21.923 ;
     RECT  7.8 21.061 10.152 21.971 ;
     RECT  53.376 21.395 53.4 21.971 ;
     RECT  44.688 21.395 46.104 22.021 ;
     RECT  54.528 20.965 57.432 22.069 ;
     RECT  5.664 18.757 5.688 22.117 ;
     RECT  31.152 21.637 31.176 22.165 ;
     RECT  32.16 17.459 32.184 22.165 ;
     RECT  31.152 22.165 32.184 22.211 ;
     RECT  5.664 22.117 6.408 22.259 ;
     RECT  44.064 22.021 46.104 22.453 ;
     RECT  44.064 22.453 46.152 22.741 ;
     RECT  54.528 22.069 57.96 22.789 ;
     RECT  23.424 21.013 24.312 22.835 ;
     RECT  54.528 22.789 58.728 22.931 ;
     RECT  54.528 22.931 57.96 23.075 ;
     RECT  20.544 21.779 20.568 23.125 ;
     RECT  60.432 21.155 62.112 23.171 ;
     RECT  6.384 22.259 6.408 23.219 ;
     RECT  27.936 21.637 27.96 23.315 ;
     RECT  20.544 23.125 21.096 23.317 ;
     RECT  43.632 22.741 46.152 23.317 ;
     RECT  25.632 21.637 25.656 23.411 ;
     RECT  54.72 23.075 57.96 23.411 ;
     RECT  54.72 23.411 57.528 23.891 ;
     RECT  2.4 14.579 2.712 23.893 ;
     RECT  34.8 21.155 35.112 23.941 ;
     RECT  31.296 22.211 32.184 23.987 ;
     RECT  43.632 23.317 46.344 23.987 ;
     RECT  2.4 23.893 3.192 24.179 ;
     RECT  34.176 23.941 35.112 24.227 ;
     RECT  44.064 23.987 46.344 24.371 ;
     RECT  37.632 21.155 37.656 24.515 ;
     RECT  29.4 19.237 29.928 24.659 ;
     RECT  56.016 23.891 57.528 24.659 ;
     RECT  4.128 24.181 4.152 24.899 ;
     RECT  45.6 24.371 46.344 24.899 ;
     RECT  50.88 21.923 51.312 24.899 ;
     RECT  17.184 19.955 19.128 25.045 ;
     RECT  20.256 23.317 21.096 25.045 ;
     RECT  9.216 21.971 10.152 25.139 ;
     RECT  9.312 25.139 10.152 25.141 ;
     RECT  17.088 25.045 21.096 25.187 ;
     RECT  9.312 25.141 10.248 25.285 ;
     RECT  18.048 25.187 21.096 25.477 ;
     RECT  44.064 24.371 44.088 25.573 ;
     RECT  18.048 25.477 21.432 25.619 ;
     RECT  48.48 21.923 48.504 25.621 ;
     RECT  52.992 23.845 53.016 25.621 ;
     RECT  52.992 25.621 53.592 25.811 ;
     RECT  56.016 24.659 57 26.101 ;
     RECT  40.2 20.341 41.208 26.147 ;
     RECT  24 22.835 24.312 26.197 ;
     RECT  44.064 25.573 44.184 26.197 ;
     RECT  15.36 22.741 15.384 26.243 ;
     RECT  59.28 23.317 59.304 26.243 ;
     RECT  45.6 24.899 46.248 26.291 ;
     RECT  53.568 25.811 53.592 26.581 ;
     RECT  54.72 23.891 54.744 26.581 ;
     RECT  2.4 24.179 2.712 26.629 ;
     RECT  53.568 26.581 54.744 26.675 ;
     RECT  34.8 24.227 35.112 26.677 ;
     RECT  9.312 25.285 10.584 26.773 ;
     RECT  36.576 24.469 36.6 26.821 ;
     RECT  43.968 26.197 44.184 27.059 ;
     RECT  24 26.197 24.6 27.203 ;
     RECT  53.568 26.675 54.456 27.205 ;
     RECT  7.8 21.971 8.112 27.301 ;
     RECT  9.312 26.773 10.824 27.301 ;
     RECT  29.4 24.659 29.712 27.301 ;
     RECT  45.6 26.291 46.008 27.301 ;
     RECT  51 24.899 51.312 27.301 ;
     RECT  52.992 27.205 54.456 27.347 ;
     RECT  14.928 26.437 14.952 27.443 ;
     RECT  50.592 27.301 51.312 27.635 ;
     RECT  18.048 25.619 21.096 27.875 ;
     RECT  36.24 26.821 36.6 27.875 ;
     RECT  48.48 25.621 48.552 27.875 ;
     RECT  18.048 27.875 19.368 27.877 ;
     RECT  41.952 26.629 41.976 27.877 ;
     RECT  52.992 27.347 53.016 27.877 ;
     RECT  41.952 27.877 42.408 27.923 ;
     RECT  21.072 27.875 21.096 27.971 ;
     RECT  54.432 27.347 54.456 27.971 ;
     RECT  7.8 27.301 10.824 28.019 ;
     RECT  29.4 27.301 30.168 28.115 ;
     RECT  7.8 28.019 8.112 28.117 ;
     RECT  9.312 28.019 10.824 28.163 ;
     RECT  7.68 28.117 8.112 28.259 ;
     RECT  42.384 27.923 42.408 28.259 ;
     RECT  32.16 23.987 32.184 28.309 ;
     RECT  59.52 26.677 59.544 28.403 ;
     RECT  34.56 26.677 35.112 28.451 ;
     RECT  48.48 27.875 48.504 28.451 ;
     RECT  45.6 27.301 46.2 28.453 ;
     RECT  45.6 28.453 46.296 28.549 ;
     RECT  40.2 26.147 40.776 28.789 ;
     RECT  36.576 27.875 36.6 28.933 ;
     RECT  13.2 21.923 13.512 29.077 ;
     RECT  32.16 28.309 33.048 29.123 ;
     RECT  2.4 26.629 2.904 29.219 ;
     RECT  34.704 28.451 35.112 29.267 ;
     RECT  43.968 27.059 44.088 29.365 ;
     RECT  52.368 27.877 53.016 29.507 ;
     RECT  24 27.203 24.312 29.509 ;
     RECT  23.376 29.509 24.312 29.557 ;
     RECT  36.384 28.933 36.6 29.605 ;
     RECT  40.2 28.789 41.352 29.605 ;
     RECT  54.576 28.165 54.6 29.699 ;
     RECT  59.28 28.933 59.304 29.747 ;
     RECT  48.144 29.029 48.168 29.893 ;
     RECT  50.688 27.635 51.312 29.893 ;
     RECT  29.4 28.115 29.712 30.181 ;
     RECT  32.16 29.123 32.184 30.181 ;
     RECT  43.872 29.365 44.088 30.227 ;
     RECT  48.144 29.893 48.552 30.227 ;
     RECT  31.248 30.181 32.184 30.229 ;
     RECT  40.032 29.605 41.352 30.275 ;
     RECT  17.232 27.877 19.368 30.323 ;
     RECT  34.8 29.267 35.112 30.421 ;
     RECT  56.016 26.101 57.864 30.517 ;
     RECT  56.016 30.517 58.008 30.563 ;
     RECT  36.384 29.605 36.888 30.709 ;
     RECT  56.016 30.563 57 30.757 ;
     RECT  13.2 29.077 13.848 30.803 ;
     RECT  6.048 28.789 6.072 30.851 ;
     RECT  40.032 30.275 40.632 30.851 ;
     RECT  55.296 30.757 57 30.853 ;
     RECT  15.408 27.973 15.432 30.949 ;
     RECT  27.408 30.085 27.432 30.949 ;
     RECT  50.016 29.893 51.312 30.995 ;
     RECT  52.368 29.507 52.392 30.995 ;
     RECT  29.136 30.181 29.712 30.997 ;
     RECT  31.248 30.229 32.952 31.139 ;
     RECT  27.408 30.949 27.672 31.187 ;
     RECT  31.248 31.139 32.472 31.187 ;
     RECT  20.352 30.181 20.376 31.237 ;
     RECT  20.352 31.237 20.52 31.283 ;
     RECT  5.568 30.997 5.592 31.285 ;
     RECT  29.136 30.997 30.216 31.333 ;
     RECT  45.6 28.549 46.728 31.333 ;
     RECT  23.376 29.557 24.408 31.379 ;
     RECT  36.384 30.709 36.936 31.379 ;
     RECT  48.528 30.227 48.552 31.379 ;
     RECT  50.688 30.995 51.312 31.379 ;
     RECT  15.408 30.949 16.344 31.381 ;
     RECT  2.4 29.219 2.712 31.525 ;
     RECT  36.912 31.379 36.936 31.619 ;
     RECT  57.984 30.563 58.008 31.667 ;
     RECT  14.832 31.381 16.344 31.715 ;
     RECT  40.2 30.851 40.632 31.765 ;
     RECT  44.064 30.227 44.088 31.765 ;
     RECT  45.6 31.333 46.776 31.765 ;
     RECT  44.064 31.765 46.776 31.811 ;
     RECT  13.2 30.803 13.608 31.813 ;
     RECT  7.8 28.259 8.112 31.861 ;
     RECT  27.648 31.187 27.672 31.861 ;
     RECT  29.136 31.333 30.648 31.861 ;
     RECT  15.408 31.715 16.344 31.955 ;
     RECT  31.968 31.187 32.472 31.955 ;
     RECT  42.144 30.709 42.168 31.955 ;
     RECT  54.336 30.853 57 31.955 ;
     RECT  60.096 30.181 60.12 31.955 ;
     RECT  24 31.379 24.408 31.957 ;
     RECT  20.496 31.283 20.52 32.003 ;
     RECT  2.4 31.525 3.432 32.051 ;
     RECT  6.864 31.861 8.112 32.099 ;
     RECT  27.648 31.861 30.648 32.195 ;
     RECT  47.904 32.437 47.928 32.869 ;
     RECT  15.408 31.955 15.432 32.965 ;
     RECT  24 31.957 24.456 32.965 ;
     RECT  28.464 32.195 30.648 33.011 ;
     RECT  40.2 31.765 41.064 33.013 ;
     RECT  42.912 32.437 42.936 33.013 ;
     RECT  44.064 31.811 45.912 33.013 ;
     RECT  51 31.379 51.312 33.013 ;
     RECT  31.968 31.955 32.184 33.107 ;
     RECT  18.048 30.323 19.368 33.539 ;
     RECT  18.384 33.539 19.368 33.541 ;
     RECT  51 33.013 51.48 33.541 ;
     RECT  12.288 31.813 13.608 33.589 ;
     RECT  56.016 31.955 57 33.589 ;
     RECT  54.336 31.955 54.36 33.635 ;
     RECT  40.2 33.013 41.736 33.683 ;
     RECT  47.568 32.869 47.928 33.683 ;
     RECT  22.032 31.909 22.056 33.731 ;
     RECT  59.232 33.013 59.256 33.781 ;
     RECT  59.232 33.781 60.024 33.827 ;
     RECT  32.16 33.107 32.184 33.973 ;
     RECT  49.056 32.437 49.608 34.115 ;
     RECT  41.712 33.683 41.736 34.163 ;
     RECT  5.088 31.285 5.592 34.165 ;
     RECT  34.8 30.421 35.208 34.259 ;
     RECT  49.056 34.115 49.08 34.259 ;
     RECT  24 32.965 25.224 34.355 ;
     RECT  55.872 33.589 57 34.355 ;
     RECT  15.408 32.965 15.48 34.403 ;
     RECT  40.2 33.683 40.512 34.597 ;
     RECT  60 33.827 60.024 34.643 ;
     RECT  39.264 34.597 40.512 34.741 ;
     RECT  38.352 34.741 40.512 34.931 ;
     RECT  50.88 33.541 51.48 35.125 ;
     RECT  12.288 33.589 13.656 35.171 ;
     RECT  18.384 33.541 20.184 35.317 ;
     RECT  18 35.317 20.184 35.365 ;
     RECT  36.864 33.637 36.888 35.411 ;
     RECT  42.912 33.013 45.912 35.603 ;
     RECT  60.048 34.741 60.072 35.605 ;
     RECT  32.16 33.973 33.048 35.845 ;
     RECT  58.944 35.701 58.968 35.845 ;
     RECT  18 35.365 20.76 35.987 ;
     RECT  20.736 35.987 20.76 35.989 ;
     RECT  53.568 33.637 53.592 36.229 ;
     RECT  50.88 35.125 52.056 36.275 ;
     RECT  24 34.355 24.408 36.277 ;
     RECT  44.064 35.603 45.912 36.277 ;
     RECT  56.016 34.355 57 36.277 ;
     RECT  38.448 34.931 40.512 36.373 ;
     RECT  48.576 35.077 48.6 36.373 ;
     RECT  53.328 36.229 53.592 36.515 ;
     RECT  58.464 35.845 58.968 36.517 ;
     RECT  60.048 35.605 60.312 36.517 ;
     RECT  44.064 36.277 46.008 36.563 ;
     RECT  25.68 35.941 25.704 36.755 ;
     RECT  51 36.275 52.056 36.755 ;
     RECT  9.312 28.163 10.68 36.757 ;
     RECT  55.248 36.277 57 36.803 ;
     RECT  18 35.987 19.368 36.901 ;
     RECT  20.736 35.989 20.808 36.997 ;
     RECT  42.912 35.603 42.936 36.997 ;
     RECT  20.64 36.997 20.808 37.091 ;
     RECT  22.8 36.901 22.824 37.091 ;
     RECT  38.448 36.373 40.776 37.091 ;
     RECT  58.464 36.517 60.312 37.091 ;
     RECT  48.576 36.373 49.032 37.139 ;
     RECT  41.808 35.557 41.832 37.235 ;
     RECT  47.568 33.683 47.592 37.331 ;
     RECT  56.016 36.803 57 37.429 ;
     RECT  56.016 37.429 57.528 37.667 ;
     RECT  15.408 34.403 15.432 37.813 ;
     RECT  56.256 37.667 57.528 37.859 ;
     RECT  51 36.755 51.312 37.861 ;
     RECT  15.408 37.813 15.672 38.005 ;
     RECT  42.912 36.997 43.032 38.149 ;
     RECT  20.64 37.091 20.664 38.195 ;
     RECT  9.312 36.757 10.872 38.243 ;
     RECT  17.424 36.901 19.368 38.243 ;
     RECT  51 37.861 51.48 38.435 ;
     RECT  58.944 37.091 60.312 38.435 ;
     RECT  38.448 37.091 40.68 38.483 ;
     RECT  48.576 37.139 48.6 38.675 ;
     RECT  42.768 38.149 43.032 38.677 ;
     RECT  5.04 34.165 5.592 38.819 ;
     RECT  28.464 33.011 29.712 38.819 ;
     RECT  29.4 38.819 29.712 38.917 ;
     RECT  60.288 38.435 60.312 39.011 ;
     RECT  29.4 38.917 30.072 39.013 ;
     RECT  47.328 38.101 47.352 39.061 ;
     RECT  24 36.277 24.504 39.107 ;
     RECT  34.8 34.259 35.112 39.205 ;
     RECT  24 39.107 24.408 39.253 ;
     RECT  27.36 37.429 27.384 39.299 ;
     RECT  51 38.435 51.312 39.301 ;
     RECT  56.4 37.859 57.528 39.347 ;
     RECT  54.144 37.189 54.168 39.443 ;
     RECT  44.064 36.563 45.912 39.539 ;
     RECT  12.288 35.171 13.512 39.779 ;
     RECT  39.312 38.483 40.68 39.877 ;
     RECT  29.4 39.013 30.12 39.923 ;
     RECT  58.944 38.435 59.256 39.923 ;
     RECT  42.432 38.677 43.032 39.971 ;
     RECT  7.8 32.099 8.112 40.021 ;
     RECT  61.344 23.171 62.112 40.069 ;
     RECT  23.136 39.253 24.408 40.163 ;
     RECT  32.16 35.845 33.384 40.165 ;
     RECT  58.944 39.923 58.968 40.357 ;
     RECT  15.12 38.005 15.672 40.453 ;
     RECT  17.424 38.243 18.912 40.453 ;
     RECT  15.12 40.453 18.912 40.499 ;
     RECT  44.064 39.539 44.472 40.549 ;
     RECT  45.6 39.539 45.912 40.549 ;
     RECT  47.184 39.061 47.352 40.595 ;
     RECT  24 40.163 24.408 40.643 ;
     RECT  6.816 40.021 8.232 40.835 ;
     RECT  32.16 40.165 33.528 40.979 ;
     RECT  34.8 39.205 35.208 40.979 ;
     RECT  38.16 40.021 38.184 40.981 ;
     RECT  39.312 39.877 40.776 40.981 ;
     RECT  61.008 40.069 62.112 41.027 ;
     RECT  29.4 39.923 29.712 41.029 ;
     RECT  32.16 40.979 33.384 41.075 ;
     RECT  42.912 39.971 43.032 41.221 ;
     RECT  38.16 40.981 40.776 41.267 ;
     RECT  49.152 40.981 49.176 41.557 ;
     RECT  5.04 38.819 5.064 41.651 ;
     RECT  6.816 40.835 8.112 41.651 ;
     RECT  28.464 41.029 29.712 41.651 ;
     RECT  31.008 40.309 31.032 41.651 ;
     RECT  38.16 41.267 40.68 41.651 ;
     RECT  47.328 40.595 47.352 41.651 ;
     RECT  49.152 41.557 49.416 41.651 ;
     RECT  58.704 40.357 58.968 41.651 ;
     RECT  13.2 39.779 13.512 41.701 ;
     RECT  16.464 40.499 18.912 41.701 ;
     RECT  16.368 41.701 18.912 41.747 ;
     RECT  13.056 41.701 13.512 41.797 ;
     RECT  38.16 41.651 40.512 42.227 ;
     RECT  56.4 39.347 57.096 42.227 ;
     RECT  24 40.643 24.312 42.325 ;
     RECT  7.8 41.651 8.112 42.565 ;
     RECT  21.072 42.421 21.096 42.709 ;
     RECT  32.16 41.075 32.856 42.709 ;
     RECT  47.568 42.133 47.592 42.709 ;
     RECT  49.392 41.651 49.416 42.709 ;
     RECT  47.568 42.709 49.416 42.803 ;
     RECT  29.4 41.651 29.712 42.853 ;
     RECT  9.312 38.243 10.68 42.901 ;
     RECT  58.128 42.133 58.152 42.995 ;
     RECT  17.568 41.747 18.912 42.997 ;
     RECT  36.768 38.149 36.792 42.997 ;
     RECT  38.16 42.227 39.048 42.997 ;
     RECT  21.072 42.709 21.672 43.045 ;
     RECT  40.2 42.227 40.512 43.141 ;
     RECT  9.312 42.901 10.872 43.187 ;
     RECT  20.736 43.045 21.672 43.187 ;
     RECT  31.584 42.709 32.856 43.285 ;
     RECT  44.064 40.549 45.912 43.331 ;
     RECT  36.096 42.997 39.048 43.571 ;
     RECT  7.8 42.565 8.232 43.573 ;
     RECT  9.312 43.187 10.68 43.573 ;
     RECT  36.24 43.571 39.048 43.763 ;
     RECT  34.8 40.979 35.112 43.861 ;
     RECT  16.368 41.747 16.488 44.051 ;
     RECT  48.528 42.803 48.552 44.051 ;
     RECT  17.568 42.997 19.032 44.195 ;
     RECT  31.584 43.285 33.336 44.195 ;
     RECT  37.488 43.763 39.048 44.245 ;
     RECT  40.2 43.141 40.68 44.245 ;
     RECT  61.344 41.027 62.112 44.341 ;
     RECT  29.4 42.853 30.6 44.435 ;
     RECT  32.832 44.195 33.336 44.483 ;
     RECT  37.488 44.245 40.68 44.627 ;
     RECT  42.48 41.221 43.032 44.723 ;
     RECT  24 42.325 24.456 44.773 ;
     RECT  31.584 44.195 31.608 44.867 ;
     RECT  59.136 41.845 59.16 44.867 ;
     RECT  17.568 44.195 18.912 44.869 ;
     RECT  34.704 43.861 35.112 44.915 ;
     RECT  44.064 43.331 44.472 44.915 ;
     RECT  45.504 43.331 45.912 44.915 ;
     RECT  38.112 44.627 40.68 44.965 ;
     RECT  25.536 43.285 25.56 45.059 ;
     RECT  12.24 41.797 13.512 45.155 ;
     RECT  21.648 43.187 21.672 45.155 ;
     RECT  38.112 44.965 40.872 45.205 ;
     RECT  44.064 44.915 44.088 45.205 ;
     RECT  42.48 44.723 42.936 45.251 ;
     RECT  7.8 43.573 10.68 45.349 ;
     RECT  7.8 45.349 10.872 45.539 ;
     RECT  34.8 44.915 35.112 45.541 ;
     RECT  45.6 44.915 45.912 45.541 ;
     RECT  56.4 42.227 56.712 45.541 ;
     RECT  7.8 45.539 10.68 45.587 ;
     RECT  32.832 44.483 32.856 45.587 ;
     RECT  48.48 44.965 48.504 45.683 ;
     RECT  58.128 44.341 58.152 45.731 ;
     RECT  45.6 45.541 46.008 45.877 ;
     RECT  38.112 45.205 41.112 45.971 ;
     RECT  61.056 44.341 62.112 46.019 ;
     RECT  16.848 44.869 18.912 46.021 ;
     RECT  13.104 45.155 13.512 46.067 ;
     RECT  56.304 45.541 56.712 46.067 ;
     RECT  13.2 46.067 13.512 46.069 ;
     RECT  40.2 45.971 41.112 46.211 ;
     RECT  43.968 45.205 44.088 46.259 ;
     RECT  24 44.773 24.552 46.261 ;
     RECT  15.12 40.499 15.144 46.501 ;
     RECT  40.2 46.211 40.872 46.595 ;
     RECT  13.2 46.069 13.608 46.739 ;
     RECT  16.848 46.021 19.656 46.741 ;
     RECT  50.496 39.301 51.312 46.741 ;
     RECT  15.12 46.501 15.192 46.789 ;
     RECT  15.12 46.789 15.384 46.931 ;
     RECT  45.6 45.877 46.92 47.123 ;
     RECT  9.312 45.587 10.68 47.173 ;
     RECT  13.2 46.739 13.512 47.173 ;
     RECT  59.904 45.829 59.928 47.315 ;
     RECT  16.8 46.741 19.656 47.317 ;
     RECT  34.8 45.541 35.208 47.317 ;
     RECT  36.24 43.763 36.264 47.317 ;
     RECT  24 46.261 25.176 47.363 ;
     RECT  61.344 46.019 62.112 47.363 ;
     RECT  38.112 45.971 39.048 47.411 ;
     RECT  16.8 47.317 20.28 47.653 ;
     RECT  34.8 47.317 36.264 47.749 ;
     RECT  38.112 47.411 39 47.749 ;
     RECT  42.912 45.251 42.936 47.749 ;
     RECT  44.064 46.259 44.088 47.749 ;
     RECT  21.408 47.077 21.432 47.845 ;
     RECT  29.4 44.435 29.712 47.845 ;
     RECT  37.824 47.749 39 47.891 ;
     RECT  55.296 45.541 55.32 47.891 ;
     RECT  15.12 46.931 15.336 47.893 ;
     RECT  16.512 47.653 20.28 47.893 ;
     RECT  56.4 46.067 56.712 47.941 ;
     RECT  15.12 47.893 20.28 48.133 ;
     RECT  21.408 47.845 21.672 48.133 ;
     RECT  56.4 47.941 56.856 48.133 ;
     RECT  15.12 48.133 21.672 48.323 ;
     RECT  17.04 48.323 21.672 48.371 ;
     RECT  15.12 48.323 16.008 48.421 ;
     RECT  45.6 47.123 46.008 48.421 ;
     RECT  14.928 48.421 16.008 48.467 ;
     RECT  49.92 46.741 51.312 48.467 ;
     RECT  9.312 47.173 11.256 48.515 ;
     RECT  42.912 47.749 44.088 48.515 ;
     RECT  29.4 47.845 30.264 48.757 ;
     RECT  34.8 47.749 36.312 48.803 ;
     RECT  61.68 47.363 62.112 48.805 ;
     RECT  27.312 48.421 27.336 48.901 ;
     RECT  56.256 48.133 56.856 48.949 ;
     RECT  13.104 47.173 13.512 48.997 ;
     RECT  17.04 48.371 20.328 49.043 ;
     RECT  24 47.363 24.504 49.043 ;
     RECT  13.008 48.997 13.512 49.045 ;
     RECT  13.008 49.045 13.656 49.139 ;
     RECT  45.6 48.421 46.824 49.235 ;
     RECT  34.8 48.803 36.264 49.283 ;
     RECT  21.648 48.371 21.672 49.331 ;
     RECT  29.4 48.757 30.6 49.475 ;
     RECT  58.608 46.693 58.632 49.475 ;
     RECT  60.912 48.805 62.112 49.523 ;
     RECT  38.112 47.891 39 49.619 ;
     RECT  44.064 48.515 44.088 49.619 ;
     RECT  50.16 48.467 51.312 49.715 ;
     RECT  42.912 48.515 42.936 49.765 ;
     RECT  14.928 48.467 15.336 49.813 ;
     RECT  56.256 48.949 56.904 50.053 ;
     RECT  14.88 49.813 15.336 50.197 ;
     RECT  17.568 49.043 20.328 50.437 ;
     RECT  4.752 44.389 4.776 50.531 ;
     RECT  26.736 48.901 27.336 50.533 ;
     RECT  26.208 50.533 27.336 50.579 ;
     RECT  42.816 49.765 42.936 50.629 ;
     RECT  14.88 50.197 15.384 50.677 ;
     RECT  34.8 49.283 36.072 50.821 ;
     RECT  33.648 50.101 33.672 50.867 ;
     RECT  41.856 50.629 43.416 50.867 ;
     RECT  16.704 50.437 20.328 50.917 ;
     RECT  48.672 50.389 48.696 50.965 ;
     RECT  48.672 50.965 49.08 51.109 ;
     RECT  16.704 50.917 21.048 51.203 ;
     RECT  38.976 49.619 39 51.205 ;
     RECT  22.8 50.917 22.824 51.253 ;
     RECT  38.688 51.205 39 51.253 ;
     RECT  45.6 49.235 46.056 51.253 ;
     RECT  22.656 51.253 22.824 51.541 ;
     RECT  24 49.043 24.456 51.541 ;
     RECT  29.4 49.475 29.712 51.637 ;
     RECT  40.2 46.595 40.512 51.637 ;
     RECT  14.736 50.677 15.384 51.685 ;
     RECT  16.704 51.203 20.328 51.779 ;
     RECT  14.736 51.685 15.528 51.827 ;
     RECT  52.656 50.149 52.68 51.875 ;
     RECT  17.568 51.779 20.328 51.923 ;
     RECT  41.856 50.867 42.936 51.923 ;
     RECT  12.096 51.877 12.12 51.973 ;
     RECT  22.656 51.541 24.456 51.973 ;
     RECT  2.4 32.051 2.712 52.021 ;
     RECT  12.048 51.973 12.12 52.115 ;
     RECT  22.656 51.973 25.128 52.163 ;
     RECT  45.6 51.253 46.824 52.163 ;
     RECT  26.208 50.579 26.232 52.211 ;
     RECT  18.288 51.923 20.328 52.213 ;
     RECT  7.8 45.587 8.112 52.261 ;
     RECT  32.496 52.069 32.52 52.261 ;
     RECT  56.16 50.053 56.904 52.355 ;
     RECT  12.096 52.115 12.12 52.403 ;
     RECT  5.952 50.485 5.976 52.405 ;
     RECT  61.8 49.523 62.112 52.405 ;
     RECT  5.952 52.405 6.216 52.451 ;
     RECT  7.68 52.261 8.112 52.451 ;
     RECT  22.656 52.163 24.456 52.499 ;
     RECT  27.312 50.579 27.336 52.499 ;
     RECT  28.464 51.637 29.712 52.499 ;
     RECT  38.064 51.253 39 52.693 ;
     RECT  13.104 49.139 13.656 52.741 ;
     RECT  45.6 52.163 46.728 52.789 ;
     RECT  6.192 52.451 6.216 52.837 ;
     RECT  29.4 52.499 29.712 52.981 ;
     RECT  40.08 51.637 40.512 52.981 ;
     RECT  42.816 51.923 42.936 52.981 ;
     RECT  31.632 52.261 32.52 53.075 ;
     RECT  56.4 52.355 56.904 53.075 ;
     RECT  4.512 52.357 4.536 53.363 ;
     RECT  14.736 51.827 15.384 53.363 ;
     RECT  61.8 52.405 62.52 53.413 ;
     RECT  29.4 52.981 29.832 53.509 ;
     RECT  31.632 53.075 31.656 53.509 ;
     RECT  61.584 53.413 62.52 53.509 ;
     RECT  18.288 52.213 21.24 53.557 ;
     RECT  34.704 50.821 36.072 53.557 ;
     RECT  38.064 52.693 39.048 53.557 ;
     RECT  40.08 52.981 40.824 53.557 ;
     RECT  44.784 52.789 46.728 53.557 ;
     RECT  18.24 53.557 21.24 53.603 ;
     RECT  52.608 52.021 52.632 53.603 ;
     RECT  28.224 53.077 28.248 53.651 ;
     RECT  44.784 53.557 47.064 53.651 ;
     RECT  18.24 53.603 21.192 53.795 ;
     RECT  44.784 53.651 46.056 53.891 ;
     RECT  50.208 49.715 51.312 53.939 ;
     RECT  60.144 53.557 60.168 53.941 ;
     RECT  61.2 53.509 62.52 53.941 ;
     RECT  22.656 52.499 22.68 54.085 ;
     RECT  37.632 53.557 40.824 54.085 ;
     RECT  42.384 52.981 42.936 54.085 ;
     RECT  56.4 53.075 56.712 54.085 ;
     RECT  2.4 52.021 2.904 54.323 ;
     RECT  9.312 48.515 10.68 54.373 ;
     RECT  12.384 52.741 13.656 54.515 ;
     RECT  60.144 53.941 62.52 54.515 ;
     RECT  6.192 52.837 6.312 54.707 ;
     RECT  45.6 53.891 46.056 54.709 ;
     RECT  47.04 53.651 47.064 54.709 ;
     RECT  16.56 52.501 16.584 54.755 ;
     RECT  37.632 54.085 42.936 54.803 ;
     RECT  42.768 54.803 42.936 54.853 ;
     RECT  34.176 53.557 36.072 54.949 ;
     RECT  37.632 54.803 41.736 54.949 ;
     RECT  34.176 54.949 41.736 54.995 ;
     RECT  45.6 54.709 47.064 55.139 ;
     RECT  24 52.499 24.456 55.141 ;
     RECT  9.312 54.373 11.352 55.189 ;
     RECT  0.192 32.773 0.216 55.379 ;
     RECT  26.208 54.901 26.232 55.381 ;
     RECT  51 53.939 51.312 55.381 ;
     RECT  42.768 54.853 43.896 55.427 ;
     RECT  59.136 55.285 59.16 55.429 ;
     RECT  13.104 54.515 13.656 55.475 ;
     RECT  13.2 55.475 13.656 55.525 ;
     RECT  14.88 53.363 15.384 55.525 ;
     RECT  18.24 53.795 20.328 55.715 ;
     RECT  29.4 53.509 31.656 55.717 ;
     RECT  4.512 54.661 4.536 55.811 ;
     RECT  9.312 55.189 11.64 55.907 ;
     RECT  20.304 55.715 20.328 55.909 ;
     RECT  22.656 54.085 22.824 55.955 ;
     RECT  50.112 55.381 51.312 55.955 ;
     RECT  56.16 54.085 56.712 55.955 ;
     RECT  48.624 51.109 49.08 55.957 ;
     RECT  24 55.141 24.504 56.005 ;
     RECT  6.192 54.707 6.216 56.101 ;
     RECT  5.712 56.101 6.216 56.147 ;
     RECT  34.176 54.995 41.064 56.339 ;
     RECT  24 56.005 24.6 56.389 ;
     RECT  54.672 53.893 54.696 56.389 ;
     RECT  9.312 55.907 9.528 56.483 ;
     RECT  26.208 55.381 26.28 56.483 ;
     RECT  28.512 55.717 31.656 56.483 ;
     RECT  42.768 55.427 43.032 56.483 ;
     RECT  58.176 55.429 59.16 56.483 ;
     RECT  60.432 54.515 62.52 56.483 ;
     RECT  2.4 54.323 2.712 56.485 ;
     RECT  13.2 55.525 15.384 56.531 ;
     RECT  13.2 56.531 15 56.675 ;
     RECT  20.304 55.909 21.192 56.677 ;
     RECT  22.656 55.955 22.68 56.677 ;
     RECT  45.6 55.139 46.968 56.677 ;
     RECT  54.624 56.389 54.696 56.723 ;
     RECT  24 56.389 25.08 56.915 ;
     RECT  58.176 56.483 58.2 56.915 ;
     RECT  11.616 55.907 11.64 56.917 ;
     RECT  48.624 55.957 49.56 57.059 ;
     RECT  45.6 56.677 47.304 57.061 ;
     RECT  11.088 56.917 11.64 57.155 ;
     RECT  37.632 56.339 41.064 57.155 ;
     RECT  45.504 57.061 47.304 57.203 ;
     RECT  60.432 56.483 62.112 57.253 ;
     RECT  2.304 56.485 2.712 57.301 ;
     RECT  24 56.915 24.984 57.491 ;
     RECT  37.632 57.155 40.512 57.539 ;
     RECT  9.504 56.483 9.528 57.541 ;
     RECT  11.088 57.155 11.112 57.587 ;
     RECT  45.6 57.203 47.304 57.587 ;
     RECT  9.504 57.541 9.864 57.635 ;
     RECT  13.2 56.675 14.952 57.635 ;
     RECT  26.208 56.483 26.232 57.635 ;
     RECT  48.672 57.059 49.56 57.635 ;
     RECT  16.176 57.109 16.2 57.829 ;
     RECT  18.24 55.715 19.128 57.829 ;
     RECT  16.176 57.829 17.112 57.971 ;
     RECT  18.24 57.829 19.272 57.971 ;
     RECT  20.304 56.677 22.68 58.115 ;
     RECT  2.304 57.301 2.808 58.117 ;
     RECT  13.2 57.635 13.656 58.163 ;
     RECT  43.008 56.483 43.032 58.213 ;
     RECT  45.6 57.587 46.2 58.309 ;
     RECT  42.288 58.213 43.032 58.355 ;
     RECT  5.712 56.147 5.736 58.357 ;
     RECT  5.712 58.357 5.832 58.403 ;
     RECT  59.808 57.253 62.112 58.403 ;
     RECT  28.944 56.483 31.656 58.405 ;
     RECT  13.2 58.163 13.608 58.451 ;
     RECT  34.704 56.339 36.072 58.451 ;
     RECT  45.504 58.309 46.2 58.451 ;
     RECT  60.048 58.403 62.112 58.451 ;
     RECT  42.288 58.355 42.312 58.547 ;
     RECT  21.984 58.115 22.68 58.549 ;
     RECT  37.632 57.539 39.048 58.645 ;
     RECT  40.2 57.539 40.512 58.645 ;
     RECT  47.28 57.587 47.304 58.645 ;
     RECT  48.672 57.635 49.08 58.645 ;
     RECT  50.88 55.955 51.312 58.691 ;
     RECT  28.944 58.405 32.136 58.739 ;
     RECT  34.704 58.451 35.112 58.739 ;
     RECT  21.984 58.549 22.776 58.741 ;
     RECT  24 57.491 24.888 58.741 ;
     RECT  9.84 57.635 9.864 58.931 ;
     RECT  21.984 58.741 24.888 58.931 ;
     RECT  51 58.691 51.312 59.077 ;
     RECT  54.672 56.723 54.696 59.123 ;
     RECT  20.304 58.115 20.328 59.173 ;
     RECT  2.304 58.117 3.432 59.315 ;
     RECT  5.808 58.403 5.832 59.315 ;
     RECT  37.632 58.645 40.512 59.315 ;
     RECT  47.28 58.645 49.08 59.459 ;
     RECT  51 59.077 51.864 59.507 ;
     RECT  2.4 59.315 3.432 59.603 ;
     RECT  42.144 58.645 42.168 59.603 ;
     RECT  44.496 58.645 44.52 59.603 ;
     RECT  45.504 58.451 46.152 59.603 ;
     RECT  47.808 59.459 49.08 59.603 ;
     RECT  32.112 58.739 32.136 59.747 ;
     RECT  20.256 59.173 20.328 59.797 ;
     RECT  21.984 58.931 22.776 59.797 ;
     RECT  24 58.931 24.888 59.797 ;
     RECT  20.256 59.797 22.776 59.843 ;
     RECT  13.2 58.451 13.512 59.845 ;
     RECT  20.256 59.843 22.68 59.891 ;
     RECT  28.944 58.739 30.696 59.891 ;
     RECT  2.4 59.603 2.808 60.035 ;
     RECT  18.24 57.971 19.128 60.131 ;
     RECT  20.256 59.891 22.008 60.131 ;
     RECT  33.408 59.221 33.432 60.179 ;
     RECT  20.448 60.131 22.008 60.323 ;
     RECT  27.648 57.397 27.672 60.419 ;
     RECT  13.2 59.845 13.608 60.421 ;
     RECT  14.64 57.635 14.952 60.467 ;
     RECT  60.48 58.451 62.112 60.467 ;
     RECT  28.944 59.891 30.216 60.563 ;
     RECT  16.176 57.971 16.2 60.659 ;
     RECT  18.24 60.131 18.912 60.659 ;
     RECT  24 59.797 25.128 60.661 ;
     RECT  12.336 60.421 13.608 60.851 ;
     RECT  21.12 60.323 22.008 60.947 ;
     RECT  12.336 60.851 13.512 60.995 ;
     RECT  29.28 60.563 30.216 60.995 ;
     RECT  61.632 60.467 62.112 60.995 ;
     RECT  33.216 60.373 33.24 60.997 ;
     RECT  21.84 60.947 22.008 61.043 ;
     RECT  39.36 59.315 40.512 61.043 ;
     RECT  48.72 59.603 49.08 61.043 ;
     RECT  24 60.661 25.848 61.091 ;
     RECT  60.48 60.467 60.6 61.091 ;
     RECT  37.632 59.315 38.088 61.093 ;
     RECT  33.072 60.997 33.24 61.235 ;
     RECT  51 59.507 51.312 61.237 ;
     RECT  21.84 61.043 21.864 61.331 ;
     RECT  49.056 61.043 49.08 61.331 ;
     RECT  24 61.091 24.312 61.333 ;
     RECT  45.6 59.603 46.152 61.381 ;
     RECT  4.944 60.709 4.968 61.427 ;
     RECT  25.44 61.091 25.848 61.427 ;
     RECT  36.96 61.093 38.088 61.427 ;
     RECT  29.28 60.995 29.832 61.475 ;
     RECT  45.024 61.381 46.152 61.571 ;
     RECT  60.576 61.091 60.6 61.619 ;
     RECT  7.8 52.451 8.112 61.621 ;
     RECT  23.808 61.333 24.312 61.621 ;
     RECT  25.824 61.427 25.848 61.621 ;
     RECT  27.696 60.949 27.72 61.621 ;
     RECT  14.64 60.467 14.664 61.667 ;
     RECT  34.8 58.739 35.112 61.717 ;
     RECT  25.824 61.621 27.72 61.811 ;
     RECT  37.632 61.427 38.088 61.811 ;
     RECT  34.8 61.717 35.208 61.859 ;
     RECT  23.184 61.621 24.312 61.861 ;
     RECT  29.28 61.475 29.712 61.907 ;
     RECT  34.8 61.859 35.112 61.957 ;
     RECT  23.04 61.861 24.312 62.003 ;
     RECT  39.696 61.043 40.512 62.003 ;
     RECT  33.216 61.235 33.24 62.051 ;
     RECT  34.704 61.957 35.112 62.099 ;
     RECT  30.768 61.957 30.792 62.147 ;
     RECT  51 61.237 51.864 62.147 ;
     RECT  7.44 61.621 8.112 62.195 ;
     RECT  27.696 61.811 27.72 62.195 ;
     RECT  37.632 61.811 37.656 62.195 ;
     RECT  45.6 61.571 46.152 62.195 ;
     RECT  61.68 60.995 62.112 62.195 ;
     RECT  3.792 61.381 3.816 62.291 ;
     RECT  47.28 60.805 47.304 62.291 ;
     RECT  23.808 62.003 24.312 62.435 ;
     RECT  25.824 61.811 25.848 62.435 ;
     RECT  41.808 60.805 41.832 62.435 ;
     RECT  2.4 60.035 2.712 62.649 ;
     RECT  7.8 62.195 8.112 62.649 ;
     RECT  13.2 60.995 13.512 62.649 ;
     RECT  18.6 60.659 18.912 62.649 ;
     RECT  24 62.435 24.312 62.649 ;
     RECT  29.4 61.907 29.712 62.649 ;
     RECT  34.8 62.099 35.112 62.649 ;
     RECT  40.2 62.003 40.512 62.649 ;
     RECT  45.6 62.195 45.912 62.649 ;
     RECT  51 62.147 51.312 62.649 ;
     RECT  56.4 55.955 56.712 62.649 ;
     RECT  61.8 62.195 62.112 62.649 ;
     RECT  2.4 62.649 2.52 62.663 ;
     RECT  7.8 62.649 7.92 62.663 ;
     RECT  13.2 62.649 13.32 62.663 ;
     RECT  18.6 62.649 18.72 62.663 ;
     RECT  24 62.649 24.12 62.663 ;
     RECT  29.4 62.649 29.52 62.663 ;
     RECT  34.8 62.649 34.92 62.663 ;
     RECT  40.2 62.649 40.32 62.663 ;
     RECT  45.6 62.649 45.72 62.663 ;
     RECT  51 62.649 51.12 62.663 ;
     RECT  56.4 62.649 56.52 62.663 ;
     RECT  61.8 62.649 61.92 62.663 ;
     RECT  55.08 2.245 56.4 3.205 ;
     RECT  8.112 2.629 9.12 4.403 ;
     RECT  40.512 2.629 41.568 3.685 ;
     RECT  51.312 2.869 52.368 3.875 ;
     RECT  51.312 3.875 52.752 5.123 ;
     RECT  41.592 4.115 41.784 5.413 ;
     RECT  20.136 4.309 21.168 5.941 ;
     RECT  18.912 4.355 20.112 5.987 ;
     RECT  8.112 4.403 9.144 5.749 ;
     RECT  13.512 4.501 14.688 5.747 ;
     RECT  43.368 4.501 44.352 5.219 ;
     RECT  15.624 4.549 17.088 5.747 ;
     RECT  17.112 4.549 18.6 5.747 ;
     RECT  21.192 4.789 22.272 5.987 ;
     RECT  33.24 4.837 34.512 6.131 ;
     RECT  56.712 5.029 58.128 5.797 ;
     RECT  43.368 5.219 45.12 6.229 ;
     RECT  15.624 5.747 15.672 6.515 ;
     RECT  17.808 5.747 18.6 6.661 ;
     RECT  45.912 5.747 46.896 8.483 ;
     RECT  8.472 5.749 9.144 5.893 ;
     RECT  50.736 5.795 50.832 6.517 ;
     RECT  56.712 5.797 58.032 6.899 ;
     RECT  8.472 5.893 9.84 6.851 ;
     RECT  9.864 5.893 11.184 5.987 ;
     RECT  43.8 6.229 45.12 6.661 ;
     RECT  15.648 6.515 15.672 6.805 ;
     RECT  49.56 6.517 50.832 7.333 ;
     RECT  17.808 6.661 17.856 7.237 ;
     RECT  46.92 6.661 48.336 8.483 ;
     RECT  48.36 6.661 49.536 8.723 ;
     RECT  6.744 6.805 7.8 7.427 ;
     RECT  8.472 6.851 9.336 7.189 ;
     RECT  56.712 6.899 57.048 7.765 ;
     RECT  49.56 7.333 50.736 8.723 ;
     RECT  43.8 8.579 45.216 9.491 ;
     RECT  48.36 8.723 49.032 9.109 ;
     RECT  54.96 9.011 55.488 10.165 ;
     RECT  51.312 9.061 52.656 9.923 ;
     RECT  50.736 9.155 50.832 10.549 ;
     RECT  43.752 9.491 45.216 10.741 ;
     RECT  22.152 9.637 23.376 9.683 ;
     RECT  51.312 9.923 52.008 11.029 ;
     RECT  11.976 9.925 13.2 10.883 ;
     RECT  29.712 10.021 30.96 10.835 ;
     RECT  5.112 10.069 6.528 10.883 ;
     RECT  18.48 10.307 18.6 11.317 ;
     RECT  40.776 10.307 41.4 11.029 ;
     RECT  48.336 10.355 48.768 10.885 ;
     RECT  8.112 10.357 9.216 10.789 ;
     RECT  43.848 10.741 45.216 11.941 ;
     RECT  29.712 10.835 30.984 11.317 ;
     RECT  5.112 10.883 5.544 11.365 ;
     RECT  11.952 10.883 13.2 11.413 ;
     RECT  45.912 10.885 47.28 11.653 ;
     RECT  47.304 10.885 48.768 12.035 ;
     RECT  40.776 11.029 42 11.987 ;
     RECT  29.712 11.317 31.008 12.563 ;
     RECT  11.736 11.413 13.2 11.941 ;
     RECT  54.96 11.651 55.488 11.699 ;
     RECT  54.96 11.699 56.016 12.901 ;
     RECT  11.736 11.941 13.104 12.899 ;
     RECT  40.776 11.987 42.024 12.853 ;
     RECT  48.624 12.035 48.768 12.325 ;
     RECT  8.112 12.179 9.216 18.757 ;
     RECT  29.712 12.563 30.984 13.045 ;
     RECT  9.24 12.853 10.224 13.715 ;
     RECT  10.248 12.853 11.712 13.715 ;
     RECT  40.776 12.853 42.144 14.629 ;
     RECT  11.736 12.899 13.2 15.061 ;
     RECT  54.96 12.901 55.872 13.045 ;
     RECT  29.712 13.045 30.96 14.627 ;
     RECT  54.696 13.045 55.872 13.187 ;
     RECT  20.832 13.187 21.168 13.859 ;
     RECT  48.624 13.331 49.104 14.677 ;
     RECT  9.24 13.715 9.912 15.013 ;
     RECT  24.312 13.715 24.504 14.197 ;
     RECT  26.112 13.715 26.136 14.197 ;
     RECT  3.96 13.717 5.088 14.197 ;
     RECT  20.832 13.859 21.192 14.485 ;
     RECT  24.312 14.197 25.632 14.915 ;
     RECT  25.656 14.197 26.136 14.773 ;
     RECT  59.784 14.245 61.296 15.587 ;
     RECT  59.712 14.291 59.76 15.587 ;
     RECT  20.808 14.485 21.192 14.773 ;
     RECT  2.712 14.579 3.936 15.011 ;
     RECT  46.488 14.677 47.568 15.443 ;
     RECT  47.592 14.677 49.104 15.299 ;
     RECT  20.808 14.773 21.888 17.075 ;
     RECT  50.88 15.059 51 15.829 ;
     RECT  11.832 15.061 13.2 15.205 ;
     RECT  11.832 15.205 13.104 15.875 ;
     RECT  47.592 15.299 49.128 15.443 ;
     RECT  46.488 15.443 49.128 15.493 ;
     RECT  13.656 15.493 14.688 16.259 ;
     RECT  14.712 15.493 15.888 15.683 ;
     RECT  46.488 15.493 47.52 16.019 ;
     RECT  47.544 15.493 49.128 15.829 ;
     RECT  59.712 15.587 59.736 15.637 ;
     RECT  17.016 15.637 18.096 16.501 ;
     RECT  14.712 15.683 16.08 16.259 ;
     RECT  47.544 15.829 49.824 16.549 ;
     RECT  49.848 15.829 51 16.787 ;
     RECT  54.12 15.877 55.104 16.595 ;
     RECT  13.104 16.019 13.2 17.461 ;
     RECT  13.656 16.259 16.08 16.453 ;
     RECT  19.656 16.405 20.784 17.363 ;
     RECT  13.656 16.453 14.928 16.835 ;
     RECT  14.952 16.453 16.08 18.947 ;
     RECT  47.544 16.549 49.056 16.595 ;
     RECT  54.12 16.595 56.016 16.933 ;
     RECT  50.736 16.787 51 18.181 ;
     RECT  13.512 16.835 14.928 18.947 ;
     RECT  51.312 16.837 52.8 17.651 ;
     RECT  52.824 16.837 54.096 17.651 ;
     RECT  54.696 16.933 56.016 17.075 ;
     RECT  20.808 17.075 21.432 18.085 ;
     RECT  54.12 17.075 56.016 17.605 ;
     RECT  19.128 17.363 20.784 17.605 ;
     RECT  19.128 17.605 20.592 19.283 ;
     RECT  54.12 17.605 55.344 18.275 ;
     RECT  51.312 17.651 54.096 18.037 ;
     RECT  32.184 18.037 33.168 20.579 ;
     RECT  51.312 18.037 53.04 18.757 ;
     RECT  53.064 18.037 54.096 18.275 ;
     RECT  57.192 18.037 58.512 19.141 ;
     RECT  40.776 18.133 42.144 18.851 ;
     RECT  54.672 18.275 55.344 18.757 ;
     RECT  58.536 18.419 58.68 19.765 ;
     RECT  42.168 18.661 43.68 18.851 ;
     RECT  43.704 18.661 44.688 19.379 ;
     RECT  16.104 18.851 17.136 19.955 ;
     RECT  40.776 18.851 41.208 20.341 ;
     RECT  54.696 18.851 56.016 20.965 ;
     RECT  57.432 19.141 58.512 19.811 ;
     RECT  46.632 19.381 47.856 21.059 ;
     RECT  57.432 19.811 58.656 20.579 ;
     RECT  24.312 19.909 25.392 21.107 ;
     RECT  9.24 19.955 9.864 21.061 ;
     RECT  16.104 19.955 17.184 21.107 ;
     RECT  53.064 20.485 54.528 21.349 ;
     RECT  47.88 20.579 48.912 21.059 ;
     RECT  57.432 20.579 57.96 22.069 ;
     RECT  46.632 21.059 46.68 21.061 ;
     RECT  48.48 21.059 48.912 21.877 ;
     RECT  24.312 21.107 25.416 21.637 ;
     RECT  53.4 21.349 54.528 21.971 ;
     RECT  46.104 21.395 46.152 22.453 ;
     RECT  19.128 21.493 20.544 23.317 ;
     RECT  24.312 21.637 25.632 23.411 ;
     RECT  27.96 21.637 29.4 23.315 ;
     RECT  29.928 21.637 31.152 22.211 ;
     RECT  31.176 21.637 32.16 22.165 ;
     RECT  20.568 21.779 20.808 23.125 ;
     RECT  8.112 21.971 9.216 25.139 ;
     RECT  6.408 22.117 7.8 23.219 ;
     RECT  29.928 22.211 31.296 23.987 ;
     RECT  57.96 22.931 58.728 23.317 ;
     RECT  19.128 23.317 20.256 25.045 ;
     RECT  57.96 23.317 59.28 23.411 ;
     RECT  54.744 23.891 56.016 26.675 ;
     RECT  2.712 24.179 3.192 24.181 ;
     RECT  2.712 24.181 4.128 24.899 ;
     RECT  44.088 24.371 45.6 25.573 ;
     RECT  35.112 24.469 36.576 26.821 ;
     RECT  36.6 24.469 37.632 24.515 ;
     RECT  57 24.659 57.528 26.101 ;
     RECT  8.112 25.139 9.312 27.301 ;
     RECT  44.184 25.573 45.6 27.059 ;
     RECT  53.592 25.621 54.72 26.581 ;
     RECT  52.992 25.811 53.568 27.205 ;
     RECT  57.864 26.101 59.28 26.243 ;
     RECT  40.776 26.147 41.208 26.629 ;
     RECT  46.008 26.291 46.2 27.301 ;
     RECT  13.512 26.437 14.928 27.443 ;
     RECT  40.776 26.629 41.952 27.923 ;
     RECT  54.456 26.675 56.016 27.971 ;
     RECT  35.112 26.821 36.24 27.875 ;
     RECT  44.088 27.059 45.6 31.765 ;
     RECT  53.016 27.347 54.432 27.971 ;
     RECT  35.112 27.875 36.576 28.933 ;
     RECT  51.312 27.877 52.368 30.995 ;
     RECT  40.776 27.923 42.384 28.259 ;
     RECT  54.576 27.971 56.016 28.165 ;
     RECT  8.112 28.019 9.312 40.021 ;
     RECT  54.6 28.165 56.016 29.699 ;
     RECT  40.776 28.259 41.352 28.789 ;
     RECT  33.048 28.309 34.56 28.451 ;
     RECT  48.48 28.451 48.504 29.029 ;
     RECT  35.112 28.933 36.384 30.421 ;
     RECT  57.864 28.933 59.28 29.747 ;
     RECT  46.728 29.029 48.144 30.227 ;
     RECT  48.168 29.029 48.504 29.893 ;
     RECT  32.184 29.123 32.952 30.229 ;
     RECT  54.576 29.699 56.016 30.757 ;
     RECT  57.864 29.747 58.008 30.517 ;
     RECT  48.552 29.893 50.016 30.995 ;
     RECT  19.368 30.181 20.352 31.283 ;
     RECT  60.12 30.181 61.344 31.955 ;
     RECT  46.728 30.227 46.776 31.333 ;
     RECT  40.632 30.275 41.352 30.709 ;
     RECT  35.208 30.421 36.384 31.379 ;
     RECT  57 30.563 57.984 31.667 ;
     RECT  40.632 30.709 42.144 31.765 ;
     RECT  54.576 30.757 55.296 30.853 ;
     RECT  13.608 30.803 13.848 31.381 ;
     RECT  6.048 30.851 6.072 30.997 ;
     RECT  27.672 30.949 29.136 31.861 ;
     RECT  48.552 30.995 50.688 31.379 ;
     RECT  5.592 30.997 6.072 31.861 ;
     RECT  30.216 30.997 31.248 31.187 ;
     RECT  30.216 31.187 31.968 31.333 ;
     RECT  19.368 31.283 20.496 32.003 ;
     RECT  30.648 31.333 31.968 33.011 ;
     RECT  48.528 31.379 51 32.437 ;
     RECT  13.608 31.381 14.832 31.715 ;
     RECT  41.064 31.765 42.144 31.955 ;
     RECT  5.592 31.861 6.864 32.099 ;
     RECT  20.52 31.909 22.032 32.003 ;
     RECT  15.432 31.955 15.48 32.965 ;
     RECT  41.064 31.955 42.168 32.437 ;
     RECT  41.064 32.437 42.912 33.013 ;
     RECT  42.936 32.437 44.064 33.013 ;
     RECT  47.928 32.437 49.056 33.683 ;
     RECT  49.608 32.437 51 33.541 ;
     RECT  41.736 33.013 42.912 34.163 ;
     RECT  49.608 33.541 50.88 34.115 ;
     RECT  54.36 33.589 55.872 33.635 ;
     RECT  40.512 33.683 41.712 34.163 ;
     RECT  47.592 33.683 49.056 34.259 ;
     RECT  60.024 33.781 61.344 34.643 ;
     RECT  40.512 34.163 42.912 35.557 ;
     RECT  47.592 34.259 48.6 35.077 ;
     RECT  60 34.643 61.344 34.741 ;
     RECT  36.888 34.741 38.352 34.931 ;
     RECT  60 34.741 60.048 35.701 ;
     RECT  60.072 34.741 61.344 35.605 ;
     RECT  47.592 35.077 48.576 37.331 ;
     RECT  52.056 35.125 53.568 36.229 ;
     RECT  40.512 35.557 41.808 36.373 ;
     RECT  41.832 35.557 42.912 37.235 ;
     RECT  42.936 35.603 44.064 36.997 ;
     RECT  60.312 35.605 61.344 39.011 ;
     RECT  58.968 35.701 60.048 36.517 ;
     RECT  33.384 35.845 34.8 40.165 ;
     RECT  57 35.845 58.464 37.091 ;
     RECT  24.408 35.941 25.68 36.277 ;
     RECT  19.368 35.987 20.736 36.997 ;
     RECT  52.056 36.229 53.328 36.515 ;
     RECT  24.504 36.277 25.68 36.755 ;
     RECT  40.776 36.373 41.808 37.091 ;
     RECT  51.312 36.755 51.48 37.861 ;
     RECT  10.872 36.757 12.288 38.243 ;
     RECT  22.824 36.901 24 37.091 ;
     RECT  19.368 36.997 20.64 38.195 ;
     RECT  43.032 36.997 44.064 44.723 ;
     RECT  40.68 37.091 41.808 37.235 ;
     RECT  57 37.091 58.944 37.429 ;
     RECT  42.432 37.235 42.912 38.149 ;
     RECT  47.568 37.331 48.576 38.101 ;
     RECT  27.384 37.429 28.464 38.819 ;
     RECT  57.528 37.429 58.944 39.347 ;
     RECT  45.912 38.101 47.328 39.061 ;
     RECT  47.352 38.101 48.576 38.675 ;
     RECT  42.432 38.149 42.768 38.677 ;
     RECT  59.256 38.435 60.288 39.011 ;
     RECT  61.008 39.011 61.344 40.069 ;
     RECT  45.912 39.061 47.184 40.595 ;
     RECT  58.704 39.347 58.944 40.357 ;
     RECT  44.472 39.539 45.6 40.549 ;
     RECT  29.712 39.923 30.12 40.309 ;
     RECT  42.48 39.971 42.912 41.221 ;
     RECT  8.232 40.021 9.312 40.835 ;
     RECT  36.792 40.021 38.16 42.997 ;
     RECT  38.184 40.021 39.312 40.981 ;
     RECT  33.528 40.165 34.8 40.979 ;
     RECT  29.712 40.309 31.008 41.651 ;
     RECT  31.032 40.309 32.16 41.651 ;
     RECT  15.144 40.499 16.464 41.701 ;
     RECT  45.912 40.595 47.328 41.651 ;
     RECT  8.112 40.835 9.312 42.565 ;
     RECT  33.384 40.979 34.8 41.075 ;
     RECT  49.176 40.981 50.496 41.557 ;
     RECT  49.416 41.557 50.496 42.803 ;
     RECT  29.712 41.651 32.16 42.709 ;
     RECT  40.512 41.651 40.68 43.141 ;
     RECT  49.152 41.651 49.392 42.709 ;
     RECT  58.704 41.651 58.968 41.845 ;
     RECT  15.144 41.701 16.368 44.051 ;
     RECT  16.488 41.747 17.568 44.051 ;
     RECT  58.704 41.845 59.136 42.133 ;
     RECT  57.096 42.133 58.128 42.227 ;
     RECT  58.152 42.133 59.136 42.995 ;
     RECT  39.048 42.227 40.2 44.245 ;
     RECT  56.712 42.227 58.128 42.995 ;
     RECT  8.232 42.565 9.312 43.573 ;
     RECT  29.712 42.709 31.584 42.853 ;
     RECT  30.6 42.853 31.584 44.435 ;
     RECT  10.872 42.901 12.24 43.187 ;
     RECT  56.712 42.995 59.136 44.341 ;
     RECT  35.112 42.997 36.096 43.571 ;
     RECT  24.456 43.285 25.536 44.773 ;
     RECT  33.336 43.285 34.8 43.861 ;
     RECT  44.472 43.331 45.504 44.915 ;
     RECT  35.112 43.571 36.24 45.541 ;
     RECT  36.264 43.763 37.488 44.627 ;
     RECT  33.336 43.861 34.704 44.483 ;
     RECT  16.848 44.051 17.568 44.869 ;
     RECT  31.608 44.195 32.832 44.867 ;
     RECT  56.712 44.341 58.128 45.731 ;
     RECT  58.152 44.341 59.136 44.867 ;
     RECT  42.936 44.723 44.064 45.205 ;
     RECT  24.552 44.773 25.536 45.059 ;
     RECT  44.088 44.915 45.6 49.619 ;
     RECT  24.552 45.059 25.176 46.261 ;
     RECT  41.112 45.205 42.48 45.251 ;
     RECT  42.936 45.205 43.968 46.259 ;
     RECT  35.208 45.541 36.24 47.317 ;
     RECT  55.32 45.541 56.304 46.067 ;
     RECT  8.112 45.587 9.312 56.483 ;
     RECT  59.928 45.829 61.056 46.019 ;
     RECT  39.048 45.971 40.2 47.411 ;
     RECT  59.928 46.019 61.344 47.315 ;
     RECT  13.104 46.067 13.2 47.173 ;
     RECT  55.32 46.067 56.4 47.891 ;
     RECT  13.608 46.069 15.12 46.739 ;
     RECT  42.936 46.259 44.064 47.749 ;
     RECT  58.632 46.693 59.904 47.315 ;
     RECT  15.384 46.789 16.8 46.931 ;
     RECT  15.336 46.931 16.8 47.653 ;
     RECT  46.008 47.123 46.824 48.421 ;
     RECT  60.912 47.315 61.344 47.363 ;
     RECT  20.28 47.317 21.408 48.133 ;
     RECT  60.912 47.363 61.68 48.805 ;
     RECT  39 47.411 40.2 51.637 ;
     RECT  15.336 47.653 16.512 47.893 ;
     RECT  36.312 47.749 37.824 47.891 ;
     RECT  56.256 47.891 56.4 48.133 ;
     RECT  16.008 48.323 17.04 48.467 ;
     RECT  20.328 48.371 21.648 49.331 ;
     RECT  13.512 48.421 14.928 49.045 ;
     RECT  42.936 48.515 44.064 49.619 ;
     RECT  17.04 49.043 17.568 50.437 ;
     RECT  13.656 49.045 14.928 49.813 ;
     RECT  42.936 49.619 43.416 50.629 ;
     RECT  50.16 49.715 50.208 50.389 ;
     RECT  13.656 49.813 14.88 50.677 ;
     RECT  33.672 50.101 34.8 50.821 ;
     RECT  51.312 50.149 52.656 51.875 ;
     RECT  48.696 50.389 50.208 50.965 ;
     RECT  15.384 50.437 16.704 51.685 ;
     RECT  4.776 50.485 5.952 50.531 ;
     RECT  26.232 50.579 27.312 52.211 ;
     RECT  40.512 50.629 41.856 51.923 ;
     RECT  13.656 50.677 14.736 53.363 ;
     RECT  33.672 50.821 34.704 50.867 ;
     RECT  22.824 50.917 24 51.541 ;
     RECT  49.08 50.965 50.208 53.939 ;
     RECT  20.328 51.203 21.048 52.213 ;
     RECT  27.336 51.637 28.464 52.499 ;
     RECT  39 51.637 40.08 52.693 ;
     RECT  15.528 51.685 16.704 51.779 ;
     RECT  15.528 51.779 17.568 51.827 ;
     RECT  15.384 51.827 17.568 51.923 ;
     RECT  51.312 51.875 52.632 52.021 ;
     RECT  10.68 51.877 12.096 51.973 ;
     RECT  12.12 51.877 13.104 52.403 ;
     RECT  15.384 51.923 16.584 52.501 ;
     RECT  40.512 51.923 40.824 52.981 ;
     RECT  42.384 51.923 42.816 52.981 ;
     RECT  10.68 51.973 12.048 52.115 ;
     RECT  25.128 51.973 26.208 52.163 ;
     RECT  51.312 52.021 52.608 53.603 ;
     RECT  10.68 52.115 12.096 52.403 ;
     RECT  46.728 52.163 46.824 53.557 ;
     RECT  21.24 52.213 22.656 53.603 ;
     RECT  4.536 52.357 5.952 52.451 ;
     RECT  12.384 52.403 13.104 52.741 ;
     RECT  6.216 52.405 7.68 52.451 ;
     RECT  6.216 52.451 7.8 52.837 ;
     RECT  22.68 52.499 24 54.085 ;
     RECT  28.224 52.499 29.4 53.077 ;
     RECT  15.384 52.501 16.56 54.755 ;
     RECT  39.048 52.693 40.08 53.557 ;
     RECT  6.312 52.837 7.8 54.707 ;
     RECT  28.248 53.077 29.4 53.651 ;
     RECT  4.512 53.363 4.536 54.661 ;
     RECT  13.656 53.363 14.88 55.525 ;
     RECT  60.168 53.557 61.2 53.941 ;
     RECT  21.192 53.603 22.656 53.795 ;
     RECT  46.056 53.651 47.04 54.709 ;
     RECT  49.08 53.939 51 55.381 ;
     RECT  22.824 54.085 24 55.955 ;
     RECT  54.696 54.085 56.16 55.955 ;
     RECT  11.352 54.373 12.384 54.515 ;
     RECT  11.352 54.515 13.104 55.189 ;
     RECT  60.144 54.515 60.432 55.285 ;
     RECT  41.736 54.803 42.768 54.995 ;
     RECT  11.64 55.189 13.104 55.475 ;
     RECT  59.16 55.285 60.432 56.483 ;
     RECT  49.08 55.381 50.112 55.955 ;
     RECT  56.712 55.429 58.176 56.915 ;
     RECT  19.128 55.715 20.304 57.829 ;
     RECT  11.088 55.907 11.616 56.917 ;
     RECT  21.192 55.909 22.656 56.677 ;
     RECT  22.68 55.955 24 58.549 ;
     RECT  49.08 55.955 50.88 55.957 ;
     RECT  49.56 55.957 50.88 57.635 ;
     RECT  25.08 56.389 26.208 56.915 ;
     RECT  8.112 56.483 9.504 57.635 ;
     RECT  26.232 56.483 26.28 57.397 ;
     RECT  28.512 56.483 28.944 57.397 ;
     RECT  59.808 56.483 60.432 57.253 ;
     RECT  15 56.531 15.384 56.675 ;
     RECT  14.952 56.675 15.384 57.109 ;
     RECT  47.304 56.677 48.624 57.059 ;
     RECT  24.984 56.915 26.208 57.491 ;
     RECT  47.304 57.059 48.672 58.645 ;
     RECT  14.952 57.109 16.176 60.467 ;
     RECT  45.504 57.203 45.6 58.309 ;
     RECT  26.232 57.397 27.648 57.635 ;
     RECT  27.672 57.397 28.944 60.419 ;
     RECT  24.888 57.491 26.208 57.635 ;
     RECT  39.048 57.539 40.2 58.645 ;
     RECT  9.864 57.541 11.088 57.587 ;
     RECT  46.2 57.587 47.28 58.451 ;
     RECT  13.656 57.635 14.64 58.163 ;
     RECT  17.112 57.829 18.24 57.971 ;
     RECT  19.272 57.829 20.304 57.971 ;
     RECT  19.128 57.971 20.304 59.173 ;
     RECT  13.608 58.163 14.64 58.451 ;
     RECT  13.512 58.451 14.64 59.845 ;
     RECT  46.152 58.451 47.28 59.459 ;
     RECT  22.776 58.549 24 58.741 ;
     RECT  44.52 58.645 45.504 59.603 ;
     RECT  30.696 58.739 32.112 59.747 ;
     RECT  34.704 58.739 34.8 59.221 ;
     RECT  22.776 58.931 24 59.843 ;
     RECT  19.128 59.173 20.256 60.131 ;
     RECT  32.136 59.221 33.408 59.747 ;
     RECT  33.432 59.221 34.8 60.179 ;
     RECT  38.088 59.315 39.36 61.043 ;
     RECT  46.152 59.459 47.808 59.603 ;
     RECT  46.152 59.603 48.72 60.805 ;
     RECT  33.072 59.747 33.408 60.179 ;
     RECT  22.68 59.843 24 59.891 ;
     RECT  13.608 59.845 14.64 60.851 ;
     RECT  23.808 59.891 24 61.333 ;
     RECT  2.712 60.035 2.808 61.381 ;
     RECT  33.072 60.179 33.24 60.373 ;
     RECT  33.072 60.373 33.216 60.997 ;
     RECT  27.648 60.419 28.944 60.563 ;
     RECT  14.664 60.467 16.176 60.659 ;
     RECT  60.6 60.467 61.632 60.995 ;
     RECT  27.648 60.563 27.72 60.949 ;
     RECT  40.512 60.805 41.808 62.435 ;
     RECT  46.152 60.805 47.28 62.195 ;
     RECT  47.304 60.805 48.72 61.043 ;
     RECT  13.512 60.851 14.64 61.667 ;
     RECT  27.648 60.949 27.696 61.621 ;
     RECT  29.832 60.995 30.216 61.475 ;
     RECT  60.6 60.995 61.68 61.619 ;
     RECT  24.312 61.091 25.44 61.427 ;
     RECT  2.712 61.381 3.792 62.291 ;
     RECT  3.816 61.381 4.944 61.427 ;
     RECT  24.312 61.427 25.824 62.435 ;
     RECT  29.712 61.475 30.216 61.957 ;
     RECT  29.712 61.957 30.768 62.147 ;
     RECT  33.24 61.957 34.704 62.051 ;
     RECT  45.912 62.195 47.28 62.291 ;
  END
END ot_hbm_native_bounded_cdc
END LIBRARY
